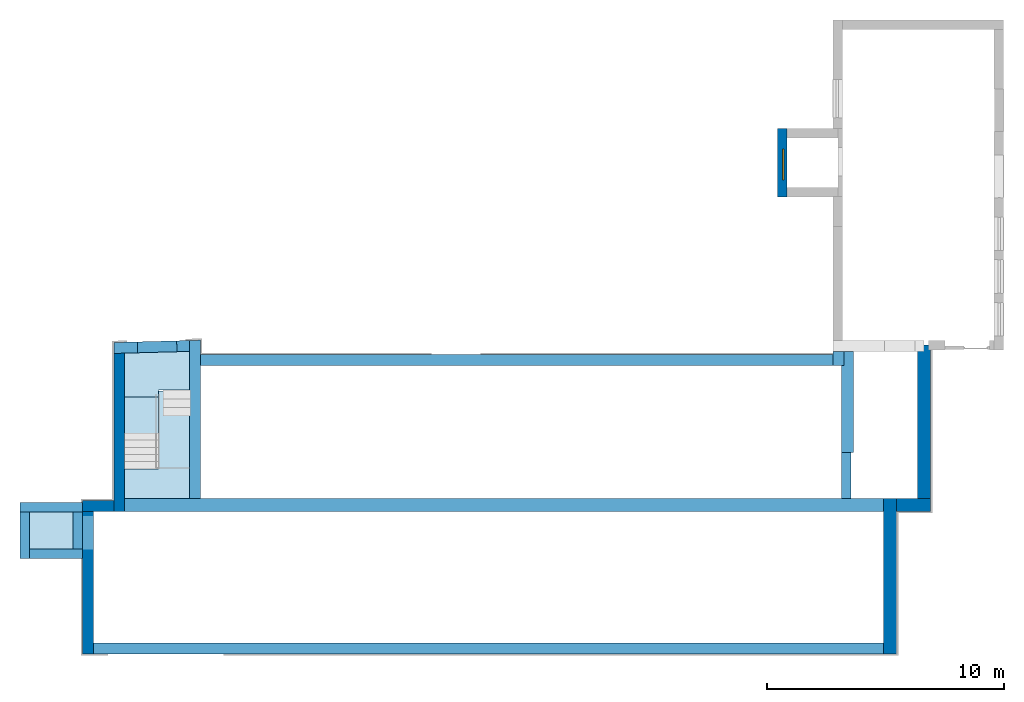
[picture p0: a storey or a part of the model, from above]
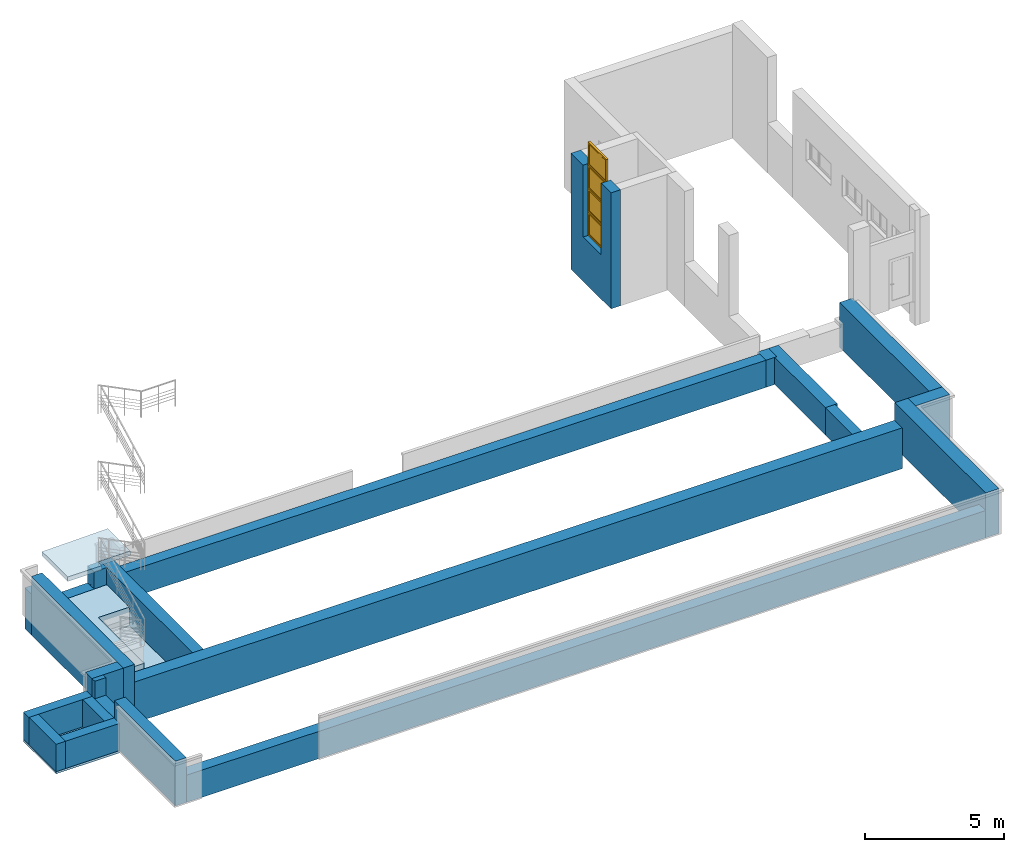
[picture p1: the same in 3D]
Properties of the parts of a building model (IFC2X3), part 1 of 5

# File
Description: ViewDefinition [CoordinationView_V2.0]
File name: P-1806
Time: 2020-05-27T14:10:02
Written by: The EXPRESS Data Manager Version 5.02.0100.07 : 28 Aug 2013
Made in: 20180216_1515(x64) - Exporter 19.0.0.405 - Alternate UI 19.1.0.0
Comment: STEP Physical File produced by: The EXPRESS Data Manager Version 5.02.0100.07 : 28 Aug 2013 * Module: EDMstepFileFactory/EDMstandAlone * Creation date: Wed May 27 14:10:02 2020 * Host: DESKTOP-ODL27HC * Database: C:\Users\kasutaja\AppData\Local\Temp\{E8C4CF71-2A94-4640-A6D8-2AE83B0C9C89}\ifc * Database version: 5507 * Database creation date: Wed May 27 14:09:39 2020 * Schema: IFC2X3 * Model: DataRepository.ifc * Model creation date: Wed May 27 14:09:40 2020 * Header model: DataRepository.ifc_HeaderModel * Header model creation date: Wed May 27 14:09:40 2020 * EDMuser: sdai-user * EDMgroup: sdai-group * License ID and type: 5605 : Permanent license. Expiry date: * EDMstepFileFactory options: 020000

# IfcProject, P-1806
LongName: Tartu Riigimaja, Riia 15 rekonstrueerimine; Phase: TP

# IfcSite, Surface:834248
RefLatitude: 59, 25, 2, 668762; RefLongitude: 24, 45, 13, 526916; RefElevation: 0 mm

# IfcBuilding
Pset_BuildingCommon - NumberOfStoreys: 11

# IfcBuildingStorey (11)
Name | LongName | Elevation (mm)
Vundament | Vundament | -1200
uus 1 korrus | uus 1 korrus | -135
1 korrus | 1 korrus | 3.097e-10
2 korrus | 2 korrus | 3350
uus 2 korrus | uus 2 korrus | 3875
3 korrus | 3 korrus | 6730.43
uus 3 korrus | uus 3 korrus | 7670
4 korrus | 4 korrus | 10060
uus Katus | uus Katus | 11805
Katusekorrus | Katusekorrus | 13600
Katus vent. | Katus vent. | 13800

# IfcSpace (128)
InteriorOrExteriorSpace: INTERNAL
Pset_SpaceCommon - Category: Rooms
Name | In | LongName = Nimetus | Reference | Nr | Kategooria / tüüp
101 | 1 korrus | Tuulekoda | Tuulekoda 101 | 101 | Avatud netopind
102 | 1 korrus | Vastuvõtt | Vastuvõtt 102 | 102 | Üüritavpind
103 | 1 korrus | Lift | Lift 103 | 103 | Vertikaalne ühendustee
105 | 1 korrus | Tuulekoda | Tuulekoda 105 | 105 | Avatud netopind
107 | 1 korrus | Koridor | Koridor 107 | 107 | Avatud netopind
108 | 1 korrus | WC | WC 108 | 108 | Avatud netopind
109 | 1 korrus | Riietusruum | Riietusruum 109 | 109 | Avatud netopind
110 | 1 korrus | Pesupesemise ruum | Pesupesemise ruum 110 | 110 | Avatud netopind
111 | 1 korrus | Dušširuum | Dušširuum 111 | 111 | Avatud netopind
112 | 1 korrus | Riietusruum | Riietusruum 112 | 112 | Avatud netopind
113 | 1 korrus | Dušširuum | Dušširuum 113 | 113 | Avatud netopind
114 | 1 korrus | Tuulekoda | Tuulekoda 114 | 114 | Avatud netopind
116 | 1 korrus | Büroo | Büroo 116 | 116 | Üüritavpind
115 | 1 korrus | Büroo | Büroo 115 | 115 | Üüritavpind
118 | 1 korrus | Klienditeenindamise saal (MTA+SKA) | Klienditeenindamise saal (MTA+SKA) 118 | 118 | Üüritavpind
120 | 1 korrus | Vestlusruum | Vestlusruum 120 | 120 | Üüritavpind
122 | 1 korrus | Koridor | Koridor 122 | 122 | Avatud netopind
123 | 1 korrus | Büroo | Büroo 123 | 123 | Üüritavpind
124 | 1 korrus | Koristusruum | Koristusruum 124 | 124 | Avatud netopind
125 | 1 korrus | WC | WC 125 | 125 | Avatud netopind
126 | 1 korrus | Trepikoda | Trepikoda 126 | 126 | Avatud netopind
128 | 1 korrus | Soojussõlm | Soojussõlm 128 | 128 | Tehniline pind
127 | 1 korrus | Ladu | Ladu 127 | 127 | Üüritavpind
201 | 2 korrus | Trepikoda | Trepikoda 201 | 201 | Vertikaalne ühendustee
202 | 2 korrus | Koridor | Koridor 202 | 202 | Avatud netopind
203 | 2 korrus | Lift | Lift 203 | 203 | Vertikaalne ühendustee
204 | 2 korrus | Nõupidamine | Nõupidamine 204 | 204 | Üüritavpind
205 | 2 korrus | Koridor | Koridor 205 | 205 | Avatud netopind
214 | 2 korrus | Puhkeruum | Puhkeruum 214 | 214 | Üüritavpind
217 | 2 korrus | Büroo | Büroo 217 | 217 | Üüritavpind
218 | 2 korrus | Koridor | Koridor 218 | 218 | Avatud netopind
219 | 2 korrus | WC | WC 219 | 219 | Avatud netopind
220 | 2 korrus | WC | WC 220 | 220 | Avatud netopind
222 | 2 korrus | Trepikoda | Trepikoda 222 | 222 | Vertikaalne ühendustee
223 | uus 2 korrus | Koridor | Koridor 223 | 223 | Avatud netopind
224 | uus 2 korrus | Eesruum | Eesruum 224 | 224 | Avatud netopind
225 | uus 2 korrus | Büroo | Büroo 225 | 225 | Üüritavpind
226 | uus 2 korrus | Koridor | Koridor 226 | 226 | Avatud netopind
227 | uus 2 korrus | WC | WC 227 | 227 | Avatud netopind
228 | uus 2 korrus | Büroo | Büroo 228 | 228 | Üüritavpind
229 | uus 2 korrus | Büroo | Büroo 229 | 229 | Üüritavpind
230 | uus 2 korrus | Büroo | Büroo 230 | 230 | Üüritavpind
231 | uus 2 korrus | Büroo | Büroo 231 | 231 | Üüritavpind
129 | uus 1 korrus | Tuulekoda | Tuulekoda 129 | 129 | Avatud netopind
130 | uus 1 korrus | Ooteala | Ooteala 130 | 130 | Üüritavpind
132 | uus 1 korrus | Koridor | Koridor 132 | 132 | Avatud netopind
133 | uus 1 korrus | WC | WC 133 | 133 | Avatud netopind
134 | uus 1 korrus | Riietusruum | Riietusruum 134 | 134 | Avatud netopind
135 | uus 1 korrus | Dušširuum | Dušširuum 135 | 135 | Avatud netopind
136 | uus 1 korrus | Varustuse ladu | Varustuse ladu 136 | 136 | Üüritavpind
138 | uus 1 korrus | Toiduproovide vastuvõtt | Toiduproovide vastuvõtt 138 | 138 | Üüritavpind
139 | uus 1 korrus | Tööruum | Tööruum 139 | 139 | Üüritavpind
140 | uus 1 korrus | Proovide vastuvõtt | Proovide vastuvõtt 140 | 140 | Üüritavpind
301 | 3 korrus | Trepikoda | Trepikoda 301 | 301 | Vertikaalne ühendustee
302 | 3 korrus | Koridor | Koridor 302 | 302 | Avatud netopind
303 | 3 korrus | Lift | Lift 303 | 303 | Vertikaalne ühendustee
304 | 3 korrus | Kaugtöökohad | Kaugtöökohad 304 | 304 | Üüritavpind
305 | 3 korrus | Koridor | Koridor 305 | 305 | Avatud netopind
306 | 3 korrus | Büroo | Büroo 306 | 306 | Üüritavpind
307 | 3 korrus | Büroo | Büroo 307 | 307 | Üüritavpind
308 | 3 korrus | Telo | Telo 308 | 308 | Üüritavpind
309 | 3 korrus | Büroo | Büroo 309 | 309 | Üüritavpind
310 | 3 korrus | Büroo | Büroo 310 | 310 | Üüritavpind
311 | 3 korrus | Büroo | Büroo 311 | 311 | Üüritavpind
312 | 3 korrus | Büroo | Büroo 312 | 312 | Üüritavpind
313 | 3 korrus | Büroo | Büroo 313 | 313 | Üüritavpind
314 | 3 korrus | Vestla | Vestla 314 | 314 | Üüritavpind
315 | 3 korrus | Puhkeruum | Puhkeruum 315 | 315 | Üüritavpind
316 | 3 korrus | Büroo | Büroo 316 | 316 | Üüritavpind
317 | 3 korrus | Büroo | Büroo 317 | 317 | Üüritavpind
318 | 3 korrus | Büroo | Büroo 318 | 318 | Üüritavpind
319 | 3 korrus | Abiruum | Abiruum 319 | 319 | Üüritavpind
320 | 3 korrus | Koridor | Koridor 320 | 320 | Avatud netopind
321 | 3 korrus | WC | WC 321 | 321 | Avatud netopind
322 | 3 korrus | WC | WC 322 | 322 | Avatud netopind
324 | 3 korrus | Trepikoda | Trepikoda 324 | 324 | Vertikaalne ühendustee
325 | 3 korrus | Server | Server 325 | 325 | Tehniline pind
326 | uus 3 korrus | Koridor | Koridor 326 | 326 | Avatud netopind
327 | uus 3 korrus | Koridor | Koridor 327 | 327 | Avatud netopind
330 | uus 3 korrus | Nõupidamine | Nõupidamine 330 | 330 | Üüritavpind
331 | uus 3 korrus | Büroo | Büroo 331 | 331 | Üüritavpind
401 | 4 korrus | Trepikoda | Trepikoda 401 | 401 | Vertikaalne ühendustee
402 | 4 korrus | Koridor | Koridor 402 | 402 | Avatud netopind
403 | 4 korrus | Lift | Lift 403 | 403 | Vertikaalne ühendustee
404 | 4 korrus | Büroo | Büroo 404 | 404 | Üüritavpind
405 | 4 korrus | Koridor | Koridor 405 | 405 | Avatud netopind
413 | 4 korrus | Puhkeruum | Puhkeruum 413 | 413 | Üüritavpind
414 | 4 korrus | Büroo | Büroo 414 | 414 | Üüritavpind
416 | 4 korrus | Büroo | Büroo 416 | 416 | Üüritavpind
417 | 4 korrus | Büroo | Büroo 417 | 417 | Üüritavpind
418 | 4 korrus | Nõupidamine | Nõupidamine 418 | 418 | Üüritavpind
419 | 4 korrus | Koridor | Koridor 419 | 419 | Avatud netopind
420 | 4 korrus | WC | WC 420 | 420 | Avatud netopind
421 | 4 korrus | WC | WC 421 | 421 | Avatud netopind
423 | 4 korrus | Trepikoda | Trepikoda 423 | 423 | Vertikaalne ühendustee
501 | Katusekorrus | Lift | Lift 501 | 501 | Vertikaalne ühendustee
328 | uus 3 korrus | Büroo | Büroo 328 | 328 | Üüritavpind
329 | uus 3 korrus | WC | WC 329 | 329 | Avatud netopind
117 | 1 korrus | Büroo | Büroo 117 | 117 | Üüritavpind
406 | 4 korrus | Büroo | Büroo 406 | 406 | Üüritavpind
408 | 4 korrus | Vestla | Vestla 408 | 408 | Üüritavpind
409 | 4 korrus | Büroo | Büroo 409 | 409 | Üüritavpind
410 | 4 korrus | Vestla | Vestla 410 | 410 | Üüritavpind
411 | 4 korrus | Garderoob | Garderoob 411 | 411 | Üüritavpind
412 | 4 korrus | Kontoritarbed | Kontoritarbed 412 | 412 | Üüritavpind
206 | 2 korrus | Büroo | Büroo 206 | 206 | Üüritavpind
207 | 2 korrus | Telo | Telo 207 | 207 | Üüritavpind
208 | 2 korrus | Büroo | Büroo 208 | 208 | Üüritavpind
209 | 2 korrus | Büroo | Büroo 209 | 209 | Üüritavpind
210 | 2 korrus | Büroo | Büroo 210 | 210 | Üüritavpind
215 | 2 korrus | Dok.hoidla | Dok.hoidla 215 | 215 | Üüritavpind
216 | 2 korrus | Büroo | Büroo 216 | 216 | Üüritavpind
503 | Katusekorrus | Vent.ruum | Vent.ruum 503 | 503 | Tehniline pind
141 | 1 korrus | Ladu PMA | Ladu PMA 141 | 141 | Üüritavpind
142 | 1 korrus | Ladu KKA | Ladu KKA 142 | 142 | Üüritavpind
211 | 2 korrus | Vestla | Vestla 211 | 211 | Üüritavpind
212 | 2 korrus | Büroo | Büroo 212 | 212 | Üüritavpind
139 | uus 1 korrus | Nõrkvooluruum | Nõrkvooluruum 139 | 139 | Tehniline pind
143 | uus 1 korrus | Abiruum | Abiruum 143 | 143 | Üüritavpind
502 | Katusekorrus | Vent.ruum | Vent.ruum 502 | 502 | Tehniline pind
131 | uus 1 korrus | Vastuvõtt | Vastuvõtt 131 | 131 | Üüritavpind
106 | 1 korrus | INVA WC | INVA WC 106 | 106 | Avatud netopind
104 | 1 korrus | Trepikoda | Trepikoda 104 | 104 | Avatud netopind
119 | 1 korrus | Vestlusruum | Vestlusruum 119 | 119 | Üüritavpind
121 | 1 korrus | Vestlusruum | Vestlusruum 121 | 121 | Üüritavpind
132a | uus 1 korrus | Lift | Lift 132a | 132a | Vertikaalne ühendustee
226a | uus 2 korrus | Lift | Lift 226a | 226a | Vertikaalne ühendustee
327a | uus 3 korrus | Lift | Lift 327a | 327a | Vertikaalne ühendustee

# IfcBuildingElementProxy: Reeper, Reeper1:Reeper:1055131
In: 1 korrus
Material: GEE-punane
Pset_BuildingElementProxyCommon - Reference: Reeper

# IfcColumn: 250x250, Betoon post:250x250:506675
In: 1 korrus
Type - ElementType: 250x250; PredefinedType: COLUMN
Material: Betoon
Pset_ColumnCommon - LoadBearing: no; IsExternal: no; Reference: 250x250; Slope: 0 deg

# IfcColumn: D200, Pipe-Column:D200:1313115
In: uus 1 korrus
Type - ElementType: D200; PredefinedType: COLUMN; Classification: B10 Superstructure (Uniformat)
Material: Metal - Steel - ASTM A53
Pset_ColumnCommon - IsExternal: no; LoadBearing: yes; Slope: 0 deg; Reference: D200

# IfcColumn: GENEERILINE - KONSTRUKTRIOON 260 x 260 (2)
In: 1 korrus
Type - ElementType: GENEERILINE - KONSTRUKTRIOON 260 x 260; PredefinedType: COLUMN
Material: GENEERILINE - KONSTRUKTRIOON
Pset_ColumnCommon - LoadBearing: no; IsExternal: no; Reference: GENEERILINE - KONSTRUKTRIOON 260 x 260; Slope: 5156.62 deg

# IfcCurtainWall: Curtain Wall:Klaasfassaad (2)
In: 3 korrus
Pset_CurtainWallCommon - IsExternal: yes; Reference: Klaasfassaad
AR_IFC_SEINAD - 01.Nimetus: Klaasfassaad; 02.Materjal: Klaas+alumiinium; 04.Tulepüsivus: -; 05.Asukoha info: Exterior; 06.Kandevelementide eristatud: nonbearing; 07.Helipidavus: 34 dB; 06.Soojusläbivus: 1,0W/m2K; Phase Created: New Construction
Name (Curtain Wall:Klaasfassaad:...) | 03.Kategooria / tüüp | Group
1451082 | KLF-01 | Model Group:KLF-01:1450670
1658890 | KLF-05 | Model Group:KLF-04:1658778

# IfcCurtainWall: Curtain Wall:Klaasfassaad2 (2)
In: 3 korrus
Pset_CurtainWallCommon - IsExternal: yes; Reference: Klaasfassaad2
AR_IFC_SEINAD - 01.Nimetus: Klaasfassaad; 02.Materjal: Klaas+alumiinium; 04.Tulepüsivus: -; 05.Asukoha info: Exterior; 06.Kandevelementide eristatud: nonbearing; 07.Helipidavus: 34 dB; 06.Soojusläbivus: 1,0W/m2K; Phase Created: New Construction
Name (Curtain Wall:Klaasfassaad2:...) | 03.Kategooria / tüüp | Group
1453336 | KLF-02 | Model Group:KLF-02:1453116
1660883 | KLF-03 | Model Group:KLF-03:1660694

# IfcCurtainWall: Curtain Wall:Klaassein KLS-01 (2)
In: 1 korrus
Pset_CurtainWallCommon - IsExternal: no; Reference: Klaassein KLS-01
AR_IFC_SEINAD - 01.Nimetus: Klaassein; 02.Materjal: Klaas; 03.Kategooria / tüüp: KLS-01; 04.Tulepüsivus: -; 05.Asukoha info: Interior; 06.Kandevelementide eristatud: nonbearing; 07.Helipidavus: 40 dB; 06.Soojusläbivus: -; Phase Created: New Construction
Name (Curtain Wall:Klaassein KLS-01:...)
329681
1662676

# IfcCurtainWall: Curtain Wall:Klaassein KLS-02, Curtain Wall:Klaassein KLS-02:341501
In: 1 korrus
Pset_CurtainWallCommon - IsExternal: no; Reference: Klaassein KLS-02
AR_IFC_SEINAD - 01.Nimetus: Klaassein; 02.Materjal: Klaas; 03.Kategooria / tüüp: KLS-02; 04.Tulepüsivus: -; 05.Asukoha info: Interior; 06.Kandevelementide eristatud: nonbearing; 07.Helipidavus: 40 dB; 06.Soojusläbivus: -; Phase Created: New Construction

# IfcCurtainWall: Curtain Wall:Klaassein KLS-03, Curtain Wall:Klaassein KLS-03:495734
In: 1 korrus
Pset_CurtainWallCommon - IsExternal: no; Reference: Klaassein KLS-03
AR_IFC_SEINAD - 01.Nimetus: Klaassein; 02.Materjal: Klaas; 03.Kategooria / tüüp: KLS-03; 04.Tulepüsivus: -; 05.Asukoha info: Interior; 06.Kandevelementide eristatud: nonbearing; 07.Helipidavus: 40 dB; 06.Soojusläbivus: -; Phase Created: New Construction

# IfcCurtainWall: Curtain Wall:Klaassein KLS-04, Curtain Wall:Klaassein KLS-04:489045
In: 1 korrus
Pset_CurtainWallCommon - IsExternal: no; Reference: Klaassein KLS-04
AR_IFC_SEINAD - 01.Nimetus: Klaassein; 02.Materjal: Klaas; 03.Kategooria / tüüp: KLS-04; 04.Tulepüsivus: -; 05.Asukoha info: Interior; 06.Kandevelementide eristatud: nonbearing; 07.Helipidavus: 40 dB; 06.Soojusläbivus: -; Phase Created: New Construction

# IfcCurtainWall: Curtain Wall:Klaassein KLS-05 (2)
In: 2 korrus
Pset_CurtainWallCommon - IsExternal: no; Reference: Klaassein KLS-05
AR_IFC_SEINAD - 01.Nimetus: Klaassein; 02.Materjal: Klaas; 03.Kategooria / tüüp: KLS-05; 04.Tulepüsivus: -; 05.Asukoha info: Interior; 06.Kandevelementide eristatud: nonbearing; 07.Helipidavus: 40 dB; 06.Soojusläbivus: -; Phase Created: New Construction
Name (Curtain Wall:Klaassein KLS-05:...)
1333739
1334402

# IfcCurtainWall: Curtain Wall:Klaassein KLS-07 (3)
Pset_CurtainWallCommon - IsExternal: no; Reference: Klaassein KLS-07
AR_IFC_SEINAD - 01.Nimetus: Klaassein; 02.Materjal: Klaas; 03.Kategooria / tüüp: KLS-07; 04.Tulepüsivus: -; 05.Asukoha info: Interior; 06.Kandevelementide eristatud: nonbearing; 07.Helipidavus: 40 dB; 06.Soojusläbivus: -; Phase Created: New Construction
Name (Curtain Wall:Klaassein KLS-07:...) | In
515357 | 2 korrus
569290 | 3 korrus
580453 | 4 korrus

# IfcCurtainWall: Curtain Wall:Klaassein KLS-08, Curtain Wall:Klaassein KLS-08:555677
In: 2 korrus
Pset_CurtainWallCommon - IsExternal: no; Reference: Klaassein KLS-08
AR_IFC_SEINAD - 01.Nimetus: Klaassein; 02.Materjal: Klaas; 03.Kategooria / tüüp: KLS-08; 04.Tulepüsivus: -; 05.Asukoha info: Interior; 06.Kandevelementide eristatud: nonbearing; 07.Helipidavus: 40 dB; 06.Soojusläbivus: -; Phase Created: New Construction

# IfcCurtainWall: Curtain Wall:Klaassein KLS-09, Curtain Wall:Klaassein KLS-09:555087
In: 2 korrus
Pset_CurtainWallCommon - IsExternal: no; Reference: Klaassein KLS-09
AR_IFC_SEINAD - 01.Nimetus: Klaassein; 02.Materjal: Klaas; 03.Kategooria / tüüp: KLS-09; 04.Tulepüsivus: -; 05.Asukoha info: Interior; 06.Kandevelementide eristatud: nonbearing; 07.Helipidavus: 40 dB; 06.Soojusläbivus: -; Phase Created: New Construction

# IfcCurtainWall: Curtain Wall:Klaassein KLS-10 (2)
Pset_CurtainWallCommon - IsExternal: no; Reference: Klaassein KLS-10
AR_IFC_SEINAD - 01.Nimetus: Klaassein; 02.Materjal: Klaas; 04.Tulepüsivus: -; 05.Asukoha info: Interior; 06.Kandevelementide eristatud: nonbearing; 07.Helipidavus: 40 dB; 06.Soojusläbivus: -; Phase Created: New Construction
Name (Curtain Wall:Klaassein KLS-10:...) | In | 03.Kategooria / tüüp
575476 | 3 korrus | KLS-01
1117689 | 2 korrus | KLS-10

# IfcCurtainWall: Curtain Wall:Klaassein KLS-11, Curtain Wall:Klaassein KLS-11:520277
In: 2 korrus
Pset_CurtainWallCommon - IsExternal: no; Reference: Klaassein KLS-11
AR_IFC_SEINAD - 01.Nimetus: Klaassein; 02.Materjal: Klaas; 03.Kategooria / tüüp: KLS-11; 04.Tulepüsivus: -; 05.Asukoha info: Interior; 06.Kandevelementide eristatud: nonbearing; 07.Helipidavus: 40 dB; 06.Soojusläbivus: -; Phase Created: New Construction

# IfcCurtainWall: Curtain Wall:Klaassein KLS-12 (2)
Pset_CurtainWallCommon - IsExternal: no; Reference: Klaassein KLS-12
AR_IFC_SEINAD - 01.Nimetus: Klaassein; 02.Materjal: Klaas; 03.Kategooria / tüüp: KLS-12; 04.Tulepüsivus: -; 05.Asukoha info: Interior; 06.Kandevelementide eristatud: nonbearing; 07.Helipidavus: 40 dB; 06.Soojusläbivus: -; Phase Created: New Construction
Name (Curtain Wall:Klaassein KLS-12:...) | In
930844 | uus 2 korrus
1005810 | uus 3 korrus

# IfcCurtainWall: Curtain Wall:Klaassein KLS-13, Curtain Wall:Klaassein KLS-13:930512
In: uus 2 korrus
Pset_CurtainWallCommon - IsExternal: no; Reference: Klaassein KLS-13
AR_IFC_SEINAD - 01.Nimetus: Klaassein; 02.Materjal: Klaas; 03.Kategooria / tüüp: KLS-13; 04.Tulepüsivus: -; 05.Asukoha info: Interior; 06.Kandevelementide eristatud: nonbearing; 07.Helipidavus: 40 dB; 06.Soojusläbivus: -; Phase Created: New Construction

# IfcCurtainWall: Curtain Wall:Klaassein KLS-14, Curtain Wall:Klaassein KLS-14:930147
In: uus 2 korrus
Pset_CurtainWallCommon - IsExternal: no; Reference: Klaassein KLS-14
AR_IFC_SEINAD - 01.Nimetus: Klaassein; 02.Materjal: Klaas; 03.Kategooria / tüüp: KLS-14; 04.Tulepüsivus: -; 05.Asukoha info: Interior; 06.Kandevelementide eristatud: nonbearing; 07.Helipidavus: 40 dB; 06.Soojusläbivus: -; Phase Created: New Construction

# IfcCurtainWall: Curtain Wall:Klaassein KLS-15, Curtain Wall:Klaassein KLS-15:927985
In: uus 2 korrus
Pset_CurtainWallCommon - IsExternal: no; Reference: Klaassein KLS-15
AR_IFC_SEINAD - 01.Nimetus: Klaassein; 02.Materjal: Klaas; 03.Kategooria / tüüp: KLS-15; 04.Tulepüsivus: -; 05.Asukoha info: Interior; 06.Kandevelementide eristatud: nonbearing; 07.Helipidavus: 40 dB; 06.Soojusläbivus: -; Phase Created: New Construction

# IfcCurtainWall: Curtain Wall:Klaassein KLS-16, Curtain Wall:Klaassein KLS-16:929398
In: uus 2 korrus
Pset_CurtainWallCommon - IsExternal: no; Reference: Klaassein KLS-16
AR_IFC_SEINAD - 01.Nimetus: Klaassein; 02.Materjal: Klaas; 03.Kategooria / tüüp: KLS-16; 04.Tulepüsivus: -; 05.Asukoha info: Interior; 06.Kandevelementide eristatud: nonbearing; 07.Helipidavus: 40 dB; 06.Soojusläbivus: -; Phase Created: New Construction

# IfcCurtainWall: Curtain Wall:Klaassein KLS-17, Curtain Wall:Klaassein KLS-17:568486
In: 3 korrus
Pset_CurtainWallCommon - IsExternal: no; Reference: Klaassein KLS-17
AR_IFC_SEINAD - 01.Nimetus: Klaassein; 02.Materjal: Klaas; 03.Kategooria / tüüp: KLS-17; 04.Tulepüsivus: -; 05.Asukoha info: Interior; 06.Kandevelementide eristatud: nonbearing; 07.Helipidavus: 40 dB; 06.Soojusläbivus: -; Phase Created: New Construction

# IfcCurtainWall: Curtain Wall:Klaassein KLS-18, Curtain Wall:Klaassein KLS-18:567760
In: 3 korrus
Pset_CurtainWallCommon - IsExternal: no; Reference: Klaassein KLS-18
AR_IFC_SEINAD - 01.Nimetus: Klaassein; 02.Materjal: Klaas; 03.Kategooria / tüüp: KLS-18; 04.Tulepüsivus: -; 05.Asukoha info: Interior; 06.Kandevelementide eristatud: nonbearing; 07.Helipidavus: 40 dB; 06.Soojusläbivus: -; Phase Created: New Construction

# IfcCurtainWall: Curtain Wall:Klaassein KLS-19, Curtain Wall:Klaassein KLS-19:562941
In: 3 korrus
Pset_CurtainWallCommon - IsExternal: no; Reference: Klaassein KLS-19
AR_IFC_SEINAD - 01.Nimetus: Klaassein; 02.Materjal: Klaas; 03.Kategooria / tüüp: KLS-19; 04.Tulepüsivus: -; 05.Asukoha info: Interior; 06.Kandevelementide eristatud: nonbearing; 07.Helipidavus: 40 dB; 06.Soojusläbivus: -; Phase Created: New Construction

# IfcCurtainWall: Curtain Wall:Klaassein KLS-20 (2)
Pset_CurtainWallCommon - IsExternal: no; Reference: Klaassein KLS-20
AR_IFC_SEINAD - 01.Nimetus: Klaassein; 02.Materjal: Klaas; 03.Kategooria / tüüp: KLS-20; 04.Tulepüsivus: -; 05.Asukoha info: Interior; 06.Kandevelementide eristatud: nonbearing; 07.Helipidavus: 40 dB; 06.Soojusläbivus: -; Phase Created: New Construction
Name (Curtain Wall:Klaassein KLS-20:...) | In
562882 | 3 korrus
563014 | 4 korrus

# IfcCurtainWall: Curtain Wall:Klaassein KLS-21, Curtain Wall:Klaassein KLS-21:574380
In: 3 korrus
Pset_CurtainWallCommon - IsExternal: no; Reference: Klaassein KLS-21
AR_IFC_SEINAD - 01.Nimetus: Klaassein; 02.Materjal: Klaas; 03.Kategooria / tüüp: KLS-21; 04.Tulepüsivus: -; 05.Asukoha info: Interior; 06.Kandevelementide eristatud: nonbearing; 07.Helipidavus: 40 dB; 06.Soojusläbivus: -; Phase Created: New Construction

# IfcCurtainWall: Curtain Wall:Klaassein KLS-22, Curtain Wall:Klaassein KLS-22:574861
In: 3 korrus
Pset_CurtainWallCommon - IsExternal: no; Reference: Klaassein KLS-22
AR_IFC_SEINAD - 01.Nimetus: Klaassein; 02.Materjal: Klaas; 03.Kategooria / tüüp: KLS-22; 04.Tulepüsivus: -; 05.Asukoha info: Interior; 06.Kandevelementide eristatud: nonbearing; 07.Helipidavus: 40 dB; 06.Soojusläbivus: -; Phase Created: New Construction

# IfcCurtainWall: Curtain Wall:Klaassein KLS-23, Curtain Wall:Klaassein KLS-23:934556
In: uus 3 korrus
Pset_CurtainWallCommon - IsExternal: no; Reference: Klaassein KLS-23
AR_IFC_SEINAD - 01.Nimetus: Klaassein; 02.Materjal: Klaas; 03.Kategooria / tüüp: KLS-23; 04.Tulepüsivus: -; 05.Asukoha info: Interior; 06.Kandevelementide eristatud: nonbearing; 07.Helipidavus: 40 dB; 06.Soojusläbivus: -; Phase Created: New Construction

# IfcCurtainWall: Curtain Wall:Klaassein KLS-24, Curtain Wall:Klaassein KLS-24:580407
In: 4 korrus
Pset_CurtainWallCommon - IsExternal: no; Reference: Klaassein KLS-24
AR_IFC_SEINAD - 01.Nimetus: Klaassein; 02.Materjal: Klaas; 03.Kategooria / tüüp: KLS-24; 04.Tulepüsivus: -; 05.Asukoha info: Interior; 06.Kandevelementide eristatud: nonbearing; 07.Helipidavus: 40 dB; 06.Soojusläbivus: -; Phase Created: New Construction

# IfcCurtainWall: Curtain Wall:Klaassein KLS-25, Curtain Wall:Klaassein KLS-25:581564
In: 4 korrus
Pset_CurtainWallCommon - IsExternal: no; Reference: Klaassein KLS-25
AR_IFC_SEINAD - 01.Nimetus: Klaassein; 02.Materjal: Klaas; 03.Kategooria / tüüp: KLS-25; 04.Tulepüsivus: -; 05.Asukoha info: Interior; 06.Kandevelementide eristatud: nonbearing; 07.Helipidavus: 40 dB; 06.Soojusläbivus: -; Phase Created: New Construction

# IfcCurtainWall: Curtain Wall:Klaassein KLS-26, Curtain Wall:Klaassein KLS-26:581264
In: 4 korrus
Pset_CurtainWallCommon - IsExternal: no; Reference: Klaassein KLS-26
AR_IFC_SEINAD - 01.Nimetus: Klaassein; 02.Materjal: Klaas; 03.Kategooria / tüüp: KLS-26; 04.Tulepüsivus: -; 05.Asukoha info: Interior; 06.Kandevelementide eristatud: nonbearing; 07.Helipidavus: 40 dB; 06.Soojusläbivus: -; Phase Created: New Construction

# IfcCurtainWall: Curtain Wall:Klaassein KLS-27, Curtain Wall:Klaassein KLS-27:580366
In: 4 korrus
Pset_CurtainWallCommon - IsExternal: no; Reference: Klaassein KLS-27
AR_IFC_SEINAD - 01.Nimetus: Klaassein; 02.Materjal: Klaas; 03.Kategooria / tüüp: KLS-27; 04.Tulepüsivus: -; 05.Asukoha info: Interior; 06.Kandevelementide eristatud: nonbearing; 07.Helipidavus: 40 dB; 06.Soojusläbivus: -; Phase Created: New Construction

# IfcCurtainWall: Curtain Wall:Klaassein KLS-28, Curtain Wall:Klaassein KLS-28:1304981
In: 4 korrus
Pset_CurtainWallCommon - IsExternal: no; Reference: Klaassein KLS-28
AR_IFC_SEINAD - 01.Nimetus: Sisesein; 02.Materjal: Kips; 03.Kategooria / tüüp: SS-3; 04.Tulepüsivus: -; 05.Asukoha info: Interior; 06.Kandevelementide eristatud: nonbearing; 07.Helipidavus: 48dB; 06.Soojusläbivus: -; Phase Created: New Construction

# IfcDistributionControlElement: ATS, Control_Unit-Suppression_System-Kidde_Fire_Systems-ARIES:ATS:1090340
In: 101
Type - Material: Steel - Kidde Fenwal - Red
Pset_ManufacturerTypeInformation - Manufacturer: Kidde Fire Systems

# IfcDoor: 1000x2100_klaasiga_välisuks (2)
Type - OperationType: FOLDING_TO_LEFT; ParameterTakesPrecedence: no; Sizeable: no; Material: _Alumiiniumprofiil - must, Steel/Aluminium, Glass
Type - Ühepoolsed:1000x2100_klaasiga_välisuks:923893 - PanelOperation: FOLDING
OverallHeight: 2100 mm; OverallWidth: 2240 mm
Pset_DoorCommon - IsExternal: no; Reference: 1000x2100_klaasiga_välisuks
Name (Ühepoolsed:1000x2100_klaasiga_välisuks:...) | In
923893 | uus 2 korrus
933235 | uus 3 korrus

# IfcDoor: 1000x2200_välisuks klaasiga (2)
In: uus 1 korrus
Type - OperationType: FOLDING_TO_LEFT; ParameterTakesPrecedence: no; Sizeable: no; Material: _Alumiiniumprofiil - must, Steel/Aluminium, Glass
Type - Ühepoolsed:1000x2200_välisuks klaasiga:394254 - PanelOperation: FOLDING
OverallHeight: 2200 mm; OverallWidth: 1000 mm
Pset_DoorCommon - IsExternal: yes; Reference: 1000x2200_välisuks klaasiga
AR_IFC_UKSED - 01.Nimetus: Välisuks; 02.Materjal: Alumiinium; 05.Asukoha info: Exterior; 06.Soojusläbivus: 1.0 W/m²K; 07.Helipidavus: 34 dB; 08.Veepidavus: 7A; 09.Õhuläbilaskvus: klass 4; 10.Tulekindlus: -; 11.Vastupanu tulekoormusele: C3; 12.Klaaspakett: 3x klaaspakett; 13.Klaasingu erisused: Tripleksklaas; 14.Päikesekiirgus tegur (g-väärtus): 0.6; 15.Avanemine: Folding to Right; 16.Liigendatus: kahepoolne; 17.Sulused, lukustus: ASSA ABLOY liugveovarrega sulgur, sulgemisjärjesti; 18.Viimistlus: RAL8019; 19.Mudel või toote tunnus: -; 20.Tootja: -
Name (Ühepoolsed:1000x2200_välisuks klaasiga:...) | 03.Kategooria / tüüp | 04.Avamõõdu geomeetria
394254 | VU-08 | 1600x2650
408534 | VU-07 | 1800x2650

# IfcDoor: KONE_LDO_KES600_2L_P28_L1 (2)
In: uus 1 korrus
Type - OperationType: FOLDING_TO_LEFT; ParameterTakesPrecedence: no; Sizeable: no; Material: Glass, Default
Type - KONE_LDO_KES600_2L_P28_L1:KONE_LDO_KES600_2L_P28_L1:1652579 - PanelOperation: FOLDING
OverallHeight: 2944 mm; OverallWidth: 1522 mm
Pset_DoorCommon - IsExternal: no; Reference: KONE_LDO_KES600_2L_P28_L1
Name (KONE_LDO_KES600_2L_P28_L1:KONE_LDO_KES600_2L_P28_L1:...)
1652579
1652580

# IfcDoor: KONE_LDO_KES600_2L_P28_L1, KONE_LDO_KES600_2L_P28_L1:KONE_LDO_KES600_2L_P28_L1:1652581
In: uus 1 korrus
Type - OperationType: FOLDING_TO_LEFT; ParameterTakesPrecedence: no; Sizeable: no; Material: Glass, Default
Type - KONE_LDO_KES600_2L_P28_L1:KONE_LDO_KES600_2L_P28_L1:1652581 - PanelOperation: FOLDING
OverallHeight: 2944 mm; OverallWidth: 1522 mm
Pset_DoorCommon - IsExternal: no; Reference: KONE_LDO_KES600_2L_P28_L1

# IfcDoor: Klaasuks (30)
Type - ParameterTakesPrecedence: no; Sizeable: no; Classification: B2030100 Glazed Doors & Entrances (Uniformat); Material: Glass, Aluminum
Pset_DoorCommon - IsExternal: no; Reference: Klaasuks
Name (Door-Curtain-Wall-Single-Glass:Klaasuks:...) | In | OverallHeight (mm) | OverallWidth (mm)
489052 | 1 korrus | 2090 | 890
495741 | 1 korrus | 2090 | 880
515378 | 2 korrus | 2110 | 880
1337265 | 2 korrus | 2080 | 888.452
1116301 | 2 korrus | 2090 | 890
555684 | 2 korrus | 2080 | 880
562889 | 3 korrus | 2080 | 880
562942 | 3 korrus | 2090 | 891
563021 | 4 korrus | 2080 | 880
567767 | 3 korrus | 2090 | 880
1101094 | 3 korrus | 2080 | 880
569308 | 3 korrus | 2110 | 880
574387 | 3 korrus | 2080 | 880
574868 | 3 korrus | 2080 | 880
575483 | 3 korrus | 2090 | 880
580373 | 4 korrus | 2090 | 880
580414 | 4 korrus | 2090 | 880
580471 | 4 korrus | 2110 | 880
581282 | 4 korrus | 2110 | 880
581600 | 4 korrus | 2110 | 880
1458226 | uus 2 korrus | 2500 | 880
927990 | uus 2 korrus | 2500 | 880
930150 | uus 2 korrus | 2500 | 880
930515 | uus 2 korrus | 2500 | 880
930845 | uus 2 korrus | 2500 | 890
934559 | uus 3 korrus | 2500 | 880
1005811 | uus 3 korrus | 2500 | 890
1117694 | 2 korrus | 2090 | 756.991
1333746 | 2 korrus | 2080 | 880
1334409 | 2 korrus | 2080 | 880

# IfcDoor: Manteluks (3)
In: 1 korrus
Type - ParameterTakesPrecedence: no; Sizeable: no; Classification: B2030100 Glazed Doors & Entrances (Uniformat); Material: __Uks_hele tamm, Aluminum
OverallHeight: 2080 mm
Pset_DoorCommon - IsExternal: no; Reference: Manteluks
Name (Door-Curtain-Wall-Single-Glass:Manteluks:...) | OverallWidth (mm)
329688 | 888
341508 | 892
1662683 | 888

# IfcDoor: SU-01, Ühepoolsed:SU-01:1080922
In: 4 korrus
Type - OperationType: FOLDING_TO_LEFT; ParameterTakesPrecedence: no; Sizeable: no; Material: _Alumiiniumprofiil - must, __Uks_hele tamm, Glass
Type - Ühepoolsed:SU-01:1080922 - PanelOperation: FOLDING
OverallHeight: 2100 mm; OverallWidth: 800 mm
Pset_DoorCommon - IsExternal: no; Reference: SU-01
AR_IFC_UKSED - 01.Nimetus: Siseuks; 02.Materjal: Puit; 03.Kategooria / tüüp: SU-01; 04.Avamõõdu geomeetria: 800x2100; 05.Asukoha info: Interior; 06.Soojusläbivus: -; 07.Helipidavus: 34 dB; 08.Veepidavus: -; 09.Õhuläbilaskvus: -; 10.Tulekindlus: -; 11.Vastupanu tulekoormusele: -; 12.Klaaspakett: karastatud klaas; 13.Klaasingu erisused: -; 14.Päikesekiirgus tegur (g-väärtus): -; 15.Avanemine: Folding to Right; 16.Liigendatus: -; 17.Sulused, lukustus: -; 18.Viimistlus: Tammespoon; 19.Mudel või toote tunnus: -; 20.Tootja: -

# IfcDoor: SU-01., Ühepoolsed:SU-01.:1080916
In: 4 korrus
Type - OperationType: FOLDING_TO_LEFT; ParameterTakesPrecedence: no; Sizeable: no; Material: _Alumiiniumprofiil - must, __Uks_hele tamm, Glass
Type - Ühepoolsed:SU-01.:1080916 - PanelOperation: FOLDING
OverallHeight: 2100 mm; OverallWidth: 800 mm
Pset_DoorCommon - IsExternal: no; Reference: SU-01.
AR_IFC_UKSED - 01.Nimetus: Siseuks; 02.Materjal: Puit; 03.Kategooria / tüüp: SU-01; 04.Avamõõdu geomeetria: 800x2100; 05.Asukoha info: Interior; 06.Soojusläbivus: -; 07.Helipidavus: 34 dB; 08.Veepidavus: -; 09.Õhuläbilaskvus: -; 10.Tulekindlus: -; 11.Vastupanu tulekoormusele: -; 12.Klaaspakett: karastatud klaas; 13.Klaasingu erisused: -; 14.Päikesekiirgus tegur (g-väärtus): -; 15.Avanemine: Folding to Left; 16.Liigendatus: -; 17.Sulused, lukustus: -; 18.Viimistlus: Tammespoon; 19.Mudel või toote tunnus: -; 20.Tootja: -

# IfcDoor: SU-02, Ühepoolsed:SU-02:239855
In: 4 korrus
Type - OperationType: FOLDING_TO_LEFT; ParameterTakesPrecedence: no; Sizeable: no; Material: _Alumiiniumprofiil - must, __Uks_hele tamm, Glass
Type - Ühepoolsed:SU-02:239855 - PanelOperation: FOLDING
OverallHeight: 2100 mm; OverallWidth: 900 mm
Pset_DoorCommon - IsExternal: no; Reference: SU-02
AR_IFC_UKSED - 01.Nimetus: Siseuks; 02.Materjal: Puit; 03.Kategooria / tüüp: SU-02; 04.Avamõõdu geomeetria: 900x2100; 05.Asukoha info: Interior; 06.Soojusläbivus: -; 07.Helipidavus: 34 dB; 08.Veepidavus: -; 09.Õhuläbilaskvus: -; 10.Tulekindlus: -; 11.Vastupanu tulekoormusele: -; 12.Klaaspakett: karastatud klaas; 13.Klaasingu erisused: -; 14.Päikesekiirgus tegur (g-väärtus): -; 15.Avanemine: Folding to Right; 16.Liigendatus: -; 17.Sulused, lukustus: -; 18.Viimistlus: Tammespoon; 19.Mudel või toote tunnus: -; 20.Tootja: -

# IfcDoor: SU-02 (6)
Type - OperationType: FOLDING_TO_LEFT; ParameterTakesPrecedence: no; Sizeable: no; Material: _Alumiiniumprofiil - must, __Uks_hele tamm, Glass
Type - Ühepoolsed:SU-02:323160 - PanelOperation: FOLDING
OverallHeight: 2100 mm; OverallWidth: 900 mm
Pset_DoorCommon - IsExternal: no; Reference: SU-02
Name (Ühepoolsed:SU-02:...) | In | 01.Nimetus | 02.Materjal | 03.Kategooria / tüüp | 04.Avamõõdu geomeetria | 05.Asukoha info | 06.Soojusläbivus = 08.Veepidavus = 09.Õhuläbilaskvus = 10.Tulekindlus = 11.Vastupanu tulekoormusele = 13.Klaasingu erisused = 14.Päikesekiirgus tegur (g-väärtus) = 16.Liigendatus = 17.Sulused, lukustus = 19.Mudel või toote tunnus = 20.Tootja | 07.Helipidavus | 12.Klaaspakett | 15.Avanemine | 18.Viimistlus
323160 | 1 korrus | Siseuks | Puit | SU-02 | 900x2100 | Interior | - | 34 dB | karastatud klaas | Folding to Right | Tammespoon
498907 | uus 1 korrus | Siseuks | Puit | SU-02 | 900x2100 | Interior | - | 34 dB | karastatud klaas | Folding to Right | Tammespoon
900490 | uus 1 korrus | Siseuks | Puit | SU-02 | 900x2100 | Interior | - | 34 dB | karastatud klaas | Folding to Right | Tammespoon
900544 | uus 1 korrus | Siseuks | Puit | SU-02 | 900x2100 | Interior | - | 34 dB | karastatud klaas | Folding to Right | Tammespoon
934430 | uus 3 korrus | Siseuks | Puit | SU-02 | 900x2100 | Interior | - | 34 dB | karastatud klaas | Folding to Right | Tammespoon
1746923 | 4 korrus

# IfcDoor: SU-02, Ühepoolsed:SU-02:557840
In: 2 korrus
Type - OperationType: FOLDING_TO_LEFT; ParameterTakesPrecedence: no; Sizeable: no; Material: _Alumiiniumprofiil - must, __Uks_hele tamm, Glass
Type - Ühepoolsed:SU-02:557840 - PanelOperation: FOLDING
OverallHeight: 2100 mm; OverallWidth: 900 mm
Pset_DoorCommon - IsExternal: no; Reference: SU-02
AR_IFC_UKSED - 01.Nimetus: Siseuks; 02.Materjal: Puit; 03.Kategooria / tüüp: SU-02; 04.Avamõõdu geomeetria: 900x2100; 05.Asukoha info: Interior; 06.Soojusläbivus: -; 07.Helipidavus: 34 dB; 08.Veepidavus: -; 09.Õhuläbilaskvus: -; 10.Tulekindlus: -; 11.Vastupanu tulekoormusele: -; 12.Klaaspakett: karastatud klaas; 13.Klaasingu erisused: -; 14.Päikesekiirgus tegur (g-väärtus): -; 15.Avanemine: Folding to Right; 16.Liigendatus: -; 17.Sulused, lukustus: -; 18.Viimistlus: Tammespoon; 19.Mudel või toote tunnus: -; 20.Tootja: -

# IfcDoor: SU-02., Ühepoolsed:SU-02.:1316792
In: uus 1 korrus
Type - OperationType: FOLDING_TO_LEFT; ParameterTakesPrecedence: no; Sizeable: no; Material: _Alumiiniumprofiil - must, __Uks_hele tamm, Glass
Type - Ühepoolsed:SU-02.:1316792 - PanelOperation: FOLDING
OverallHeight: 2100 mm; OverallWidth: 900 mm
Pset_DoorCommon - IsExternal: no; Reference: SU-02.
AR_IFC_UKSED - 01.Nimetus: Siseuks; 02.Materjal: Puit; 03.Kategooria / tüüp: SU-02; 04.Avamõõdu geomeetria: 900x2100; 05.Asukoha info: Interior; 06.Soojusläbivus: -; 07.Helipidavus: 34 dB; 08.Veepidavus: -; 09.Õhuläbilaskvus: -; 10.Tulekindlus: -; 11.Vastupanu tulekoormusele: -; 12.Klaaspakett: karastatud klaas; 13.Klaasingu erisused: -; 14.Päikesekiirgus tegur (g-väärtus): -; 15.Avanemine: Folding to Left; 16.Liigendatus: -; 17.Sulused, lukustus: -; 18.Viimistlus: Tammespoon; 19.Mudel või toote tunnus: -; 20.Tootja: -

# IfcDoor: SU-02. (2)
Type - OperationType: FOLDING_TO_LEFT; ParameterTakesPrecedence: no; Sizeable: no; Material: _Alumiiniumprofiil - must, __Uks_hele tamm, Glass
Type - Ühepoolsed:SU-02.:239851 - PanelOperation: FOLDING
OverallHeight: 2100 mm; OverallWidth: 900 mm
Pset_DoorCommon - IsExternal: no; Reference: SU-02.
AR_IFC_UKSED - 01.Nimetus: Siseuks; 02.Materjal: Puit; 03.Kategooria / tüüp: SU-02; 04.Avamõõdu geomeetria: 900x2100; 05.Asukoha info: Interior; 06.Soojusläbivus: -; 07.Helipidavus: 34 dB; 08.Veepidavus: -; 09.Õhuläbilaskvus: -; 10.Tulekindlus: -; 11.Vastupanu tulekoormusele: -; 12.Klaaspakett: karastatud klaas; 13.Klaasingu erisused: -; 14.Päikesekiirgus tegur (g-väärtus): -; 15.Avanemine: Folding to Left; 16.Liigendatus: -; 17.Sulused, lukustus: -; 18.Viimistlus: Tammespoon; 19.Mudel või toote tunnus: -; 20.Tootja: -
Name (Ühepoolsed:SU-02.:...) | In
239851 | 4 korrus
1077138 | 1 korrus

# IfcDoor: SU-03, Ühepoolsed:SU-03:557605
In: 2 korrus
Type - OperationType: FOLDING_TO_LEFT; ParameterTakesPrecedence: no; Sizeable: no; Material: _Alumiiniumprofiil - must, __Uks_hele tamm, Glass
Type - Ühepoolsed:SU-03:557605 - PanelOperation: FOLDING
OverallHeight: 2100 mm; OverallWidth: 950 mm
Pset_DoorCommon - IsExternal: no; Reference: SU-03
AR_IFC_UKSED - 01.Nimetus: Siseuks; 02.Materjal: Puit; 03.Kategooria / tüüp: SU-03; 04.Avamõõdu geomeetria: 950x2100; 05.Asukoha info: Interior; 06.Soojusläbivus: -; 07.Helipidavus: 34 dB; 08.Veepidavus: -; 09.Õhuläbilaskvus: -; 10.Tulekindlus: -; 11.Vastupanu tulekoormusele: -; 12.Klaaspakett: karastatud klaas; 13.Klaasingu erisused: -; 14.Päikesekiirgus tegur (g-väärtus): -; 15.Avanemine: Folding to Right; 16.Liigendatus: -; 17.Sulused, lukustus: -; 18.Viimistlus: Tammespoon; 19.Mudel või toote tunnus: -; 20.Tootja: -

# IfcDoor: SU-03 (3)
In: 3 korrus
Type - OperationType: FOLDING_TO_LEFT; ParameterTakesPrecedence: no; Sizeable: no; Material: _Alumiiniumprofiil - must, __Uks_hele tamm, Glass
Type - Ühepoolsed:SU-03:571676 - PanelOperation: FOLDING
OverallHeight: 2100 mm; OverallWidth: 950 mm
Pset_DoorCommon - IsExternal: no; Reference: SU-03
AR_IFC_UKSED - 01.Nimetus: Siseuks; 02.Materjal: Puit; 03.Kategooria / tüüp: SU-03; 05.Asukoha info: Interior; 06.Soojusläbivus: -; 07.Helipidavus: 34 dB; 08.Veepidavus: -; 09.Õhuläbilaskvus: -; 10.Tulekindlus: -; 11.Vastupanu tulekoormusele: -; 12.Klaaspakett: karastatud klaas; 13.Klaasingu erisused: -; 14.Päikesekiirgus tegur (g-väärtus): -; 15.Avanemine: Folding to Right; 16.Liigendatus: -; 17.Sulused, lukustus: -; 18.Viimistlus: Tammespoon; 19.Mudel või toote tunnus: -; 20.Tootja: -
Name (Ühepoolsed:SU-03:...) | 04.Avamõõdu geomeetria
571676 | 1000x2100
571746 | 1000x2100
572865 | 950x2100

# IfcDoor: SU-03. (3)
In: 2 korrus
Type - OperationType: FOLDING_TO_LEFT; ParameterTakesPrecedence: no; Sizeable: no; Material: _Alumiiniumprofiil - must, __Uks_hele tamm, Glass
Type - Ühepoolsed:SU-03.:556845 - PanelOperation: FOLDING
OverallHeight: 2100 mm; OverallWidth: 950 mm
Pset_DoorCommon - IsExternal: no; Reference: SU-03.
AR_IFC_UKSED - 01.Nimetus: Siseuks; 02.Materjal: Puit; 03.Kategooria / tüüp: SU-03; 05.Asukoha info: Interior; 06.Soojusläbivus: -; 07.Helipidavus: 34 dB; 08.Veepidavus: -; 09.Õhuläbilaskvus: -; 10.Tulekindlus: -; 11.Vastupanu tulekoormusele: -; 12.Klaaspakett: karastatud klaas; 13.Klaasingu erisused: -; 14.Päikesekiirgus tegur (g-väärtus): -; 15.Avanemine: Folding to Left; 16.Liigendatus: -; 17.Sulused, lukustus: -; 18.Viimistlus: Tammespoon; 19.Mudel või toote tunnus: -; 20.Tootja: -
Name (Ühepoolsed:SU-03.:...) | 04.Avamõõdu geomeetria
556845 | 1000x2100
1119601 | 950x2100
1119721 | 950x2100

# IfcDoor: SU-03. (3)
In: 3 korrus
Type - OperationType: FOLDING_TO_LEFT; ParameterTakesPrecedence: no; Sizeable: no; Material: _Alumiiniumprofiil - must, __Uks_hele tamm, Glass
Type - Ühepoolsed:SU-03.:571561 - PanelOperation: FOLDING
OverallHeight: 2100 mm; OverallWidth: 950 mm
Pset_DoorCommon - IsExternal: no; Reference: SU-03.
AR_IFC_UKSED - 01.Nimetus: Siseuks; 02.Materjal: Puit; 03.Kategooria / tüüp: SU-03; 05.Asukoha info: Interior; 06.Soojusläbivus: -; 07.Helipidavus: 34 dB; 08.Veepidavus: -; 09.Õhuläbilaskvus: -; 10.Tulekindlus: -; 11.Vastupanu tulekoormusele: -; 12.Klaaspakett: karastatud klaas; 13.Klaasingu erisused: -; 14.Päikesekiirgus tegur (g-väärtus): -; 15.Avanemine: Folding to Left; 16.Liigendatus: -; 17.Sulused, lukustus: -; 18.Viimistlus: Tammespoon; 19.Mudel või toote tunnus: -; 20.Tootja: -
Name (Ühepoolsed:SU-03.:...) | 04.Avamõõdu geomeetria
571561 | 1000x2100
572231 | 950x2100
572708 | 950x2100

# IfcDoor: SU-04, Ühepoolsed:SU-04:325530
In: 1 korrus
Type - OperationType: FOLDING_TO_LEFT; ParameterTakesPrecedence: no; Sizeable: no; Material: _Alumiiniumprofiil - must, __Uks_hele tamm, Glass
Type - Ühepoolsed:SU-04:325530 - PanelOperation: FOLDING
OverallHeight: 2300 mm; OverallWidth: 1030 mm
Pset_DoorCommon - IsExternal: no; Reference: SU-04
AR_IFC_UKSED - 01.Nimetus: Siseuks; 02.Materjal: Puit; 03.Kategooria / tüüp: SU-04; 04.Avamõõdu geomeetria: 1030x2300; 05.Asukoha info: Interior; 06.Soojusläbivus: -; 07.Helipidavus: 34 dB; 08.Veepidavus: -; 09.Õhuläbilaskvus: -; 10.Tulekindlus: -; 11.Vastupanu tulekoormusele: -; 12.Klaaspakett: karastatud klaas; 13.Klaasingu erisused: -; 14.Päikesekiirgus tegur (g-väärtus): -; 15.Avanemine: Folding to Right; 16.Liigendatus: -; 17.Sulused, lukustus: -; 18.Viimistlus: Tammespoon; 19.Mudel või toote tunnus: -; 20.Tootja: -

# IfcDoor: SU-05, Ühepoolsed:SU-05:342177
In: 1 korrus
Type - OperationType: FOLDING_TO_LEFT; ParameterTakesPrecedence: no; Sizeable: no; Material: _Alumiiniumprofiil - must, __Uks_hele tamm
Type - Ühepoolsed:SU-05:342177 - PanelOperation: FOLDING
OverallHeight: 2100 mm; OverallWidth: 800 mm
Pset_DoorCommon - IsExternal: no; Reference: SU-05
AR_IFC_UKSED - 01.Nimetus: Siseuks; 02.Materjal: Puit; 03.Kategooria / tüüp: SU-05; 04.Avamõõdu geomeetria: 800x2100; 05.Asukoha info: Interior; 06.Soojusläbivus: -; 07.Helipidavus: -; 08.Veepidavus: -; 09.Õhuläbilaskvus: -; 10.Tulekindlus: -; 11.Vastupanu tulekoormusele: -; 12.Klaaspakett: -; 13.Klaasingu erisused: -; 14.Päikesekiirgus tegur (g-väärtus): -; 15.Avanemine: Folding to Right; 16.Liigendatus: -; 17.Sulused, lukustus: -; 18.Viimistlus: Tammespoon; 19.Mudel või toote tunnus: -; 20.Tootja: -

# IfcDoor: SU-05, Ühepoolsed:SU-05:342365
In: 1 korrus
Type - OperationType: FOLDING_TO_LEFT; ParameterTakesPrecedence: no; Sizeable: no; Material: _Alumiiniumprofiil - must, __Uks_hele tamm
Type - Ühepoolsed:SU-05:342365 - PanelOperation: FOLDING
OverallHeight: 2100 mm; OverallWidth: 800 mm
Pset_DoorCommon - IsExternal: no; Reference: SU-05
AR_IFC_UKSED - 01.Nimetus: Siseuks; 02.Materjal: Puit; 03.Kategooria / tüüp: SU-06; 04.Avamõõdu geomeetria: 900x2100; 05.Asukoha info: Interior; 06.Soojusläbivus: -; 07.Helipidavus: -; 08.Veepidavus: -; 09.Õhuläbilaskvus: -; 10.Tulekindlus: -; 11.Vastupanu tulekoormusele: -; 12.Klaaspakett: -; 13.Klaasingu erisused: -; 14.Päikesekiirgus tegur (g-väärtus): -; 15.Avanemine: Folding to Right; 16.Liigendatus: -; 17.Sulused, lukustus: -; 18.Viimistlus: Tammespoon; 19.Mudel või toote tunnus: -; 20.Tootja: -

# IfcDoor: SU-05 (6)
Type - OperationType: FOLDING_TO_LEFT; ParameterTakesPrecedence: no; Sizeable: no; Material: _Alumiiniumprofiil - must, __Uks_hele tamm
Type - Ühepoolsed:SU-05:519475 - PanelOperation: FOLDING
OverallHeight: 2100 mm; OverallWidth: 800 mm
Pset_DoorCommon - IsExternal: no; Reference: SU-05
AR_IFC_UKSED - 01.Nimetus: Siseuks; 02.Materjal: Puit; 03.Kategooria / tüüp: SU-05; 04.Avamõõdu geomeetria: 800x2100; 05.Asukoha info: Interior; 06.Soojusläbivus: -; 07.Helipidavus: -; 08.Veepidavus: -; 09.Õhuläbilaskvus: -; 10.Tulekindlus: -; 11.Vastupanu tulekoormusele: -; 12.Klaaspakett: -; 13.Klaasingu erisused: -; 14.Päikesekiirgus tegur (g-väärtus): -; 15.Avanemine: Folding to Right; 16.Liigendatus: -; 17.Sulused, lukustus: -; 18.Viimistlus: Tammespoon; 19.Mudel või toote tunnus: -; 20.Tootja: -
Name (Ühepoolsed:SU-05:...) | In
519475 | 2 korrus
519622 | 2 korrus
562879 | 3 korrus
562881 | 3 korrus
563011 | 4 korrus
563013 | 4 korrus

# IfcDoor: SU-05 (3)
Type - OperationType: FOLDING_TO_RIGHT; ParameterTakesPrecedence: no; Sizeable: no; Material: _Alumiiniumprofiil - must, __Uks_hele tamm
Type - Ühepoolsed:SU-05:900334 - PanelOperation: FOLDING
OverallHeight: 2100 mm; OverallWidth: 800 mm
Pset_DoorCommon - IsExternal: no; Reference: SU-05
AR_IFC_UKSED - 01.Nimetus: Siseuks; 02.Materjal: Puit; 03.Kategooria / tüüp: SU-05; 04.Avamõõdu geomeetria: 800x2100; 05.Asukoha info: Interior; 06.Soojusläbivus: -; 07.Helipidavus: -; 08.Veepidavus: -; 09.Õhuläbilaskvus: -; 10.Tulekindlus: -; 11.Vastupanu tulekoormusele: -; 12.Klaaspakett: -; 13.Klaasingu erisused: -; 14.Päikesekiirgus tegur (g-väärtus): -; 15.Avanemine: Folding to Left; 16.Liigendatus: -; 17.Sulused, lukustus: -; 18.Viimistlus: Tammespoon; 19.Mudel või toote tunnus: -; 20.Tootja: -
Name (Ühepoolsed:SU-05:...) | In
900334 | uus 1 korrus
1445577 | uus 2 korrus
1445593 | uus 3 korrus

# IfcDoor: SU-05. (2)
In: 1 korrus
Type - OperationType: FOLDING_TO_LEFT; ParameterTakesPrecedence: no; Sizeable: no; Material: _Alumiiniumprofiil - must, __Uks_hele tamm
Type - Ühepoolsed:SU-05.:327042 - PanelOperation: FOLDING
OverallHeight: 2100 mm; OverallWidth: 800 mm
Pset_DoorCommon - IsExternal: no; Reference: SU-05.
AR_IFC_UKSED - 01.Nimetus: Siseuks; 02.Materjal: Puit; 03.Kategooria / tüüp: SU-05; 04.Avamõõdu geomeetria: 800x2100; 05.Asukoha info: Interior; 06.Soojusläbivus: -; 07.Helipidavus: -; 08.Veepidavus: -; 09.Õhuläbilaskvus: -; 10.Tulekindlus: -; 11.Vastupanu tulekoormusele: -; 12.Klaaspakett: -; 13.Klaasingu erisused: -; 14.Päikesekiirgus tegur (g-väärtus): -; 15.Avanemine: Folding to Left; 16.Liigendatus: -; 17.Sulused, lukustus: -; 18.Viimistlus: Tammespoon; 19.Mudel või toote tunnus: -; 20.Tootja: -
Name (Ühepoolsed:SU-05.:...)
327042
341983

# IfcDoor: SU-05., Ühepoolsed:SU-05.:341906
In: 1 korrus
Type - OperationType: FOLDING_TO_LEFT; ParameterTakesPrecedence: no; Sizeable: no; Material: _Alumiiniumprofiil - must, __Uks_hele tamm
Type - Ühepoolsed:SU-05.:341906 - PanelOperation: FOLDING
OverallHeight: 2100 mm; OverallWidth: 800 mm
Pset_DoorCommon - IsExternal: no; Reference: SU-05.
AR_IFC_UKSED - 01.Nimetus: Siseuks; 02.Materjal: Puit; 03.Kategooria / tüüp: SU-06; 04.Avamõõdu geomeetria: 900x2100; 05.Asukoha info: Interior; 06.Soojusläbivus: -; 07.Helipidavus: -; 08.Veepidavus: -; 09.Õhuläbilaskvus: -; 10.Tulekindlus: -; 11.Vastupanu tulekoormusele: -; 12.Klaaspakett: -; 13.Klaasingu erisused: -; 14.Päikesekiirgus tegur (g-väärtus): -; 15.Avanemine: Folding to Left; 16.Liigendatus: -; 17.Sulused, lukustus: -; 18.Viimistlus: Tammespoon; 19.Mudel või toote tunnus: -; 20.Tootja: -

# IfcDoor: SU-05., Ühepoolsed:SU-05.:342141
In: 1 korrus
Type - OperationType: FOLDING_TO_LEFT; ParameterTakesPrecedence: no; Sizeable: no; Material: _Alumiiniumprofiil - must, __Uks_hele tamm
Type - Ühepoolsed:SU-05.:342141 - PanelOperation: FOLDING
OverallHeight: 2100 mm; OverallWidth: 800 mm
Pset_DoorCommon - IsExternal: no; Reference: SU-05.
AR_IFC_UKSED - 01.Nimetus: Siseuks; 02.Materjal: Puit; 03.Kategooria / tüüp: SU-05; 04.Avamõõdu geomeetria: 800x2100; 05.Asukoha info: Interior; 06.Soojusläbivus: -; 07.Helipidavus: -; 08.Veepidavus: -; 09.Õhuläbilaskvus: -; 10.Tulekindlus: -; 11.Vastupanu tulekoormusele: -; 12.Klaaspakett: -; 13.Klaasingu erisused: -; 14.Päikesekiirgus tegur (g-väärtus): -; 15.Avanemine: Folding to Left; 16.Liigendatus: -; 17.Sulused, lukustus: -; 18.Viimistlus: Tammespoon; 19.Mudel või toote tunnus: -; 20.Tootja: -

# IfcDoor: SU-06 (3)
Type - OperationType: FOLDING_TO_LEFT; ParameterTakesPrecedence: no; Sizeable: no; Material: _Alumiiniumprofiil - must, __Uks_hele tamm
Type - Ühepoolsed:SU-06:499027 - PanelOperation: FOLDING
OverallHeight: 2100 mm; OverallWidth: 900 mm
Pset_DoorCommon - IsExternal: no; Reference: SU-06
AR_IFC_UKSED - 01.Nimetus: Siseuks; 02.Materjal: Puit; 03.Kategooria / tüüp: SU-06; 04.Avamõõdu geomeetria: 900x2100; 05.Asukoha info: Interior; 06.Soojusläbivus: -; 07.Helipidavus: -; 08.Veepidavus: -; 09.Õhuläbilaskvus: -; 10.Tulekindlus: -; 11.Vastupanu tulekoormusele: -; 12.Klaaspakett: -; 13.Klaasingu erisused: -; 14.Päikesekiirgus tegur (g-väärtus): -; 15.Avanemine: Folding to Right; 16.Liigendatus: -; 17.Sulused, lukustus: -; 18.Viimistlus: Tammespoon; 19.Mudel või toote tunnus: -; 20.Tootja: -
Name (Ühepoolsed:SU-06:...) | In
499027 | uus 1 korrus
499061 | uus 1 korrus
1317124 | 3 korrus

# IfcDoor: SU-06., Ühepoolsed:SU-06.:327227
In: 1 korrus
Type - OperationType: FOLDING_TO_LEFT; ParameterTakesPrecedence: no; Sizeable: no; Material: _Alumiiniumprofiil - must, __Uks_hele tamm
Type - Ühepoolsed:SU-06.:327227 - PanelOperation: FOLDING
OverallHeight: 2100 mm; OverallWidth: 900 mm
Pset_DoorCommon - IsExternal: no; Reference: SU-06.
AR_IFC_UKSED - 01.Nimetus: Siseuks; 02.Materjal: Puit; 03.Kategooria / tüüp: SU-06; 04.Avamõõdu geomeetria: 900x2100; 05.Asukoha info: Interior; 06.Soojusläbivus: -; 07.Helipidavus: -; 08.Veepidavus: -; 09.Õhuläbilaskvus: -; 10.Tulekindlus: -; 11.Vastupanu tulekoormusele: -; 12.Klaaspakett: -; 13.Klaasingu erisused: -; 14.Päikesekiirgus tegur (g-väärtus): -; 15.Avanemine: Folding to Left; 16.Liigendatus: -; 17.Sulused, lukustus: -; 18.Viimistlus: Tammespoon; 19.Mudel või toote tunnus: -; 20.Tootja: -

# IfcDoor: SU-07, Ühepoolsed:SU-07:341632
In: 1 korrus
Type - OperationType: FOLDING_TO_RIGHT; ParameterTakesPrecedence: no; Sizeable: no; Material: _Alumiiniumprofiil - must, __Uks_hele tamm
Type - Ühepoolsed:SU-07:341632 - PanelOperation: FOLDING
OverallHeight: 2100 mm; OverallWidth: 1000 mm
Pset_DoorCommon - IsExternal: no; Reference: SU-07
AR_IFC_UKSED - 01.Nimetus: Siseuks; 02.Materjal: Puit; 03.Kategooria / tüüp: SU-07; 04.Avamõõdu geomeetria: 1000x2100; 05.Asukoha info: Interior; 06.Soojusläbivus: -; 07.Helipidavus: -; 08.Veepidavus: -; 09.Õhuläbilaskvus: -; 10.Tulekindlus: -; 11.Vastupanu tulekoormusele: -; 12.Klaaspakett: -; 13.Klaasingu erisused: -; 14.Päikesekiirgus tegur (g-väärtus): -; 15.Avanemine: Folding to Left; 16.Liigendatus: -; 17.Sulused, lukustus: wc uste komplekt erivajadustega inimestele; 18.Viimistlus: Tammespoon; 19.Mudel või toote tunnus: -; 20.Tootja: -

# IfcDoor: SU-08 (2)
Type - OperationType: FOLDING_TO_LEFT; ParameterTakesPrecedence: no; Sizeable: no; Material: _Alumiiniumprofiil - must, __Uks_hele tamm, Glass
Type - Ühepoolsed:SU-08:342066 - PanelOperation: FOLDING
OverallHeight: 2100 mm; OverallWidth: 800 mm
Pset_DoorCommon - IsExternal: no; Reference: SU-08
AR_IFC_UKSED - 01.Nimetus: Siseuks; 02.Materjal: Klaas; 03.Kategooria / tüüp: SU-08; 04.Avamõõdu geomeetria: 800x2100; 05.Asukoha info: Interior; 06.Soojusläbivus: -; 07.Helipidavus: -; 08.Veepidavus: 8A; 09.Õhuläbilaskvus: -; 10.Tulekindlus: -; 11.Vastupanu tulekoormusele: -; 12.Klaaspakett: karastatud klaas; 13.Klaasingu erisused: -; 14.Päikesekiirgus tegur (g-väärtus): -; 15.Avanemine: Folding to Left; 16.Liigendatus: -; 17.Sulused, lukustus: -; 18.Viimistlus: Klaas; 19.Mudel või toote tunnus: -; 20.Tootja: -
Name (Ühepoolsed:SU-08:...) | In
342066 | 1 korrus
499100 | uus 1 korrus

# IfcDoor: SU-08., Ühepoolsed:SU-08.:342205
In: 1 korrus
Type - OperationType: FOLDING_TO_LEFT; ParameterTakesPrecedence: no; Sizeable: no; Material: _Alumiiniumprofiil - must, __Uks_hele tamm, Glass
Type - Ühepoolsed:SU-08.:342205 - PanelOperation: FOLDING
OverallHeight: 2100 mm; OverallWidth: 800 mm
Pset_DoorCommon - IsExternal: no; Reference: SU-08.
AR_IFC_UKSED - 01.Nimetus: Siseuks; 02.Materjal: Klaas; 03.Kategooria / tüüp: SU-08; 04.Avamõõdu geomeetria: 800x2100; 05.Asukoha info: Interior; 06.Soojusläbivus: -; 07.Helipidavus: -; 08.Veepidavus: 8A; 09.Õhuläbilaskvus: -; 10.Tulekindlus: -; 11.Vastupanu tulekoormusele: -; 12.Klaaspakett: karastatud klaas; 13.Klaasingu erisused: -; 14.Päikesekiirgus tegur (g-väärtus): -; 15.Avanemine: Folding to Right; 16.Liigendatus: -; 17.Sulused, lukustus: -; 18.Viimistlus: Klaas; 19.Mudel või toote tunnus: -; 20.Tootja: -

# IfcDoor: SU-09, Ühepoolsed:SU-09:1119743
In: 2 korrus
Type - OperationType: FOLDING_TO_LEFT; ParameterTakesPrecedence: no; Sizeable: no; Material: _Alumiiniumprofiil - must, __Uks_hele tamm
Type - Ühepoolsed:SU-09:1119743 - PanelOperation: FOLDING
OverallHeight: 2100 mm; OverallWidth: 1000 mm
Pset_DoorCommon - IsExternal: no; Reference: SU-09
AR_IFC_UKSED - 01.Nimetus: Siseuks; 02.Materjal: Puit; 03.Kategooria / tüüp: SU-09; 04.Avamõõdu geomeetria: 1000x2100; 05.Asukoha info: Interior; 06.Soojusläbivus: -; 07.Helipidavus: -; 08.Veepidavus: -; 09.Õhuläbilaskvus: -; 10.Tulekindlus: EI-30; 11.Vastupanu tulekoormusele: -; 12.Klaaspakett: -; 13.Klaasingu erisused: -; 15.Avanemine: Folding to Right; 16.Liigendatus: -; 17.Sulused, lukustus: ASSA ABLOY liugveovarrega sulgur, sulgemisjärjesti; 18.Viimistlus: Tammespoon; 19.Mudel või toote tunnus: -; 20.Tootja: -

# IfcDoor: SU-10, Ühepoolsed:SU-10:569781
In: 3 korrus
Type - OperationType: FOLDING_TO_LEFT; ParameterTakesPrecedence: no; Sizeable: no; Material: _Alumiiniumprofiil - must, __Uks_hele tamm
Type - Ühepoolsed:SU-10:569781 - PanelOperation: FOLDING
OverallHeight: 2100 mm; OverallWidth: 900 mm
Pset_DoorCommon - IsExternal: no; Reference: SU-10
AR_IFC_UKSED - 01.Nimetus: Siseuks; 02.Materjal: Metall; 03.Kategooria / tüüp: SU-10; 04.Avamõõdu geomeetria: 900x2100; 05.Asukoha info: Interior; 06.Soojusläbivus: -; 07.Helipidavus: -; 08.Veepidavus: -; 09.Õhuläbilaskvus: -; 10.Tulekindlus: EI-30; 11.Vastupanu tulekoormusele: -; 12.Klaaspakett: -; 13.Klaasingu erisused: -; 14.Päikesekiirgus tegur (g-väärtus): -; 15.Avanemine: Folding to Left; 16.Liigendatus: -; 17.Sulused, lukustus: ASSA ABLOY liugveovarrega sulgur, sulgemisjärjesti; 18.Viimistlus: RAL8019; 19.Mudel või toote tunnus: -; 20.Tootja: -

# IfcDoor: SU-10 (2)
In: 1 korrus
Type - OperationType: FOLDING_TO_RIGHT; ParameterTakesPrecedence: no; Sizeable: no; Material: _Alumiiniumprofiil - must, __Uks_hele tamm
Type - Ühepoolsed:SU-10:239116 - PanelOperation: FOLDING
OverallHeight: 2100 mm; OverallWidth: 900 mm
Pset_DoorCommon - IsExternal: no; Reference: SU-10
AR_IFC_UKSED - 01.Nimetus: Siseuks; 02.Materjal: Metall; 03.Kategooria / tüüp: SU-10; 04.Avamõõdu geomeetria: 900x2100; 05.Asukoha info: Interior; 06.Soojusläbivus: -; 07.Helipidavus: -; 08.Veepidavus: -; 09.Õhuläbilaskvus: -; 10.Tulekindlus: EI-30; 11.Vastupanu tulekoormusele: -; 12.Klaaspakett: -; 13.Klaasingu erisused: -; 14.Päikesekiirgus tegur (g-väärtus): -; 15.Avanemine: Folding to Left; 16.Liigendatus: -; 17.Sulused, lukustus: ASSA ABLOY liugveovarrega sulgur, sulgemisjärjesti; 18.Viimistlus: RAL8019; 19.Mudel või toote tunnus: -; 20.Tootja: -
Name (Ühepoolsed:SU-10:...)
239116
1220456

# IfcDoor: SU-11 (2)
Type - OperationType: FOLDING_TO_RIGHT; ParameterTakesPrecedence: no; Sizeable: no; Material: _Alumiiniumprofiil - must, __Uks_hele tamm, EP Tavallinen lasi
Type - Kahepoolsed:SU-11:1247419 - PanelOperation: FOLDING
OverallHeight: 2100 mm; OverallWidth: 1300 mm
Pset_DoorCommon - IsExternal: no; Reference: SU-11
Name (Kahepoolsed:SU-11:...) | In
1247419 | uus 2 korrus
1247581 | uus 3 korrus

# IfcDoor: SU-11, Kahepoolsed:SU-11:239467
In: 2 korrus
Type - OperationType: FOLDING_TO_RIGHT; ParameterTakesPrecedence: no; Sizeable: no; Material: _Alumiiniumprofiil - must, __Uks_hele tamm, EP Tavallinen lasi
Type - Kahepoolsed:SU-11:239467 - PanelOperation: FOLDING
OverallHeight: 2100 mm; OverallWidth: 1300 mm
Pset_DoorCommon - IsExternal: no; Reference: SU-11
AR_IFC_UKSED - 01.Nimetus: Siseuks; 02.Materjal: Puit; 03.Kategooria / tüüp: SU-11; 04.Avamõõdu geomeetria: 1300x2100; 05.Asukoha info: Interior; 06.Soojusläbivus: -; 07.Helipidavus: 30 dB; 08.Veepidavus: -; 09.Õhuläbilaskvus: -; 10.Tulekindlus: EI-30; 11.Vastupanu tulekoormusele: -; 12.Klaaspakett: karastatud klaas; 13.Klaasingu erisused: tuletõkke klaas; 14.Päikesekiirgus tegur (g-väärtus): -; 15.Avanemine: Folding to Right; 16.Liigendatus: kahepoolne; 17.Sulused, lukustus: ASSA ABLOY liugveovarrega sulgur, sulgemisjärjesti; 18.Viimistlus: Tammespoon; 19.Mudel või toote tunnus: -; 20.Tootja: -

# IfcDoor: SU-11 (3)
Type - OperationType: FOLDING_TO_RIGHT; ParameterTakesPrecedence: no; Sizeable: no; Material: _Alumiiniumprofiil - must, __Uks_hele tamm, EP Tavallinen lasi
Type - Kahepoolsed:SU-11:239619 - PanelOperation: FOLDING
OverallHeight: 2100 mm; OverallWidth: 1300 mm
Pset_DoorCommon - IsExternal: no; Reference: SU-11
AR_IFC_UKSED - 01.Nimetus: Siseuks; 02.Materjal: Puit; 03.Kategooria / tüüp: SU-11; 04.Avamõõdu geomeetria: 1300x2100; 05.Asukoha info: Interior; 06.Soojusläbivus: -; 07.Helipidavus: 30 dB; 08.Veepidavus: -; 09.Õhuläbilaskvus: -; 10.Tulekindlus: EI-30; 11.Vastupanu tulekoormusele: -; 12.Klaaspakett: karastatud klaas; 13.Klaasingu erisused: tuletõkke klaas; 14.Päikesekiirgus tegur (g-väärtus): -; 15.Avanemine: Folding to Right; 16.Liigendatus: kahepoolne; 17.Sulused, lukustus: ASSA ABLOY liugveovarrega sulgur, sulgemisjärjesti; 18.Viimistlus: Tammespoon; 19.Mudel või toote tunnus: -; 20.Tootja: -
Name (Kahepoolsed:SU-11:...) | In
239619 | 3 korrus
239854 | 4 korrus
1244838 | 1 korrus

# IfcDoor: SU-12, Kahepoolsed:SU-12:239321
In: 1 korrus
Type - OperationType: FOLDING_TO_RIGHT; ParameterTakesPrecedence: no; Sizeable: no; Material: _Alumiiniumprofiil - must, __Uks_hele tamm, EP Tavallinen lasi
Type - Kahepoolsed:SU-12:239321 - PanelOperation: FOLDING
OverallHeight: 2100 mm; OverallWidth: 1300 mm
Pset_DoorCommon - IsExternal: no; Reference: SU-12
AR_IFC_UKSED - 01.Nimetus: Siseuks; 02.Materjal: Puit; 03.Kategooria / tüüp: SU-12; 04.Avamõõdu geomeetria: 1200x2100; 05.Asukoha info: Interior; 06.Soojusläbivus: -; 07.Helipidavus: 30 dB; 08.Veepidavus: -; 09.Õhuläbilaskvus: -; 10.Tulekindlus: -; 11.Vastupanu tulekoormusele: -; 12.Klaaspakett: karastatud klaas; 13.Klaasingu erisused: -; 14.Päikesekiirgus tegur (g-väärtus): -; 15.Avanemine: -; 16.Liigendatus: kahepoolne; 17.Sulused, lukustus: ASSA ABLOY liugveovarrega sulgur; 18.Viimistlus: Tammespoon; 19.Mudel või toote tunnus: -; 20.Tootja: -

# IfcDoor: SU-12., Kahepoolsed:SU-12.:239103
In: 1 korrus
Type - OperationType: FOLDING_TO_RIGHT; ParameterTakesPrecedence: no; Sizeable: no; Material: _Alumiiniumprofiil - must, __Uks_hele tamm, EP Tavallinen lasi
Type - Kahepoolsed:SU-12.:239103 - PanelOperation: FOLDING
OverallHeight: 2100 mm; OverallWidth: 1300 mm
Pset_DoorCommon - IsExternal: no; Reference: SU-12.
AR_IFC_UKSED - 01.Nimetus: Siseuks; 02.Materjal: Puit; 03.Kategooria / tüüp: SU-12; 04.Avamõõdu geomeetria: 1200x2100; 05.Asukoha info: Interior; 06.Soojusläbivus: -; 07.Helipidavus: 30 dB; 08.Veepidavus: -; 09.Õhuläbilaskvus: -; 10.Tulekindlus: -; 11.Vastupanu tulekoormusele: -; 12.Klaaspakett: karastatud klaas; 13.Klaasingu erisused: -; 14.Päikesekiirgus tegur (g-väärtus): -; 15.Avanemine: -; 16.Liigendatus: kahepoolne; 17.Sulused, lukustus: ASSA ABLOY liugveovarrega sulgur; 18.Viimistlus: Tammespoon; 19.Mudel või toote tunnus: -; 20.Tootja: -

# IfcDoor: SU-13, Kahepoolsed:SU-13:497043
In: uus 1 korrus
Type - OperationType: FOLDING_TO_RIGHT; ParameterTakesPrecedence: no; Sizeable: no; Material: _Alumiiniumprofiil - must, __Uks_hele tamm, EP Tavallinen lasi
Type - Kahepoolsed:SU-13:497043 - PanelOperation: FOLDING
OverallHeight: 2200 mm; OverallWidth: 1500 mm
Pset_DoorCommon - IsExternal: no; Reference: SU-13
AR_IFC_UKSED - 01.Nimetus: Siseuks; 02.Materjal: Puit; 03.Kategooria / tüüp: SU-13; 04.Avamõõdu geomeetria: 1500x2200; 05.Asukoha info: Interior; 06.Soojusläbivus: -; 07.Helipidavus: 30 dB; 08.Veepidavus: -; 09.Õhuläbilaskvus: -; 10.Tulekindlus: EI-30; 11.Vastupanu tulekoormusele: -; 12.Klaaspakett: karastatud klaas; 13.Klaasingu erisused: tuletõkke klaas; 14.Päikesekiirgus tegur (g-väärtus): -; 15.Avanemine: Folding to Right; 16.Liigendatus: kahepoolne; 17.Sulused, lukustus: ASSA ABLOY liugveovarrega sulgur, sulgemisjärjesti; 18.Viimistlus: Tammespoon; 19.Mudel või toote tunnus: -; 20.Tootja: -

# IfcDoor: SU-14, Kahepoolsed:SU-14:488211
In: 1 korrus
Type - OperationType: FOLDING_TO_RIGHT; ParameterTakesPrecedence: no; Sizeable: no; Material: _Alumiiniumprofiil - must, __Uks_hele tamm, EP Tavallinen lasi
Type - Kahepoolsed:SU-14:488211 - PanelOperation: FOLDING
OverallHeight: 2200 mm; OverallWidth: 1500 mm
Pset_DoorCommon - IsExternal: no; Reference: SU-14
AR_IFC_UKSED - 01.Nimetus: Siseuks; 02.Materjal: Puit; 03.Kategooria / tüüp: SU-14; 04.Avamõõdu geomeetria: 1500x2200; 05.Asukoha info: Interior; 06.Soojusläbivus: -; 07.Helipidavus: 30 dB; 08.Veepidavus: -; 09.Õhuläbilaskvus: -; 10.Tulekindlus: -; 11.Vastupanu tulekoormusele: -; 12.Klaaspakett: karastatud klaas; 13.Klaasingu erisused: -; 14.Päikesekiirgus tegur (g-väärtus): -; 15.Avanemine: Folding to Left; 16.Liigendatus: kahepoolne; 17.Sulused, lukustus: ASSA ABLOY liugveovarrega sulgur, sulgemisjärjesti; 18.Viimistlus: Tammespoon; 19.Mudel või toote tunnus: -; 20.Tootja: -

# IfcDoor: SU-14, Kahepoolsed:SU-14:569276
In: 3 korrus
Type - OperationType: FOLDING_TO_RIGHT; ParameterTakesPrecedence: no; Sizeable: no; Material: _Alumiiniumprofiil - must, __Uks_hele tamm, EP Tavallinen lasi
Type - Kahepoolsed:SU-14:569276 - PanelOperation: FOLDING
OverallHeight: 2200 mm; OverallWidth: 1500 mm
Pset_DoorCommon - IsExternal: no; Reference: SU-14
AR_IFC_UKSED - 01.Nimetus: Siseuks; 02.Materjal: Puit; 03.Kategooria / tüüp: SU-14; 04.Avamõõdu geomeetria: 1500x2200; 05.Asukoha info: Interior; 06.Soojusläbivus: -; 07.Helipidavus: 30 dB; 08.Veepidavus: -; 09.Õhuläbilaskvus: -; 10.Tulekindlus: -; 11.Vastupanu tulekoormusele: -; 12.Klaaspakett: karastatud klaas; 13.Klaasingu erisused: -; 14.Päikesekiirgus tegur (g-väärtus): -; 15.Avanemine: Folding to Left; 16.Liigendatus: kahepoolne; 17.Sulused, lukustus: ASSA ABLOY liugveovarrega sulgur, sulgemisjärjesti; 18.Viimistlus: Tammespoon; 19.Mudel või toote tunnus: -; 20.Tootja: -

# IfcDoor: SU-14. (2)
Type - OperationType: FOLDING_TO_RIGHT; ParameterTakesPrecedence: no; Sizeable: no; Material: _Alumiiniumprofiil - must, __Uks_hele tamm, EP Tavallinen lasi
Type - Kahepoolsed:SU-14.:922316 - PanelOperation: FOLDING
OverallHeight: 2200 mm; OverallWidth: 1500 mm
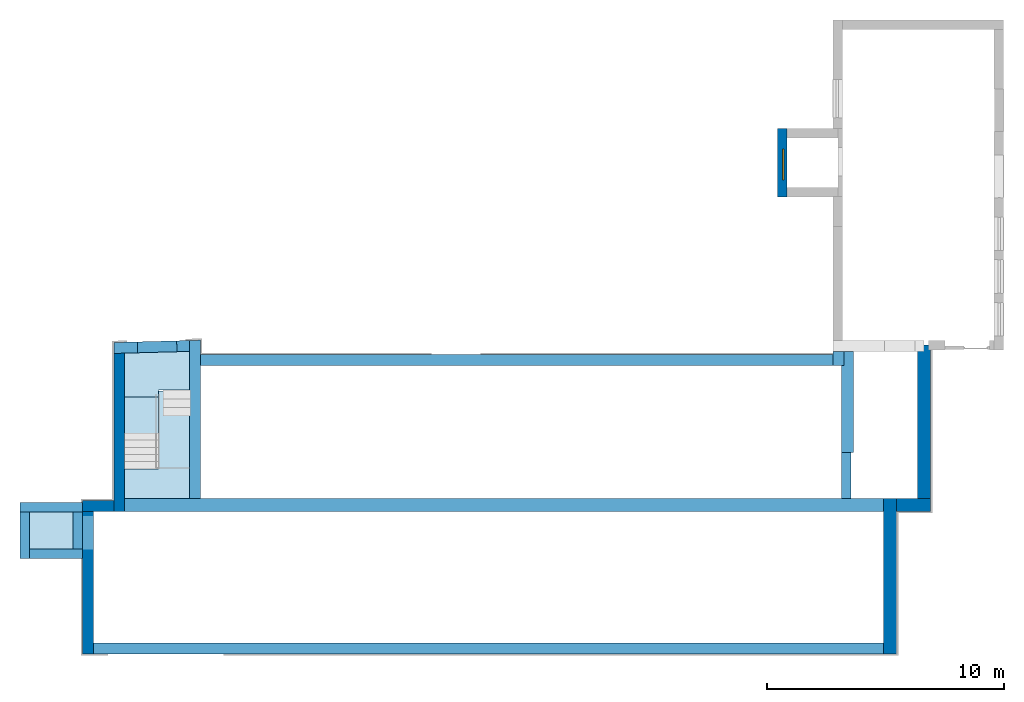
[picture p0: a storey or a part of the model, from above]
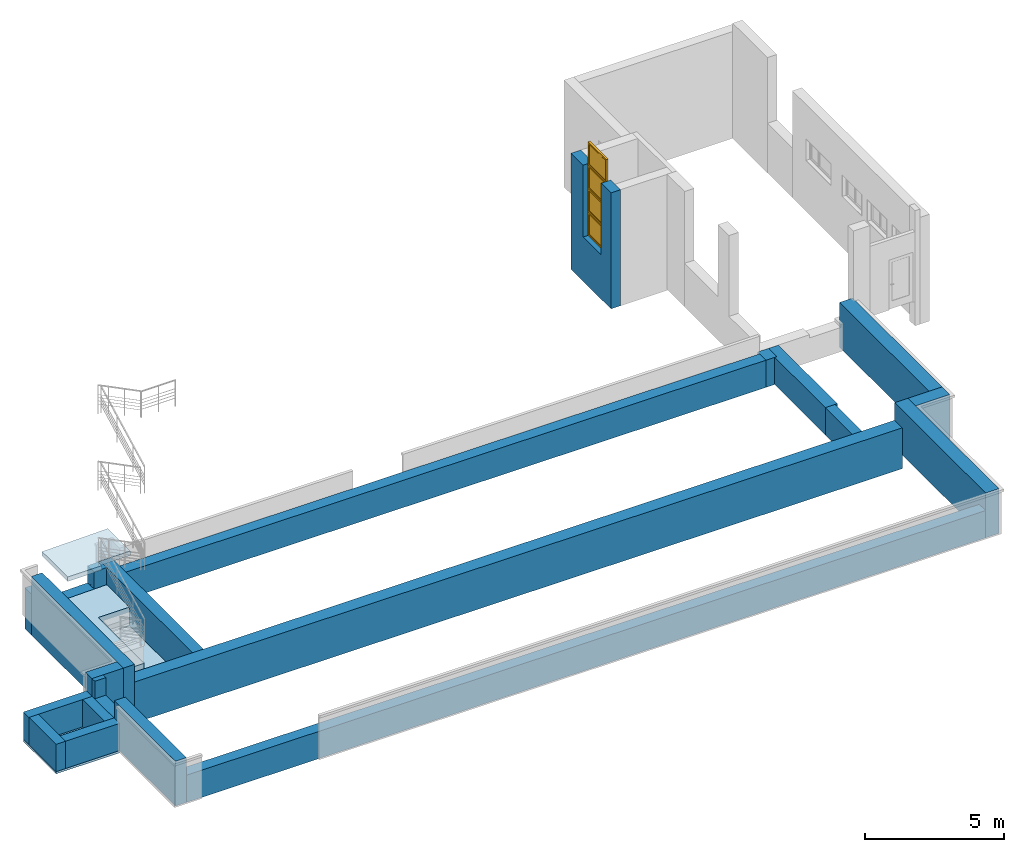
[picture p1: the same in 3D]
Properties of the parts of a building model (IFC2X3), part 2 of 5

# IfcDoor: SU-14. (2)
Pset_DoorCommon - IsExternal: no; Reference: SU-14.
AR_IFC_UKSED - 01.Nimetus: Siseuks; 02.Materjal: Puit; 03.Kategooria / tüüp: SU-14; 04.Avamõõdu geomeetria: 1500x2200; 05.Asukoha info: Interior; 06.Soojusläbivus: -; 07.Helipidavus: 30 dB; 08.Veepidavus: -; 09.Õhuläbilaskvus: -; 10.Tulekindlus: -; 11.Vastupanu tulekoormusele: -; 12.Klaaspakett: karastatud klaas; 13.Klaasingu erisused: -; 14.Päikesekiirgus tegur (g-väärtus): -; 15.Avanemine: Folding to Right; 16.Liigendatus: kahepoolne; 17.Sulused, lukustus: ASSA ABLOY liugveovarrega sulgur, sulgemisjärjesti; 18.Viimistlus: Tammespoon; 19.Mudel või toote tunnus: -; 20.Tootja: -
Name (Kahepoolsed:SU-14.:...) | In
922316 | uus 2 korrus
933230 | uus 3 korrus

# IfcDoor: SU-15, Ühepoolsed:SU-15:239323
In: 1 korrus
Type - OperationType: FOLDING_TO_LEFT; ParameterTakesPrecedence: no; Sizeable: no; Material: _Alumiiniumprofiil - must, Steel/Aluminium
Type - Ühepoolsed:SU-15:239323 - PanelOperation: FOLDING
OverallHeight: 1970 mm; OverallWidth: 750 mm
Pset_DoorCommon - IsExternal: no; Reference: SU-15
AR_IFC_UKSED - 01.Nimetus: Siseuks; 02.Materjal: Metall; 03.Kategooria / tüüp: SU-15; 04.Avamõõdu geomeetria: 750x1970; 05.Asukoha info: Interior; 06.Soojusläbivus: -; 07.Helipidavus: -; 08.Veepidavus: -; 09.Õhuläbilaskvus: -; 10.Tulekindlus: -; 11.Vastupanu tulekoormusele: -; 12.Klaaspakett: -; 13.Klaasingu erisused: -; 14.Päikesekiirgus tegur (g-väärtus): -; 15.Avanemine: Folding to Left; 16.Liigendatus: -; 17.Sulused, lukustus: ASSA ABLOY liugveovarrega sulgur, sulgemisjärjesti; 18.Viimistlus: RAL8019; 19.Mudel või toote tunnus: -; 20.Tootja: -

# IfcDoor: SU-1500_aken (3)
Type - OperationType: SINGLE_SWING_RIGHT; ParameterTakesPrecedence: no; Sizeable: no; Material: __Uks_hele tamm, EP Tavallinen lasi
Type - Aken ukse kohal:SU-1500_aken:1243665 - PanelOperation: SWINGING
OverallHeight: 2200 mm; OverallWidth: 1000 mm
Pset_DoorCommon - IsExternal: no; Reference: SU-1500_aken
AR_IFC_UKSED - 01.Nimetus: Siseuks; 02.Materjal: Puit; 03.Kategooria / tüüp: SU-17; 04.Avamõõdu geomeetria: 2350x2740; 05.Asukoha info: Interior; 06.Soojusläbivus: -; 07.Helipidavus: 30 dB; 08.Veepidavus: -; 09.Õhuläbilaskvus: -; 10.Tulekindlus: EI-30; 11.Vastupanu tulekoormusele: -; 12.Klaaspakett: karastatud klaas; 13.Klaasingu erisused: tuletõkke klaas; 14.Päikesekiirgus tegur (g-väärtus): -; 15.Avanemine: -; 16.Liigendatus: -; 17.Sulused, lukustus: -; 18.Viimistlus: Tammespoon; 19.Mudel või toote tunnus: -; 20.Tootja: -
Name (Aken ukse kohal:SU-1500_aken:...) | In
1243665 | 2 korrus
1421921 | 3 korrus
1421983 | 4 korrus

# IfcDoor: SU-1500_aken 2, Aken ukse kohal:SU-1500_aken 2:1663439
In: 1 korrus
Type - OperationType: SINGLE_SWING_LEFT; ParameterTakesPrecedence: no; Sizeable: no; Material: __Uks_hele tamm, EP Tavallinen lasi
Type - Aken ukse kohal:SU-1500_aken 2:1663439 - PanelOperation: SWINGING
OverallHeight: 2200 mm; OverallWidth: 850 mm
Pset_DoorCommon - IsExternal: no; Reference: SU-1500_aken 2
AR_IFC_UKSED - 01.Nimetus: Siseuks; 02.Materjal: Puit; 03.Kategooria / tüüp: SU-16; 04.Avamõõdu geomeetria: 850x2200; 05.Asukoha info: Interior; 06.Soojusläbivus: -; 07.Helipidavus: 30 dB; 08.Veepidavus: -; 09.Õhuläbilaskvus: -; 10.Tulekindlus: EI-30; 11.Vastupanu tulekoormusele: -; 12.Klaaspakett: karastatud klaas; 13.Klaasingu erisused: tuletõkke klaas; 14.Päikesekiirgus tegur (g-väärtus): -; 15.Avanemine: -; 16.Liigendatus: -; 17.Sulused, lukustus: -; 18.Viimistlus: Tammespoon; 19.Mudel või toote tunnus: -; 20.Tootja: -

# IfcDoor: SU-16, Kahepoolsed:SU-16:1243720
In: 1 korrus
Type - OperationType: FOLDING_TO_RIGHT; ParameterTakesPrecedence: no; Sizeable: no; Material: _Alumiiniumprofiil - must, __Uks_hele tamm, EP Tavallinen lasi
Type - Kahepoolsed:SU-16:1243720 - PanelOperation: FOLDING
OverallHeight: 2200 mm; OverallWidth: 1500 mm
Pset_DoorCommon - IsExternal: no; Reference: SU-16
AR_IFC_UKSED - 01.Nimetus: Siseuks; 02.Materjal: Puit; 03.Kategooria / tüüp: SU-16; 04.Avamõõdu geomeetria: 2350x2740; 05.Asukoha info: Interior; 06.Soojusläbivus: -; 07.Helipidavus: 30 dB; 08.Veepidavus: -; 09.Õhuläbilaskvus: -; 10.Tulekindlus: EI-30; 11.Vastupanu tulekoormusele: -; 12.Klaaspakett: karastatud klaas; 13.Klaasingu erisused: tuletõkke klaas; 14.Päikesekiirgus tegur (g-väärtus): -; 15.Avanemine: Folding to Right; 16.Liigendatus: kahepoolne; 17.Sulused, lukustus: ASSA ABLOY liugveovarrega sulgur, sulgemisjärjesti; 18.Viimistlus: Tammespoon; 19.Mudel või toote tunnus: -; 20.Tootja: -

# IfcDoor: SU-17 (3)
Type - OperationType: FOLDING_TO_RIGHT; ParameterTakesPrecedence: no; Sizeable: no; Material: _Alumiiniumprofiil - must, __Uks_hele tamm, EP Tavallinen lasi
Type - Kahepoolsed:SU-17:1243666 - PanelOperation: FOLDING
OverallHeight: 2200 mm; OverallWidth: 1500 mm
Pset_DoorCommon - IsExternal: no; Reference: SU-17
AR_IFC_UKSED - 01.Nimetus: Siseuks; 02.Materjal: Puit; 03.Kategooria / tüüp: SU-17; 04.Avamõõdu geomeetria: 2500x2740; 05.Asukoha info: Interior; 06.Soojusläbivus: -; 07.Helipidavus: 30 dB; 08.Veepidavus: -; 09.Õhuläbilaskvus: -; 10.Tulekindlus: EI-30; 11.Vastupanu tulekoormusele: -; 12.Klaaspakett: karastatud klaas; 13.Klaasingu erisused: tuletõkke klaas; 14.Päikesekiirgus tegur (g-väärtus): -; 15.Avanemine: Folding to Right; 16.Liigendatus: kahepoolne; 17.Sulused, lukustus: ASSA ABLOY liugveovarrega sulgur, sulgemisjärjesti; 18.Viimistlus: Tammespoon; 19.Mudel või toote tunnus: -; 20.Tootja: -
Name (Kahepoolsed:SU-17:...) | In
1243666 | 2 korrus
1421922 | 3 korrus
1421984 | 4 korrus

# IfcDoor: SU-18 (2)
In: 1 korrus
Type - OperationType: FOLDING_TO_LEFT; ParameterTakesPrecedence: no; Sizeable: no; Material: Door Handle - Aluminium, __Uks_hele tamm
Type - Lükanduks:SU-18:340810 - PanelOperation: FOLDING
OverallHeight: 2100 mm; OverallWidth: 800 mm
Pset_DoorCommon - IsExternal: no; Reference: SU-18
AR_IFC_UKSED - 01.Nimetus: Siseuks; 02.Materjal: Puit; 03.Kategooria / tüüp: SU-18; 04.Avamõõdu geomeetria: 800x2100; 05.Asukoha info: Interior; 06.Soojusläbivus: -; 07.Helipidavus: 34 dB; 08.Veepidavus: -; 09.Õhuläbilaskvus: -; 10.Tulekindlus: -; 11.Vastupanu tulekoormusele: -; 12.Klaaspakett: -; 13.Klaasingu erisused: -; 14.Päikesekiirgus tegur (g-väärtus): -; 15.Avanemine: -; 16.Liigendatus: -; 17.Sulused, lukustus: -; 18.Viimistlus: Tammespoon
Name (Lükanduks:SU-18:...)
340810
340992

# IfcDoor: SU-18., Lükanduks:SU-18.:337993
In: 1 korrus
Type - OperationType: FOLDING_TO_LEFT; ParameterTakesPrecedence: no; Sizeable: no; Material: Door Handle - Aluminium, __Uks_hele tamm
Type - Lükanduks:SU-18.:337993 - PanelOperation: FOLDING
OverallHeight: 2100 mm; OverallWidth: 800 mm
Pset_DoorCommon - IsExternal: no; Reference: SU-18.
AR_IFC_UKSED - 01.Nimetus: Siseuks; 02.Materjal: Puit; 03.Kategooria / tüüp: SU-18; 04.Avamõõdu geomeetria: 800x2100; 05.Asukoha info: Interior; 06.Soojusläbivus: -; 07.Helipidavus: 34 dB; 08.Veepidavus: -; 09.Õhuläbilaskvus: -; 10.Tulekindlus: -; 11.Vastupanu tulekoormusele: -; 12.Klaaspakett: -; 13.Klaasingu erisused: -; 14.Päikesekiirgus tegur (g-väärtus): -; 15.Avanemine: -; 16.Liigendatus: -; 17.Sulused, lukustus: -; 18.Viimistlus: Tammespoon

# IfcDoor: SU-19, Klaasist lükanduksed:SU-19:797009
In: 1 korrus
Type - ParameterTakesPrecedence: no; Sizeable: no; Material: Besam-Anodized Aluminium, Besam-Glass Clear
OverallHeight: 2540 mm; OverallWidth: 4120 mm
Pset_DoorCommon - IsExternal: no; Reference: SU-19
AR_IFC_UKSED - 01.Nimetus: Siseuks; 02.Materjal: Alumiinium; 03.Kategooria / tüüp: SU-19; 04.Avamõõdu geomeetria: 4100x2685; 05.Asukoha info: Interior; 06.Soojusläbivus: -; 07.Helipidavus: 30 dB; 08.Veepidavus: -; 09.Õhuläbilaskvus: -; 10.Tulekindlus: EI-30; 11.Vastupanu tulekoormusele: -; 12.Klaaspakett: karastatud klaas; 13.Klaasingu erisused: -; 14.Päikesekiirgus tegur (g-väärtus): -; 15.Avanemine: -; 16.Liigendatus: kahepoolne; 17.Sulused, lukustus: ASSA ABLOY liugveovarrega sulgur, sulgemisjärjesti; 18.Viimistlus: RAL8019; 19.Mudel või toote tunnus: -; 20.Tootja: -

# IfcDoor: SU-20, Ühepoolsed:SU-20:1353896
In: uus 1 korrus
Type - OperationType: FOLDING_TO_LEFT; ParameterTakesPrecedence: no; Sizeable: no; Material: _Alumiiniumprofiil - must, Steel/Aluminium
Type - Ühepoolsed:SU-20:1353896 - PanelOperation: FOLDING
OverallHeight: 1700 mm; OverallWidth: 800 mm
Pset_DoorCommon - IsExternal: no; Reference: SU-20
AR_IFC_UKSED - 01.Nimetus: Siseuks; 02.Materjal: Metall; 03.Kategooria / tüüp: SU-20; 04.Avamõõdu geomeetria: 800x1700; 05.Asukoha info: Interior; 06.Soojusläbivus: -; 07.Helipidavus: -; 08.Veepidavus: -; 09.Õhuläbilaskvus: -; 10.Tulekindlus: -; 11.Vastupanu tulekoormusele: -; 12.Klaaspakett: -; 13.Klaasingu erisused: -; 14.Päikesekiirgus tegur (g-väärtus): -; 15.Avanemine: Folding to Left; 16.Liigendatus: -; 17.Sulused, lukustus: -; 18.Viimistlus: RAL8019; 19.Mudel või toote tunnus: -; 20.Tootja: -

# IfcDoor: SU-21, Kahepoolsed:SU-21:1268425
In: 1 korrus
Type - OperationType: FOLDING_TO_RIGHT; ParameterTakesPrecedence: no; Sizeable: no; Material: _Alumiiniumprofiil - must, __Uks_hele tamm, EP Tavallinen lasi
Type - Kahepoolsed:SU-21:1268425 - PanelOperation: FOLDING
OverallHeight: 2100 mm; OverallWidth: 1200 mm
Pset_DoorCommon - IsExternal: no; Reference: SU-21
AR_IFC_UKSED - 01.Nimetus: Siseuks; 02.Materjal: Puit; 03.Kategooria / tüüp: SU-21; 04.Avamõõdu geomeetria: 1200x2100; 05.Asukoha info: Interior; 06.Soojusläbivus: -; 07.Helipidavus: 30 dB; 08.Veepidavus: -; 09.Õhuläbilaskvus: -; 10.Tulekindlus: -; 11.Vastupanu tulekoormusele: -; 12.Klaaspakett: karastatud klaas; 13.Klaasingu erisused: -; 14.Päikesekiirgus tegur (g-väärtus): -; 15.Avanemine: -; 16.Liigendatus: kahepoolne; 17.Sulused, lukustus: ASSA ABLOY liugveovarrega sulgur; 18.Viimistlus: Tammespoon; 19.Mudel või toote tunnus: -; 20.Tootja: -

# IfcDoor: SU-22, Kahepoolsed:SU-22:508662
In: 2 korrus
Type - OperationType: FOLDING_TO_RIGHT; ParameterTakesPrecedence: no; Sizeable: no; Material: _Alumiiniumprofiil - must, __Uks_hele tamm, EP Tavallinen lasi
Type - Kahepoolsed:SU-22:508662 - PanelOperation: FOLDING
OverallHeight: 2360 mm; OverallWidth: 1500 mm
Pset_DoorCommon - IsExternal: no; Reference: SU-22
AR_IFC_UKSED - 01.Nimetus: Siseuks; 02.Materjal: Puit; 03.Kategooria / tüüp: SU-22; 04.Avamõõdu geomeetria: 1500x2360; 05.Asukoha info: Interior; 06.Soojusläbivus: -; 07.Helipidavus: 30 dB; 08.Veepidavus: -; 09.Õhuläbilaskvus: -; 10.Tulekindlus: -; 11.Vastupanu tulekoormusele: -; 12.Klaaspakett: karastatud klaas; 13.Klaasingu erisused: -; 14.Päikesekiirgus tegur (g-väärtus): -; 15.Avanemine: Folding to Left; 16.Liigendatus: kahepoolne; 17.Sulused, lukustus: ASSA ABLOY liugveovarrega sulgur, sulgemisjärjesti; 18.Viimistlus: Tammespoon; 19.Mudel või toote tunnus: -; 20.Tootja: -

# IfcDoor: SU-23, Kahepoolsed:SU-23:1239711
In: 4 korrus
Type - OperationType: FOLDING_TO_RIGHT; ParameterTakesPrecedence: no; Sizeable: no; Material: _Alumiiniumprofiil - must, __Uks_hele tamm, EP Tavallinen lasi
Type - Kahepoolsed:SU-23:1239711 - PanelOperation: FOLDING
OverallHeight: 2420 mm; OverallWidth: 1500 mm
Pset_DoorCommon - IsExternal: no; Reference: SU-23
AR_IFC_UKSED - 01.Nimetus: Siseuks; 02.Materjal: Puit; 03.Kategooria / tüüp: SU-23; 04.Avamõõdu geomeetria: 1500x2420; 05.Asukoha info: Interior; 06.Soojusläbivus: -; 07.Helipidavus: 30 dB; 08.Veepidavus: -; 09.Õhuläbilaskvus: -; 10.Tulekindlus: -; 11.Vastupanu tulekoormusele: -; 12.Klaaspakett: karastatud klaas; 13.Klaasingu erisused: -; 14.Päikesekiirgus tegur (g-väärtus): -; 15.Avanemine: Folding to Left; 16.Liigendatus: kahepoolne; 17.Sulused, lukustus: ASSA ABLOY liugveovarrega sulgur, sulgemisjärjesti; 18.Viimistlus: Tammespoon; 19.Mudel või toote tunnus: -; 20.Tootja: -

# IfcDoor: SU-24, Kahepoolsed:SU-24:1438414
In: uus 1 korrus
Type - OperationType: FOLDING_TO_RIGHT; ParameterTakesPrecedence: no; Sizeable: no; Material: _Alumiiniumprofiil - must, __Uks_hele tamm, EP Tavallinen lasi
Type - Kahepoolsed:SU-24:1438414 - PanelOperation: FOLDING
OverallHeight: 2100 mm; OverallWidth: 1250 mm
Pset_DoorCommon - IsExternal: no; Reference: SU-24

# IfcDoor: SU-25, Kahepoolsed:SU-25:1455512
In: uus 1 korrus
Type - ParameterTakesPrecedence: no; Sizeable: no; Material: _Alumiiniumprofiil - must, Steel/Aluminium
OverallHeight: 2500 mm; OverallWidth: 1780 mm
Pset_DoorCommon - IsExternal: no; Reference: SU-25

# IfcDoor: SU16_ülemine, Ühepoolsed:SU16_ülemine:1243722
In: 1 korrus
Type - OperationType: SINGLE_SWING_RIGHT; ParameterTakesPrecedence: no; Sizeable: no; Material: _Alumiiniumprofiil - must, __Uks_hele tamm
Type - Ühepoolsed:SU16_ülemine:1243722 - PanelOperation: SWINGING
OverallHeight: 540 mm; OverallWidth: 2350 mm
Pset_DoorCommon - IsExternal: no; Reference: SU16_ülemine
AR_IFC_UKSED - 01.Nimetus: Siseuks; 02.Materjal: Puit; 03.Kategooria / tüüp: SU-16; 04.Avamõõdu geomeetria: 2350x540; 05.Asukoha info: Interior; 06.Soojusläbivus: -; 07.Helipidavus: 30 dB; 08.Veepidavus: -; 09.Õhuläbilaskvus: -; 10.Tulekindlus: EI-30; 11.Vastupanu tulekoormusele: -; 12.Klaaspakett: karastatud klaas; 13.Klaasingu erisused: tuletõkke klaas; 14.Päikesekiirgus tegur (g-väärtus): -; 15.Avanemine: -; 16.Liigendatus: -; 17.Sulused, lukustus: -; 18.Viimistlus: Tammespoon; 19.Mudel või toote tunnus: -; 20.Tootja: -

# IfcDoor: SU17_ülemine (3)
Type - OperationType: SINGLE_SWING_RIGHT; ParameterTakesPrecedence: no; Sizeable: no; Material: _Alumiiniumprofiil - must, __Uks_hele tamm
Type - Ühepoolsed:SU17_ülemine:1421710 - PanelOperation: SWINGING
OverallHeight: 540 mm; OverallWidth: 2500 mm
Pset_DoorCommon - IsExternal: no; Reference: SU17_ülemine
AR_IFC_UKSED - 01.Nimetus: Siseuks; 02.Materjal: Puit; 03.Kategooria / tüüp: SU-17; 04.Avamõõdu geomeetria: 540x2500; 05.Asukoha info: Interior; 06.Soojusläbivus: -; 07.Helipidavus: 30 dB; 08.Veepidavus: -; 09.Õhuläbilaskvus: -; 10.Tulekindlus: EI-30; 11.Vastupanu tulekoormusele: -; 12.Klaaspakett: karastatud klaas; 13.Klaasingu erisused: tuletõkke klaas; 14.Päikesekiirgus tegur (g-väärtus): -; 15.Avanemine: -; 16.Liigendatus: -; 17.Sulused, lukustus: -; 18.Viimistlus: Tammespoon; 19.Mudel või toote tunnus: -; 20.Tootja: -
Name (Ühepoolsed:SU17_ülemine:...) | In
1421710 | uus 2 korrus
1421923 | uus 3 korrus
1421985 | uus Katus

# IfcDoor: SU24_ülemine, Ühepoolsed2:SU24_ülemine:1445358
In: 1 korrus
Type - ParameterTakesPrecedence: no; Sizeable: no; Material: __Uks_hele tamm
OverallHeight: 600 mm; OverallWidth: 1250 mm
Pset_DoorCommon - IsExternal: no; Reference: SU24_ülemine

# IfcDoor: VU-01, Klaasist lükanduksed:VU-01:1418164
In: 1 korrus
Type - ParameterTakesPrecedence: no; Sizeable: no; Material: Steel/Aluminium, Besam-Glass Clear
OverallHeight: 2540 mm; OverallWidth: 4120 mm
Pset_DoorCommon - IsExternal: no; Reference: VU-01
AR_IFC_UKSED - 01.Nimetus: Välisuks; 02.Materjal: Alumiinium; 03.Kategooria / tüüp: VU-01; 04.Avamõõdu geomeetria: 4100x2685; 05.Asukoha info: Exterior; 06.Soojusläbivus: 1.0 W/m²K; 07.Helipidavus: 30 dB; 08.Veepidavus: 7A; 09.Õhuläbilaskvus: klass 4; 10.Tulekindlus: -; 11.Vastupanu tulekoormusele: C3; 12.Klaaspakett: karastatud klaas; 13.Klaasingu erisused: -; 14.Päikesekiirgus tegur (g-väärtus): 0.6; 15.Avanemine: -; 16.Liigendatus: kahepoolne; 17.Sulused, lukustus: ASSA ABLOY liugveovarrega sulgur, sulgemisjärjesti; 18.Viimistlus: RAL8019; 19.Mudel või toote tunnus: -; 20.Tootja: -

# IfcDoor: VU-02, Kahepoolsed:VU-02:239211
In: 1 korrus
Type - OperationType: FOLDING_TO_RIGHT; ParameterTakesPrecedence: no; Sizeable: no; Material: _Alumiiniumprofiil - must, Steel/Aluminium, EP Tavallinen lasi
Type - Kahepoolsed:VU-02:239211 - PanelOperation: FOLDING
OverallHeight: 2140 mm; OverallWidth: 1655 mm
Pset_DoorCommon - IsExternal: yes; Reference: VU-02
AR_IFC_UKSED - 01.Nimetus: Välisuks; 02.Materjal: Alumiinium; 03.Kategooria / tüüp: VU-02; 04.Avamõõdu geomeetria: 1655x2100; 05.Asukoha info: Exterior; 06.Soojusläbivus: 1.0 W/m²K; 07.Helipidavus: 34 dB; 08.Veepidavus: 7A; 09.Õhuläbilaskvus: klass 4; 10.Tulekindlus: -; 11.Vastupanu tulekoormusele: C3; 12.Klaaspakett: 3x klaaspakett; 13.Klaasingu erisused: Tripleksklaas; 14.Päikesekiirgus tegur (g-väärtus): 0.6; 15.Avanemine: Folding to Right; 16.Liigendatus: kahepoolne; 17.Sulused, lukustus: ASSA ABLOY liugveovarrega sulgur, sulgemisjärjesti; 18.Viimistlus: RAL8019; 19.Mudel või toote tunnus: -; 20.Tootja: -

# IfcDoor: VU-03, Kahepoolsed:VU-03:316793
In: 1 korrus
Type - OperationType: FOLDING_TO_RIGHT; ParameterTakesPrecedence: no; Sizeable: no; Material: _Alumiiniumprofiil - must, Steel/Aluminium, EP Tavallinen lasi
Type - Kahepoolsed:VU-03:316793 - PanelOperation: FOLDING
OverallHeight: 2652 mm; OverallWidth: 1280 mm
Pset_DoorCommon - IsExternal: yes; Reference: VU-03
AR_IFC_UKSED - 01.Nimetus: Välisuks; 02.Materjal: Alumiinium; 03.Kategooria / tüüp: VU-03; 04.Avamõõdu geomeetria: 1280x2650; 05.Asukoha info: Exterior; 06.Soojusläbivus: 1.0 W/m²K; 07.Helipidavus: 34 dB; 08.Veepidavus: 7A; 09.Õhuläbilaskvus: klass 4; 10.Tulekindlus: -; 11.Vastupanu tulekoormusele: C3; 12.Klaaspakett: 3x klaaspakett; 13.Klaasingu erisused: Tripleksklaas; 14.Päikesekiirgus tegur (g-väärtus): 0.6; 15.Avanemine: Folding to Left; 16.Liigendatus: kahepoolne; 17.Sulused, lukustus: ASSA ABLOY liugveovarrega sulgur, sulgemisjärjesti; 18.Viimistlus: RAL8019; 19.Mudel või toote tunnus: -; 20.Tootja: -

# IfcDoor: VU-04 (2)
In: 1 korrus
Type - OperationType: FOLDING_TO_LEFT; ParameterTakesPrecedence: no; Sizeable: no; Material: _Alumiiniumprofiil - must, Steel/Aluminium
Type - Ühepoolsed:VU-04:1257071 - PanelOperation: FOLDING
OverallHeight: 2200 mm; OverallWidth: 1000 mm
Pset_DoorCommon - IsExternal: yes; Reference: VU-04
AR_IFC_UKSED - 01.Nimetus: Välisuks; 02.Materjal: Teras; 03.Kategooria / tüüp: VU-04; 04.Avamõõdu geomeetria: 1000x2200; 05.Asukoha info: Exterior; 06.Soojusläbivus: 1.0 W/m²K; 07.Helipidavus: 30 dB; 08.Veepidavus: 7A; 09.Õhuläbilaskvus: klass 4; 10.Tulekindlus: -; 11.Vastupanu tulekoormusele: C3; 12.Klaaspakett: -; 13.Klaasingu erisused: -; 14.Päikesekiirgus tegur (g-väärtus): -; 15.Avanemine: Folding to Right; 16.Liigendatus: -; 17.Sulused, lukustus: ASSA ABLOY liugveovarrega sulgur; 18.Viimistlus: RAL8019; 19.Mudel või toote tunnus: -; 20.Tootja: -
Name (Ühepoolsed:VU-04:...)
1257071
1257104

# IfcDoor: VU-04 (2)
In: Katusekorrus
Type - OperationType: FOLDING_TO_LEFT; ParameterTakesPrecedence: no; Sizeable: no; Material: _Alumiiniumprofiil - must, Steel/Aluminium
Type - Ühepoolsed:VU-04:957025 - PanelOperation: FOLDING
OverallHeight: 2200 mm; OverallWidth: 1000 mm
Pset_DoorCommon - IsExternal: yes; Reference: VU-04
AR_IFC_UKSED - 01.Nimetus: Välisuks; 02.Materjal: Teras; 03.Kategooria / tüüp: VU-04; 04.Avamõõdu geomeetria: 1000x2200; 05.Asukoha info: Exterior; 06.Soojusläbivus: 1.0 W/m²K; 07.Helipidavus: 30 dB; 08.Veepidavus: 7A; 09.Õhuläbilaskvus: klass 4; 10.Tulekindlus: -; 11.Vastupanu tulekoormusele: C3; 12.Klaaspakett: -; 13.Klaasingu erisused: -; 14.Päikesekiirgus tegur (g-väärtus): -; 15.Avanemine: Folding to Right; 16.Liigendatus: -; 17.Sulused, lukustus: ASSA ABLOY liugveovarrega sulgur; 18.Viimistlus: RAL8019; 19.Mudel või toote tunnus: -; 20.Tootja: -
Name (Ühepoolsed:VU-04:...)
957025
957127

# IfcDoor: VU-04., Ühepoolsed:VU-04.:1010181
In: uus Katus
Type - OperationType: FOLDING_TO_LEFT; ParameterTakesPrecedence: no; Sizeable: no; Material: _Alumiiniumprofiil - must, Steel/Aluminium
Type - Ühepoolsed:VU-04.:1010181 - PanelOperation: FOLDING
OverallHeight: 2200 mm; OverallWidth: 1000 mm
Pset_DoorCommon - IsExternal: yes; Reference: VU-04.
AR_IFC_UKSED - 01.Nimetus: Välisuks; 02.Materjal: Teras; 03.Kategooria / tüüp: VU-04; 04.Avamõõdu geomeetria: 1000x2200; 05.Asukoha info: Exterior; 06.Soojusläbivus: 1.0 W/m²K; 07.Helipidavus: 30 dB; 08.Veepidavus: 7A; 09.Õhuläbilaskvus: klass 4; 10.Tulekindlus: -; 11.Vastupanu tulekoormusele: C3; 12.Klaaspakett: -; 13.Klaasingu erisused: -; 14.Päikesekiirgus tegur (g-väärtus): -; 15.Avanemine: Folding to Left; 16.Liigendatus: -; 17.Sulused, lukustus: ASSA ABLOY liugveovarrega sulgur; 18.Viimistlus: RAL8019; 19.Mudel või toote tunnus: -; 20.Tootja: -

# IfcDoor: VU-05, Ühepoolsed:VU-05:1339524
In: 1 korrus
Type - OperationType: FOLDING_TO_LEFT; ParameterTakesPrecedence: no; Sizeable: no; Material: _Alumiiniumprofiil - must, Steel/Aluminium
Type - Ühepoolsed:VU-05:1339524 - PanelOperation: FOLDING
OverallHeight: 2300 mm; OverallWidth: 900 mm
Pset_DoorCommon - IsExternal: yes; Reference: VU-05
AR_IFC_UKSED - 01.Nimetus: Välisuks; 02.Materjal: Teras; 03.Kategooria / tüüp: VU-05; 04.Avamõõdu geomeetria: 900x2300; 05.Asukoha info: Exterior; 06.Soojusläbivus: 1.0 W/m²K; 07.Helipidavus: -; 08.Veepidavus: 7A; 09.Õhuläbilaskvus: klass 4; 10.Tulekindlus: -; 11.Vastupanu tulekoormusele: C3; 12.Klaaspakett: -; 13.Klaasingu erisused: -; 14.Päikesekiirgus tegur (g-väärtus): -; 15.Avanemine: Folding to Right; 16.Liigendatus: -; 17.Sulused, lukustus: ASSA ABLOY liugveovarrega sulgur; 18.Viimistlus: RAL8019; 19.Mudel või toote tunnus: -; 20.Tootja: -

# IfcDoor: VU-06, Ühepoolsed:VU-06:1339736
In: 1 korrus
Type - OperationType: FOLDING_TO_LEFT; ParameterTakesPrecedence: no; Sizeable: no; Material: _Alumiiniumprofiil - must, Steel/Aluminium
Type - Ühepoolsed:VU-06:1339736 - PanelOperation: FOLDING
OverallHeight: 2300 mm; OverallWidth: 1300 mm
Pset_DoorCommon - IsExternal: yes; Reference: VU-06
AR_IFC_UKSED - 01.Nimetus: Välisuks; 02.Materjal: Teras; 03.Kategooria / tüüp: VU-06; 04.Avamõõdu geomeetria: 1390x2300; 05.Asukoha info: Interior; 06.Soojusläbivus: 1.0 W/m²K; 07.Helipidavus: -; 08.Veepidavus: 7A; 09.Õhuläbilaskvus: klass 4; 10.Tulekindlus: -; 11.Vastupanu tulekoormusele: C3; 12.Klaaspakett: -; 13.Klaasingu erisused: -; 14.Päikesekiirgus tegur (g-väärtus): -; 15.Avanemine: Folding to Right; 16.Liigendatus: -; 17.Sulused, lukustus: ASSA ABLOY liugveovarrega sulgur; 18.Viimistlus: RAL8019; 19.Mudel või toote tunnus: -; 20.Tootja: -

# IfcDoor: liftiuks (5)
Type - ParameterTakesPrecedence: no; Sizeable: no; Material: Wood - Pine Grained Horizontal
OverallHeight: 2100 mm; OverallWidth: 903.931 mm
Pset_DoorCommon - IsExternal: no; Reference: liftiuks
AR_IFC_UKSED - 01.Nimetus: Liftiuks; 02.Materjal: Alumiinium; 03.Kategooria / tüüp: -; 04.Avamõõdu geomeetria: 900x2100; 05.Asukoha info: Interior; 06.Soojusläbivus: -; 07.Helipidavus: -; 08.Veepidavus: -; 09.Õhuläbilaskvus: -; 10.Tulekindlus: E30; 11.Vastupanu tulekoormusele: -; 12.Klaaspakett: -; 13.Klaasingu erisused: -; 14.Päikesekiirgus tegur (g-väärtus): -; 15.Avanemine: -; 16.Liigendatus: kahepoolne; 17.Sulused, lukustus: -; 18.Viimistlus: -; 19.Mudel või toote tunnus: -; 20.Tootja: -
Name (liftiuks:liftiuks:...) | In
239221 | 1 korrus
239505 | 2 korrus
239648 | 3 korrus
239893 | 4 korrus
239920 | Katusekorrus

# IfcFlowTerminal: ___LED___subcomponent (4)
In: 501
Type - Material: Cibes_spotlight
Pset_DistributionFlowElementCommon - Reference: ___LED___subcomponent
Name (___LED___subcomponent:___LED___subcomponent:...)
1767891
1767893
1767894
1767935

# IfcMember: 20 x 20mm (235)
Type - ElementType: 20 x 20mm; PredefinedType: MEMBER
Material: __Uks_hele tamm
Pset_MemberCommon - LoadBearing: yes; Reference: 20 x 20mm
Name (Rectangular Mullion:20 x 20mm:...) | In | IsExternal | Span (mm)
329690 | 1 korrus | no | 2090
329691 | 1 korrus | no | 2080
338193 | 1 korrus | no | 400
338194 | 1 korrus | no | 400
339043 | 1 korrus | no | 908
341509 | 1 korrus | no | 2090
341510 | 1 korrus | no | 2080
341529 | 1 korrus | no | 400
341530 | 1 korrus | no | 400
341538 | 1 korrus | no | 912
489053 | 1 korrus | no | 2080
489054 | 1 korrus | no | 2090
489074 | 1 korrus | no | 300
489075 | 1 korrus | no | 300
489184 | 1 korrus | no | 11
1078339 | 1 korrus | no | 2090
1078340 | 1 korrus | no | 300
495742 | 1 korrus | no | 2080
495743 | 1 korrus | no | 2090
495763 | 1 korrus | no | 300
495764 | 1 korrus | no | 300
495770 | 1 korrus | no | 210
1076371 | 1 korrus | no | 3.86941
1078541 | 1 korrus | no | 2090
1078542 | 1 korrus | no | 300
1078622 | 1 korrus | no | 2090
1078623 | 1 korrus | no | 300
561698 | 2 korrus | no | 2110
515365 | 2 korrus | no | 2110
515367 | 2 korrus | no | 2110
515373 | 2 korrus | no | 290
515375 | 2 korrus | no | 290
515380 | 2 korrus | no | 2110
515381 | 2 korrus | no | 290
515405 | 2 korrus | no | 2110
515406 | 2 korrus | no | 2110
515408 | 2 korrus | no | 290
515409 | 2 korrus | no | 290
1202944 | 2 korrus | no | 2110
1202945 | 2 korrus | no | 290
520286 | 2 korrus | no | 2080
520306 | 2 korrus | no | 300
520312 | 2 korrus | no | 11.5476
520317 | 2 korrus | no | 1.54757
520318 | 2 korrus | no | 2080
520319 | 2 korrus | no | 300
1337281 | 2 korrus | no | 898.452
1337282 | 2 korrus | no | 100
1337285 | 2 korrus | no | 300
1337286 | 2 korrus | no | 300
555095 | 2 korrus | no | 2080
555114 | 2 korrus | no | 300
555120 | 2 korrus | no | 910
555125 | 2 korrus | no | 746.494
555126 | 2 korrus | no | 2080
555127 | 2 korrus | no | 300
1116307 | 2 korrus | no | 2090
1116308 | 2 korrus | no | 2090
1116309 | 2 korrus | no | 300
1116310 | 2 korrus | no | 300
555685 | 2 korrus | no | 2080
555704 | 2 korrus | no | 300
555710 | 2 korrus | no | 910
555715 | 2 korrus | no | 60
555716 | 2 korrus | no | 2080
555717 | 2 korrus | no | 300
562890 | 3 korrus | no | 2090
562891 | 3 korrus | no | 2080
562910 | 3 korrus | no | 300
562911 | 3 korrus | no | 300
562917 | 3 korrus | no | 910
562922 | 3 korrus | no | 98
562923 | 3 korrus | no | 2080
562924 | 3 korrus | no | 300
562979 | 3 korrus | no | 1
562980 | 3 korrus | no | 2090
562981 | 3 korrus | no | 300
563295 | 3 korrus | no | 899
1366799 | 3 korrus | no | 102
1366800 | 3 korrus | no | 2080
1366801 | 3 korrus | no | 300
563022 | 4 korrus | no | 2090
563023 | 4 korrus | no | 2080
563042 | 4 korrus | no | 300
563043 | 4 korrus | no | 300
563049 | 4 korrus | no | 910
563054 | 4 korrus | no | 100
563055 | 4 korrus | no | 2080
563056 | 4 korrus | no | 300
567768 | 3 korrus | no | 2090
567787 | 3 korrus | no | 300
567793 | 3 korrus | no | 738.145
567798 | 3 korrus | no | 171.855
567799 | 3 korrus | no | 2080
567800 | 3 korrus | no | 300
567806 | 3 korrus | no | 755.645
568494 | 3 korrus | no | 2090
568513 | 3 korrus | no | 300
568519 | 3 korrus | no | 2
568524 | 3 korrus | no | 476
568531 | 3 korrus | no | 12
1100869 | 3 korrus | no | 100
1100870 | 3 korrus | no | 2080
1100871 | 3 korrus | no | 300
1101102 | 3 korrus | no | 900
1101103 | 3 korrus | no | 2080
1101104 | 3 korrus | no | 300
569298 | 3 korrus | no | 2110
569299 | 3 korrus | no | 2110
569305 | 3 korrus | no | 290
569306 | 3 korrus | no | 290
569310 | 3 korrus | no | 2110
569311 | 3 korrus | no | 290
569331 | 3 korrus | no | 2110
569332 | 3 korrus | no | 2110
569333 | 3 korrus | no | 290
569334 | 3 korrus | no | 290
964666 | 3 korrus | no | 2110
964667 | 3 korrus | no | 290
574388 | 3 korrus | no | 2090
574389 | 3 korrus | no | 2080
574408 | 3 korrus | no | 300
574409 | 3 korrus | no | 300
574415 | 3 korrus | no | 910
574420 | 3 korrus | no | 1088.52
574421 | 3 korrus | no | 2080
574422 | 3 korrus | no | 300
574869 | 3 korrus | no | 2090
574870 | 3 korrus | no | 2080
574889 | 3 korrus | no | 300
574890 | 3 korrus | no | 300
574896 | 3 korrus | no | 910
574901 | 3 korrus | no | 100
574902 | 3 korrus | no | 2080
574903 | 3 korrus | no | 300
575484 | 3 korrus | no | 2090
575503 | 3 korrus | no | 300
1055219 | 3 korrus | no | 2090
1055220 | 3 korrus | no | 300
580374 | 4 korrus | no | 2090
580393 | 4 korrus | no | 300
580399 | 4 korrus | no | 473.855
580400 | 4 korrus | no | 1024.86
580405 | 4 korrus | no | 1380
1343611 | 4 korrus | no | 2090
580415 | 4 korrus | no | 2090
580434 | 4 korrus | no | 300
580440 | 4 korrus | no | 860
580446 | 4 korrus | no | 2080
580447 | 4 korrus | no | 300
1349785 | 4 korrus | no | 189.071
1349786 | 4 korrus | no | 2080
580461 | 4 korrus | no | 2110
580462 | 4 korrus | no | 2110
580468 | 4 korrus | no | 290
580469 | 4 korrus | no | 290
580473 | 4 korrus | no | 2110
580474 | 4 korrus | no | 290
580494 | 4 korrus | no | 2110
580495 | 4 korrus | no | 2110
580496 | 4 korrus | no | 290
580497 | 4 korrus | no | 290
1082803 | 4 korrus | no | 2110
1082804 | 4 korrus | no | 290
581272 | 4 korrus | no | 2110
581273 | 4 korrus | no | 2110
581279 | 4 korrus | no | 290
581280 | 4 korrus | no | 290
581284 | 4 korrus | no | 2110
581285 | 4 korrus | no | 290
581305 | 4 korrus | no | 2110
581307 | 4 korrus | no | 290
581584 | 4 korrus | no | 2110
581585 | 4 korrus | no | 290
581605 | 4 korrus | no | 2110
581607 | 4 korrus | no | 290
1350276 | 4 korrus | no | 2110
1350277 | 4 korrus | no | 2110
1350278 | 4 korrus | no | 290
1350279 | 4 korrus | no | 290
927999 | uus 2 korrus | no | 2500
928000 | uus 2 korrus | no | 2500
1457244 | uus 2 korrus | no | 2500
1457245 | uus 2 korrus | no | 2500
1458147 | uus 2 korrus | no | 2500
1458229 | uus 2 korrus | no | 2500
1458415 | uus 2 korrus | no | 2500
1562197 | uus 2 korrus | no | 2500
929408 | uus 2 korrus | no | 2500
929409 | uus 2 korrus | no | 2500
929410 | uus 2 korrus | no | 2500
929411 | uus 2 korrus | no | 2500
929414 | uus 2 korrus | no | 2500
929533 | uus 2 korrus | no | 2500
930157 | uus 2 korrus | no | 2500
930158 | uus 2 korrus | no | 2500
930159 | uus 2 korrus | no | 2500
930520 | uus 2 korrus | no | 2500
930521 | uus 2 korrus | no | 2500
930522 | uus 2 korrus | no | 2500
930856 | uus 2 korrus | no | 2500
930857 | uus 2 korrus | no | 2500
934566 | uus 3 korrus | no | 2500
934567 | uus 3 korrus | no | 2500
934568 | uus 3 korrus | no | 2500
934569 | uus 3 korrus | no | 2500
1095897 | uus 3 korrus | no | 2500
1005816 | uus 3 korrus | no | 2500
1005817 | uus 3 korrus | no | 2500
1117695 | 2 korrus | no | 2090
1117713 | 2 korrus | no | 300
1117726 | 2 korrus | no | 2090
1117727 | 2 korrus | no | 300
1745126 | 4 korrus | no | 2400
1745127 | 4 korrus | no | 2400
1745128 | 4 korrus | no | 2400
1333747 | 2 korrus | no | 2080
1333766 | 2 korrus | no | 300
1333772 | 2 korrus | no | 910
1333777 | 2 korrus | no | 61
1333778 | 2 korrus | no | 2080
1333779 | 2 korrus | no | 300
1334410 | 2 korrus | no | 2080
1334429 | 2 korrus | no | 300
1334435 | 2 korrus | no | 910
1334440 | 2 korrus | no | 60
1334441 | 2 korrus | no | 2080
1334442 | 2 korrus | no | 300
1455986 | 3 korrus | yes | 767.5 | Group: Model Group:KLF-01:1450670
1455987 | 3 korrus | yes | 927.5 | Group: Model Group:KLF-01:1450670
1662684 | 1 korrus | no | 2090
1662685 | 1 korrus | no | 2080
1662705 | 1 korrus | no | 400
1662706 | 1 korrus | no | 400
1662712 | 1 korrus | no | 908

# IfcMember: 25 x 50mm (2)
In: 4 korrus
Type - ElementType: 25 x 50mm; PredefinedType: MEMBER
Material: Metal - Aluminium
Pset_MemberCommon - IsExternal: no; LoadBearing: yes; Reference: 25 x 50mm; Span: 300 mm
Name (Rectangular Mullion:25 x 50mm:...)
1343612
1349787

# IfcMember: 35 x 190mm (480)
In: 3 korrus
Type - ElementType: 35 x 190mm; PredefinedType: MEMBER
Material: Steel/Aluminium
Pset_MemberCommon - IsExternal: yes; LoadBearing: yes; Reference: 35 x 190mm
Name (Rectangular Mullion:35 x 190mm:...) | Span (mm) | Group
1451099 | 1000 | Model Group:KLF-01:1450670
1451100 | 767.5 | Model Group:KLF-01:1450670
1451101 | 50.5723 | Model Group:KLF-01:1450670
1451102 | 677.5 | Model Group:KLF-01:1450670
1451103 | 927.5 | Model Group:KLF-01:1450670
1451104 | 935 | Model Group:KLF-01:1450670
1451107 | 677.5 | Model Group:KLF-01:1450670
1451108 | 685 | Model Group:KLF-01:1450670
1451111 | 685 | Model Group:KLF-01:1450670
1451112 | 815 | Model Group:KLF-01:1450670
1451115 | 815 | Model Group:KLF-01:1450670
1451116 | 965 | Model Group:KLF-01:1450670
1451119 | 965 | Model Group:KLF-01:1450670
1451120 | 385 | Model Group:KLF-01:1450670
1451123 | 385 | Model Group:KLF-01:1450670
1451124 | 565 | Model Group:KLF-01:1450670
1451127 | 565 | Model Group:KLF-01:1450670
1451128 | 685 | Model Group:KLF-01:1450670
1451131 | 685 | Model Group:KLF-01:1450670
1451132 | 785 | Model Group:KLF-01:1450670
1451135 | 785 | Model Group:KLF-01:1450670
1451136 | 965 | Model Group:KLF-01:1450670
1451139 | 965 | Model Group:KLF-01:1450670
1451140 | 685 | Model Group:KLF-01:1450670
1451143 | 685 | Model Group:KLF-01:1450670
1451144 | 965 | Model Group:KLF-01:1450670
1451147 | 965 | Model Group:KLF-01:1450670
1451148 | 2.49997 | Model Group:KLF-01:1450670
1451151 | 965 | Model Group:KLF-01:1450670
1451152 | 767.5 | Model Group:KLF-01:1450670
1451167 | 600 | Model Group:KLF-01:1450670
1451168 | 1000 | Model Group:KLF-01:1450670
1451183 | 600 | Model Group:KLF-01:1450670
1451184 | 1740 | Model Group:KLF-01:1450670
1451199 | 740 | Model Group:KLF-01:1450670
1451200 | 400 | Model Group:KLF-01:1450670
1451215 | 400 | Model Group:KLF-01:1450670
1451216 | 900 | Model Group:KLF-01:1450670
1451231 | 900 | Model Group:KLF-01:1450670
1451232 | 1700.32 | Model Group:KLF-01:1450670
1451247 | 850.16 | Model Group:KLF-01:1450670
1451262 | 900 | Model Group:KLF-01:1450670
1451263 | 760 | Model Group:KLF-01:1450670
1451264 | 850.16 | Model Group:KLF-01:1450670
1451265 | 850.16 | Model Group:KLF-01:1450670
1451266 | 850.16 | Model Group:KLF-01:1450670
1451267 | 850.16 | Model Group:KLF-01:1450670
1451268 | 850.16 | Model Group:KLF-01:1450670
1451269 | 850.16 | Model Group:KLF-01:1450670
1451270 | 850.16 | Model Group:KLF-01:1450670
1451271 | 850.16 | Model Group:KLF-01:1450670
1451272 | 850.16 | Model Group:KLF-01:1450670
1451273 | 850.16 | Model Group:KLF-01:1450670
1451274 | 850.16 | Model Group:KLF-01:1450670
1451275 | 50.5723 | Model Group:KLF-01:1450670
1451276 | 677.5 | Model Group:KLF-01:1450670
1451277 | 685 | Model Group:KLF-01:1450670
1451278 | 815 | Model Group:KLF-01:1450670
1451279 | 965 | Model Group:KLF-01:1450670
1451280 | 385 | Model Group:KLF-01:1450670
1451281 | 565 | Model Group:KLF-01:1450670
1451282 | 685 | Model Group:KLF-01:1450670
1451283 | 785 | Model Group:KLF-01:1450670
1451284 | 965 | Model Group:KLF-01:1450670
1451285 | 685 | Model Group:KLF-01:1450670
1451286 | 965 | Model Group:KLF-01:1450670
1451287 | 965 | Model Group:KLF-01:1450670
1451288 | 767.5 | Model Group:KLF-01:1450670
1451289 | 677.5 | Model Group:KLF-01:1450670
1451290 | 685 | Model Group:KLF-01:1450670
1451291 | 815 | Model Group:KLF-01:1450670
1451292 | 965 | Model Group:KLF-01:1450670
1451293 | 385 | Model Group:KLF-01:1450670
1451294 | 565 | Model Group:KLF-01:1450670
1451295 | 685 | Model Group:KLF-01:1450670
1451296 | 785 | Model Group:KLF-01:1450670
1451297 | 965 | Model Group:KLF-01:1450670
1451298 | 685 | Model Group:KLF-01:1450670
1451299 | 965 | Model Group:KLF-01:1450670
1451300 | 965 | Model Group:KLF-01:1450670
1451301 | 767.5 | Model Group:KLF-01:1450670
1451302 | 677.5 | Model Group:KLF-01:1450670
1451303 | 685 | Model Group:KLF-01:1450670
1451304 | 815 | Model Group:KLF-01:1450670
1451305 | 965 | Model Group:KLF-01:1450670
1451306 | 385 | Model Group:KLF-01:1450670
1451307 | 565 | Model Group:KLF-01:1450670
1451308 | 685 | Model Group:KLF-01:1450670
1451309 | 785 | Model Group:KLF-01:1450670
1451310 | 965 | Model Group:KLF-01:1450670
1451311 | 685 | Model Group:KLF-01:1450670
1451312 | 965 | Model Group:KLF-01:1450670
1451313 | 965 | Model Group:KLF-01:1450670
1451314 | 767.5 | Model Group:KLF-01:1450670
1451315 | 677.5 | Model Group:KLF-01:1450670
1451316 | 685 | Model Group:KLF-01:1450670
1451317 | 815 | Model Group:KLF-01:1450670
1451318 | 965 | Model Group:KLF-01:1450670
1451319 | 385 | Model Group:KLF-01:1450670
1451320 | 565 | Model Group:KLF-01:1450670
1451321 | 685 | Model Group:KLF-01:1450670
1451322 | 785 | Model Group:KLF-01:1450670
1451323 | 965 | Model Group:KLF-01:1450670
1451324 | 685 | Model Group:KLF-01:1450670
1451325 | 965 | Model Group:KLF-01:1450670
1451326 | 965 | Model Group:KLF-01:1450670
1451327 | 767.5 | Model Group:KLF-01:1450670
1451328 | 677.5 | Model Group:KLF-01:1450670
1451329 | 685 | Model Group:KLF-01:1450670
1451330 | 815 | Model Group:KLF-01:1450670
1451331 | 965 | Model Group:KLF-01:1450670
1451332 | 385 | Model Group:KLF-01:1450670
1451333 | 565 | Model Group:KLF-01:1450670
1451334 | 685 | Model Group:KLF-01:1450670
1451335 | 785 | Model Group:KLF-01:1450670
1451336 | 965 | Model Group:KLF-01:1450670
1451337 | 685 | Model Group:KLF-01:1450670
1451338 | 965 | Model Group:KLF-01:1450670
1451339 | 965 | Model Group:KLF-01:1450670
1451340 | 767.5 | Model Group:KLF-01:1450670
1451341 | 927.5 | Model Group:KLF-01:1450670
1451342 | 767.5 | Model Group:KLF-01:1450670
1451343 | 927.5 | Model Group:KLF-01:1450670
1451344 | 767.5 | Model Group:KLF-01:1450670
1451345 | 1000 | Model Group:KLF-01:1450670
1451346 | 600 | Model Group:KLF-01:1450670
1451347 | 740 | Model Group:KLF-01:1450670
1451348 | 400 | Model Group:KLF-01:1450670
1451349 | 900 | Model Group:KLF-01:1450670
1451350 | 1000 | Model Group:KLF-01:1450670
1451351 | 600 | Model Group:KLF-01:1450670
1451352 | 740 | Model Group:KLF-01:1450670
1451353 | 400 | Model Group:KLF-01:1450670
1451354 | 900 | Model Group:KLF-01:1450670
1451355 | 1000 | Model Group:KLF-01:1450670
1451356 | 600 | Model Group:KLF-01:1450670
1451357 | 740 | Model Group:KLF-01:1450670
1451358 | 400 | Model Group:KLF-01:1450670
1451359 | 900 | Model Group:KLF-01:1450670
1451360 | 1000 | Model Group:KLF-01:1450670
1451361 | 600 | Model Group:KLF-01:1450670
1451362 | 740 | Model Group:KLF-01:1450670
1451363 | 400 | Model Group:KLF-01:1450670
1451364 | 900 | Model Group:KLF-01:1450670
1451365 | 1000 | Model Group:KLF-01:1450670
1451366 | 600 | Model Group:KLF-01:1450670
1451367 | 740 | Model Group:KLF-01:1450670
1451368 | 400 | Model Group:KLF-01:1450670
1451369 | 900 | Model Group:KLF-01:1450670
1451370 | 1000 | Model Group:KLF-01:1450670
1451371 | 600 | Model Group:KLF-01:1450670
1451372 | 740 | Model Group:KLF-01:1450670
1451373 | 400 | Model Group:KLF-01:1450670
1451374 | 900 | Model Group:KLF-01:1450670
1451375 | 1000 | Model Group:KLF-01:1450670
1451376 | 600 | Model Group:KLF-01:1450670
1451377 | 740 | Model Group:KLF-01:1450670
1451378 | 400 | Model Group:KLF-01:1450670
1451379 | 900 | Model Group:KLF-01:1450670
1451380 | 1000 | Model Group:KLF-01:1450670
1451381 | 600 | Model Group:KLF-01:1450670
1451382 | 740 | Model Group:KLF-01:1450670
1451383 | 400 | Model Group:KLF-01:1450670
1451384 | 900 | Model Group:KLF-01:1450670
1451385 | 1000 | Model Group:KLF-01:1450670
1451386 | 600 | Model Group:KLF-01:1450670
1451387 | 740 | Model Group:KLF-01:1450670
1451388 | 400 | Model Group:KLF-01:1450670
1451389 | 900 | Model Group:KLF-01:1450670
1451390 | 1000 | Model Group:KLF-01:1450670
1451391 | 600 | Model Group:KLF-01:1450670
1451392 | 740 | Model Group:KLF-01:1450670
1451393 | 400 | Model Group:KLF-01:1450670
1451394 | 900 | Model Group:KLF-01:1450670
1451395 | 1000 | Model Group:KLF-01:1450670
1451396 | 600 | Model Group:KLF-01:1450670
1451397 | 740 | Model Group:KLF-01:1450670
1451398 | 400 | Model Group:KLF-01:1450670
1451399 | 900 | Model Group:KLF-01:1450670
1451400 | 1000 | Model Group:KLF-01:1450670
1451401 | 600 | Model Group:KLF-01:1450670
1451402 | 740 | Model Group:KLF-01:1450670
1451403 | 400 | Model Group:KLF-01:1450670
1451404 | 900 | Model Group:KLF-01:1450670
1451405 | 850.16 | Model Group:KLF-01:1450670
1451406 | 900 | Model Group:KLF-01:1450670
1451421 | 740 | Model Group:KLF-01:1450670
1451422 | 1740 | Model Group:KLF-01:1450670
1451423 | 1740 | Model Group:KLF-01:1450670
1451424 | 1740 | Model Group:KLF-01:1450670
1451425 | 1740 | Model Group:KLF-01:1450670
1451426 | 1740 | Model Group:KLF-01:1450670
1451427 | 1740 | Model Group:KLF-01:1450670
1451428 | 1740 | Model Group:KLF-01:1450670
1451429 | 1740 | Model Group:KLF-01:1450670
1451430 | 1740 | Model Group:KLF-01:1450670
1451431 | 1740 | Model Group:KLF-01:1450670
1451432 | 1740 | Model Group:KLF-01:1450670
1451433 | 1740 | Model Group:KLF-01:1450670
1451434 | 1740 | Model Group:KLF-01:1450670
1451449 | 850.16 | Model Group:KLF-01:1450670
1451450 | 1700.32 | Model Group:KLF-01:1450670
1451451 | 1700.32 | Model Group:KLF-01:1450670
1451452 | 1700.32 | Model Group:KLF-01:1450670
1451453 | 1700.32 | Model Group:KLF-01:1450670
1451454 | 1700.32 | Model Group:KLF-01:1450670
1451455 | 1700.32 | Model Group:KLF-01:1450670
1451456 | 1700.32 | Model Group:KLF-01:1450670
1451457 | 1700.32 | Model Group:KLF-01:1450670
1451458 | 1700.32 | Model Group:KLF-01:1450670
1451459 | 1700.32 | Model Group:KLF-01:1450670
1451460 | 1700.32 | Model Group:KLF-01:1450670
1451461 | 1700.32 | Model Group:KLF-01:1450670
1451462 | 1700.32 | Model Group:KLF-01:1450670
1451477 | 760 | Model Group:KLF-01:1450670
1451478 | 1184.43 | Model Group:KLF-01:1450670
1451479 | 760 | Model Group:KLF-01:1450670
1451480 | 685 | Model Group:KLF-01:1450670
1451481 | 965 | Model Group:KLF-01:1450670
1451482 | 785 | Model Group:KLF-01:1450670
1451483 | 685 | Model Group:KLF-01:1450670
1451484 | 767.5 | Model Group:KLF-01:1450670
1451485 | 685 | Model Group:KLF-01:1450670
1451486 | 965 | Model Group:KLF-01:1450670
1451487 | 785 | Model Group:KLF-01:1450670
1451488 | 685 | Model Group:KLF-01:1450670
1451489 | 767.5 | Model Group:KLF-01:1450670
1451490 | 767.5 | Model Group:KLF-01:1450670
1455972 | 1184.43 | Model Group:KLF-01:1450670
1455973 | 1184.43 | Model Group:KLF-01:1450670
1455974 | 50.5723 | Model Group:KLF-01:1450670
1453347 | 40 | Model Group:KLF-02:1453116
1453348 | 747.5 | Model Group:KLF-02:1453116
1453351 | 600 | Model Group:KLF-02:1453116
1453354 | 1740 | Model Group:KLF-02:1453116
1453357 | 400 | Model Group:KLF-02:1453116
1453360 | 900 | Model Group:KLF-02:1453116
1453363 | 1700.32 | Model Group:KLF-02:1453116
1453364 | 747.5 | Model Group:KLF-02:1453116
1453365 | 747.5 | Model Group:KLF-02:1453116
1453366 | 747.5 | Model Group:KLF-02:1453116
1453367 | 747.5 | Model Group:KLF-02:1453116
1453368 | 747.5 | Model Group:KLF-02:1453116
1453371 | 740 | Model Group:KLF-02:1453116
1453374 | 850.16 | Model Group:KLF-02:1453116
1453378 | 747.5 | Model Group:KLF-02:1453116
1453379 | 747.5 | Model Group:KLF-02:1453116
1453389 | 2525 | Model Group:KLF-02:1453116
1453390 | 2525 | Model Group:KLF-02:1453116
1453391 | 2525 | Model Group:KLF-02:1453116
1453392 | 2525 | Model Group:KLF-02:1453116
1453393 | 2525 | Model Group:KLF-02:1453116
1453394 | 2525 | Model Group:KLF-02:1453116
1453404 | 705 | Model Group:KLF-02:1453116
1453405 | 705 | Model Group:KLF-02:1453116
1453406 | 705 | Model Group:KLF-02:1453116
1453407 | 705 | Model Group:KLF-02:1453116
1453408 | 705 | Model Group:KLF-02:1453116
1453409 | 705 | Model Group:KLF-02:1453116
1453410 | 705 | Model Group:KLF-02:1453116
1453411 | 705 | Model Group:KLF-02:1453116
1453421 | 1427 | Model Group:KLF-02:1453116
1453422 | 1427 | Model Group:KLF-02:1453116
1453423 | 1427 | Model Group:KLF-02:1453116
1453424 | 1427 | Model Group:KLF-02:1453116
1453425 | 1427 | Model Group:KLF-02:1453116
1453426 | 1427 | Model Group:KLF-02:1453116
1453453 | 965 | Model Group:KLF-02:1453116
1453454 | 965 | Model Group:KLF-02:1453116
1453455 | 965 | Model Group:KLF-02:1453116
1453456 | 965 | Model Group:KLF-02:1453116
1453457 | 965 | Model Group:KLF-02:1453116
1453458 | 965 | Model Group:KLF-02:1453116
1453459 | 965 | Model Group:KLF-02:1453116
1453460 | 965 | Model Group:KLF-02:1453116
1453468 | 960 | Model Group:KLF-02:1453116
1453471 | 850.16 | Model Group:KLF-02:1453116
1453472 | 850.16 | Model Group:KLF-02:1453116
1453473 | 850.16 | Model Group:KLF-02:1453116
1453474 | 850.16 | Model Group:KLF-02:1453116
1453475 | 850.16 | Model Group:KLF-02:1453116
1453476 | 747.5 | Model Group:KLF-02:1453116
1453477 | 2525 | Model Group:KLF-02:1453116
1453478 | 705 | Model Group:KLF-02:1453116
1453479 | 1427 | Model Group:KLF-02:1453116
1453481 | 965 | Model Group:KLF-02:1453116
1453482 | 747.5 | Model Group:KLF-02:1453116
1453483 | 2525 | Model Group:KLF-02:1453116
1453484 | 705 | Model Group:KLF-02:1453116
1453485 | 965 | Model Group:KLF-02:1453116
1453486 | 1427 | Model Group:KLF-02:1453116
1453495 | 960 | Model Group:KLF-02:1453116
1453496 | 600 | Model Group:KLF-02:1453116
1453497 | 740 | Model Group:KLF-02:1453116
1453498 | 400 | Model Group:KLF-02:1453116
1453499 | 900 | Model Group:KLF-02:1453116
1453500 | 1740 | Model Group:KLF-02:1453116
1453501 | 1700.32 | Model Group:KLF-02:1453116
1453502 | 40 | Model Group:KLF-02:1453116
1453503 | 960 | Model Group:KLF-02:1453116
1453504 | 600 | Model Group:KLF-02:1453116
1453505 | 740 | Model Group:KLF-02:1453116
1453506 | 400 | Model Group:KLF-02:1453116
1453507 | 900 | Model Group:KLF-02:1453116
1453508 | 1740 | Model Group:KLF-02:1453116
1453509 | 1700.32 | Model Group:KLF-02:1453116
1453510 | 40 | Model Group:KLF-02:1453116
1453511 | 960 | Model Group:KLF-02:1453116
1453512 | 600 | Model Group:KLF-02:1453116
1453513 | 740 | Model Group:KLF-02:1453116
1453514 | 400 | Model Group:KLF-02:1453116
1453515 | 900 | Model Group:KLF-02:1453116
1453516 | 1740 | Model Group:KLF-02:1453116
1453517 | 1700.32 | Model Group:KLF-02:1453116
1453518 | 40 | Model Group:KLF-02:1453116
1453519 | 960 | Model Group:KLF-02:1453116
1453520 | 600 | Model Group:KLF-02:1453116
1453521 | 740 | Model Group:KLF-02:1453116
1453522 | 400 | Model Group:KLF-02:1453116
1453523 | 900 | Model Group:KLF-02:1453116
1453524 | 1740 | Model Group:KLF-02:1453116
1453525 | 1700.32 | Model Group:KLF-02:1453116
1453526 | 40 | Model Group:KLF-02:1453116
1453527 | 960 | Model Group:KLF-02:1453116
1453528 | 600 | Model Group:KLF-02:1453116
1453529 | 740 | Model Group:KLF-02:1453116
1453530 | 400 | Model Group:KLF-02:1453116
1453531 | 900 | Model Group:KLF-02:1453116
1453532 | 1740 | Model Group:KLF-02:1453116
1453533 | 1700.32 | Model Group:KLF-02:1453116
1453534 | 40 | Model Group:KLF-02:1453116
1658903 | 686.182 | Model Group:KLF-04:1658778
1658904 | 767.454 | Model Group:KLF-04:1658778
1658905 | 568.725 | Model Group:KLF-04:1658778
1658906 | 1527.5 | Model Group:KLF-04:1658778
1658909 | 1527.5 | Model Group:KLF-04:1658778
1658910 | 767.5 | Model Group:KLF-04:1658778
1658914 | 1700 | Model Group:KLF-04:1658778
1658915 | 585 | Model Group:KLF-04:1658778
1658919 | 1700 | Model Group:KLF-04:1658778
1658920 | 800 | Model Group:KLF-04:1658778
1658924 | 500 | Model Group:KLF-04:1658778
1658925 | 800 | Model Group:KLF-04:1658778
1658929 | 800 | Model Group:KLF-04:1658778
1658930 | 1700 | Model Group:KLF-04:1658778
1658934 | 1682.5 | Model Group:KLF-04:1658778
1658935 | 800 | Model Group:KLF-04:1658778
1658939 | 1250 | Model Group:KLF-04:1658778
1658943 | 601.749 | Model Group:KLF-04:1658778
1658944 | 568.725 | Model Group:KLF-04:1658778
1658945 | 767.5 | Model Group:KLF-04:1658778
1658946 | 767.5 | Model Group:KLF-04:1658778
1658947 | 767.5 | Model Group:KLF-04:1658778
1658948 | 767.5 | Model Group:KLF-04:1658778
1658949 | 837.5 | Model Group:KLF-04:1658778
1658950 | 767.454 | Model Group:KLF-04:1658778
1658951 | 767.454 | Model Group:KLF-04:1658778
1658952 | 585 | Model Group:KLF-04:1658778
1658953 | 1700 | Model Group:KLF-04:1658778
1658954 | 500 | Model Group:KLF-04:1658778
1658955 | 800 | Model Group:KLF-04:1658778
1658956 | 1682.5 | Model Group:KLF-04:1658778
1658957 | 1250 | Model Group:KLF-04:1658778
1658958 | 601.749 | Model Group:KLF-04:1658778
1658962 | 500 | Model Group:KLF-04:1658778
1658963 | 800 | Model Group:KLF-04:1658778
1658964 | 800 | Model Group:KLF-04:1658778
1658968 | 1250 | Model Group:KLF-04:1658778
1658969 | 782.5 | Model Group:KLF-04:1658778
1658970 | 782.5 | Model Group:KLF-04:1658778
1658974 | 1098.25 | Model Group:KLF-04:1658778
1658975 | 1098.25 | Model Group:KLF-04:1658778
1658976 | 767.5 | Model Group:KLF-04:1658778
1658977 | 767.5 | Model Group:KLF-04:1658778
1658984 | 585 | Model Group:KLF-04:1658778
1658985 | 686.182 | Model Group:KLF-04:1658778
1658986 | 686.182 | Model Group:KLF-04:1658778
1658987 | 1527.5 | Model Group:KLF-04:1658778
1658988 | 1527.5 | Model Group:KLF-04:1658778
1658989 | 767.454 | Model Group:KLF-04:1658778
1658990 | 601.749 | Model Group:KLF-04:1658778
1658991 | 1098.25 | Model Group:KLF-04:1658778
1658992 | 568.725 | Model Group:KLF-04:1658778
1658993 | 1527.5 | Model Group:KLF-04:1658778
1658994 | 1527.5 | Model Group:KLF-04:1658778
1658995 | 1527.5 | Model Group:KLF-04:1658778
1658996 | 1527.5 | Model Group:KLF-04:1658778
1658997 | 1527.5 | Model Group:KLF-04:1658778
1658998 | 1527.5 | Model Group:KLF-04:1658778
1660894 | 40 | Model Group:KLF-03:1660694
1660895 | 947.5 | Model Group:KLF-03:1660694
1660898 | 600 | Model Group:KLF-03:1660694
1660901 | 380 | Model Group:KLF-03:1660694
1660904 | 400 | Model Group:KLF-03:1660694
1660907 | 900 | Model Group:KLF-03:1660694
1660910 | 415.479 | Model Group:KLF-03:1660694
1660913 | 740 | Model Group:KLF-03:1660694
1660916 | 850.16 | Model Group:KLF-03:1660694
1660942 | 965 | Model Group:KLF-03:1660694
1660943 | 965 | Model Group:KLF-03:1660694
1660944 | 965 | Model Group:KLF-03:1660694
1660945 | 965 | Model Group:KLF-03:1660694
1660946 | 965 | Model Group:KLF-03:1660694
1660947 | 965 | Model Group:KLF-03:1660694
1660952 | 960 | Model Group:KLF-03:1660694
1660955 | 850.16 | Model Group:KLF-03:1660694
1660956 | 850.16 | Model Group:KLF-03:1660694
1660958 | 965 | Model Group:KLF-03:1660694
1660959 | 965 | Model Group:KLF-03:1660694
1660960 | 680 | Model Group:KLF-03:1660694
1660969 | 960 | Model Group:KLF-03:1660694
1660970 | 600 | Model Group:KLF-03:1660694
1660971 | 740 | Model Group:KLF-03:1660694
1660972 | 400 | Model Group:KLF-03:1660694
1660973 | 900 | Model Group:KLF-03:1660694
1660974 | 1360 | Model Group:KLF-03:1660694
1660975 | 1284.84 | Model Group:KLF-03:1660694
1660976 | 40 | Model Group:KLF-03:1660694
1660977 | 960 | Model Group:KLF-03:1660694
1660978 | 600 | Model Group:KLF-03:1660694
1660979 | 740 | Model Group:KLF-03:1660694
1660980 | 400 | Model Group:KLF-03:1660694
1660981 | 900 | Model Group:KLF-03:1660694
1660982 | 1284.84 | Model Group:KLF-03:1660694
1660983 | 40 | Model Group:KLF-03:1660694
1660996 | 680 | Model Group:KLF-03:1660694
1660997 | 1141.18 | Model Group:KLF-03:1660694
1661008 | 1141.18 | Model Group:KLF-03:1660694
1661009 | 947.5 | Model Group:KLF-03:1660694
1661016 | 1284.84 | Model Group:KLF-03:1660694
1661018 | 415.479 | Model Group:KLF-03:1660694
1661019 | 415.479 | Model Group:KLF-03:1660694
1661026 | 1360 | Model Group:KLF-03:1660694
1661028 | 380 | Model Group:KLF-03:1660694
1661029 | 1158.68 | Model Group:KLF-03:1660694
1661030 | 680 | Model Group:KLF-03:1660694
1661031 | 965 | Model Group:KLF-03:1660694
1661032 | 947.5 | Model Group:KLF-03:1660694
1661033 | 680 | Model Group:KLF-03:1660694
1661034 | 1141.18 | Model Group:KLF-03:1660694
1661035 | 947.5 | Model Group:KLF-03:1660694
1661036 | 680 | Model Group:KLF-03:1660694
1661037 | 1141.18 | Model Group:KLF-03:1660694
1661038 | 947.5 | Model Group:KLF-03:1660694
1661039 | 680 | Model Group:KLF-03:1660694
1661040 | 1141.18 | Model Group:KLF-03:1660694
1661041 | 947.5 | Model Group:KLF-03:1660694
1661042 | 680 | Model Group:KLF-03:1660694
1661043 | 1141.18 | Model Group:KLF-03:1660694
1661044 | 680 | Model Group:KLF-03:1660694
1661045 | 680 | Model Group:KLF-03:1660694
1661046 | 947.5 | Model Group:KLF-03:1660694
1661047 | 680 | Model Group:KLF-03:1660694
1661048 | 1141.18 | Model Group:KLF-03:1660694
1661049 | 850.16 | Model Group:KLF-03:1660694
1661050 | 850.16 | Model Group:KLF-03:1660694
1661051 | 947.5 | Model Group:KLF-03:1660694
1661052 | 947.5 | Model Group:KLF-03:1660694
1661053 | 1360 | Model Group:KLF-03:1660694
1661054 | 380 | Model Group:KLF-03:1660694
1661055 | 960 | Model Group:KLF-03:1660694
1661056 | 600 | Model Group:KLF-03:1660694
1661057 | 740 | Model Group:KLF-03:1660694
1661058 | 400 | Model Group:KLF-03:1660694
1661059 | 900 | Model Group:KLF-03:1660694
1661060 | 1360 | Model Group:KLF-03:1660694
1661061 | 1284.84 | Model Group:KLF-03:1660694
1661062 | 40 | Model Group:KLF-03:1660694
1661063 | 415.479 | Model Group:KLF-03:1660694
1661064 | 380 | Model Group:KLF-03:1660694
1661065 | 740 | Model Group:KLF-03:1660694
1661066 | 1360 | Model Group:KLF-03:1660694
1661067 | 1284.84 | Model Group:KLF-03:1660694
1661068 | 57.5 | Model Group:KLF-03:1660694
1888007 | 965 | Model Group:KLF-03:1660694
1888045 | 965 | Model Group:KLF-03:1660694
1888279 | 397.5 | Model Group:KLF-03:1660694
1888280 | 415.479 | Model Group:KLF-03:1660694
1888281 | 900 | Model Group:KLF-03:1660694
1888282 | 400 | Model Group:KLF-03:1660694

# IfcOpeningElement: Opening (424)
Name | In
SEIN - 008 | Katusekorrus | AR_IFC_SEINAD - Phase Created: Existing
SEIN - 008 | Katusekorrus | AR_IFC_SEINAD - Phase Created: Existing; 01.Nimetus: Ol.olev liftišahti sein; 02.Materjal: Silikaattellis; 03.Kategooria / tüüp: -; 04.Tulepüsivus: EI-60; 05.Asukoha info: Exterior; 06.Kandevelementide eristatud: bearing; 07.Helipidavus: -; 06.Soojusläbivus: -
SEIN - 006 | Katusekorrus | AR_IFC_SEINAD - Phase Created: Existing
2 x SEIN - 002 | 4 korrus | AR_IFC_SEINAD - Phase Created: Existing; 01.Nimetus: Sisesein; 02.Materjal: Silikaattellis; 03.Kategooria / tüüp: SS-1; 04.Tulepüsivus: -; 05.Asukoha info: Interior; 06.Kandevelementide eristatud: bearing; 07.Helipidavus: 48dB; 06.Soojusläbivus: -
2 x SEIN - 002 | 4 korrus | AR_IFC_SEINAD - Phase Created: Existing; 01.Nimetus: Sisesein; 02.Materjal: Silikaattellis; 03.Kategooria / tüüp: SS-1; 04.Tulepüsivus: EI-60; 05.Asukoha info: Interior; 06.Kandevelementide eristatud: bearing; 07.Helipidavus: 48dB; 06.Soojusläbivus: -
Ühepoolsed:SU-02:1746923:1 | 4 korrus
SEIN - 003 | 4 korrus | AR_IFC_SEINAD - Phase Created: Existing; 01.Nimetus: Välissein; 02.Materjal: Silikaattellis; 03.Kategooria / tüüp: VS-1; 04.Tulepüsivus: -; 05.Asukoha info: Exterior; 06.Kandevelementide eristatud: bearing; 07.Helipidavus: 56dB; 06.Soojusläbivus: 0,72W/m2K
SEIN - 003 | 4 korrus | AR_IFC_SEINAD - Phase Created: Existing; 01.Nimetus: Välissein; 02.Materjal: Silikaattellis; 03.Kategooria / tüüp: VS-1; 04.Tulepüsivus: R-60; 05.Asukoha info: Exterior; 06.Kandevelementide eristatud: bearing; 07.Helipidavus: 56dB; 06.Soojusläbivus: 0,72W/m2K
SEIN - 006 | 4 korrus | AR_IFC_SEINAD - Phase Created: Existing; 01.Nimetus: Sisesein; 02.Materjal: Silikaattellis; 03.Kategooria / tüüp: SS-1; 04.Tulepüsivus: -; 05.Asukoha info: Interior; 06.Kandevelementide eristatud: bearing; 07.Helipidavus: 48dB; 06.Soojusläbivus: -
SEIN - 006 | 2 korrus | AR_IFC_SEINAD - Phase Created: Existing; 01.Nimetus: Ol.olev liftišahti sein; 02.Materjal: Metall; 03.Kategooria / tüüp: -; 04.Tulepüsivus: -; 05.Asukoha info: Exterior; 06.Kandevelementide eristatud: nonbearing; 07.Helipidavus: -; 06.Soojusläbivus: -
SEIN - 008 | 2 korrus | AR_IFC_SEINAD - Phase Created: Existing; 01.Nimetus: Ol.olev liftišahti sein; 02.Materjal: Metall; 03.Kategooria / tüüp: -; 04.Tulepüsivus: -; 05.Asukoha info: Exterior; 06.Kandevelementide eristatud: nonbearing; 07.Helipidavus: -; 06.Soojusläbivus: -
SEIN - 007 | 2 korrus | AR_IFC_SEINAD - Phase Created: Existing; 01.Nimetus: Ol.olev liftišahti sein; 02.Materjal: Metall; 03.Kategooria / tüüp: -; 04.Tulepüsivus: -; 05.Asukoha info: Exterior; 06.Kandevelementide eristatud: nonbearing; 07.Helipidavus: -; 06.Soojusläbivus: -
2 x SEIN - 003 | 1 korrus | AR_IFC_SEINAD - Phase Created: Existing; 01.Nimetus: Sisesein; 02.Materjal: Silikaattellis; 03.Kategooria / tüüp: SS-1; 04.Tulepüsivus: -; 05.Asukoha info: Interior; 06.Kandevelementide eristatud: bearing; 07.Helipidavus: 48dB; 06.Soojusläbivus: -
2 x SEIN - 006 | Vundament | AR_IFC_SEINAD - Phase Created: Existing; 01.Nimetus: Välissein; 02.Materjal: Silikaattellis; 03.Kategooria / tüüp: VS-1; 04.Tulepüsivus: R-60; 05.Asukoha info: Exterior; 06.Kandevelementide eristatud: bearing; 07.Helipidavus: 56dB; 06.Soojusläbivus: 0,72W/m2K
SEIN - 010 | Vundament | AR_IFC_SEINAD - Phase Created: Existing; 01.Nimetus: Välissein; 02.Materjal: Silikaattellis; 03.Kategooria / tüüp: VS-1; 04.Tulepüsivus: R-60; 05.Asukoha info: Exterior; 06.Kandevelementide eristatud: bearing; 07.Helipidavus: 56dB; 06.Soojusläbivus: 0,72W/m2K
SEIN - 001 | 1 korrus | AR_IFC_SEINAD - Phase Created: Existing; 01.Nimetus: Välissein; 02.Materjal: Silikaattellis; 03.Kategooria / tüüp: VS-2; 04.Tulepüsivus: REI-60; 05.Asukoha info: Exterior; 06.Kandevelementide eristatud: bearing; 07.Helipidavus: 56dB; 06.Soojusläbivus: 0,15W/m2K
SEIN - 001 | 1 korrus | AR_IFC_SEINAD - Phase Created: Existing; 01.Nimetus: Sisesein; 02.Materjal: Silikaattellis; 03.Kategooria / tüüp: SS-1; 04.Tulepüsivus: EI-60; 05.Asukoha info: Interior; 06.Kandevelementide eristatud: bearing; 07.Helipidavus: 48dB; 06.Soojusläbivus: -
3 x SEIN - 002 | 1 korrus | AR_IFC_SEINAD - Phase Created: Existing; 01.Nimetus: Sisesein; 02.Materjal: Silikaattellis; 03.Kategooria / tüüp: SS-1; 04.Tulepüsivus: REI-240; 05.Asukoha info: Interior; 06.Kandevelementide eristatud: bearing; 07.Helipidavus: 52dB; 06.Soojusläbivus: -
SEIN - 001 | 1 korrus | AR_IFC_SEINAD - Phase Created: Existing; 01.Nimetus: Sisesein; 02.Materjal: Silikaattellis; 03.Kategooria / tüüp: SS-1; 04.Tulepüsivus: -; 05.Asukoha info: Interior; 06.Kandevelementide eristatud: bearing; 07.Helipidavus: 48dB; 06.Soojusläbivus: -
lifti aken:liftiaken 2:1674918:1 | uus 3 korrus
2 x SEIN - 004 | 1 korrus | AR_IFC_SEINAD - Phase Created: Existing; 01.Nimetus: Välissein; 02.Materjal: Silikaattellis; 03.Kategooria / tüüp: VS-1; 04.Tulepüsivus: R-60; 05.Asukoha info: Exterior; 06.Kandevelementide eristatud: bearing; 07.Helipidavus: 56dB; 06.Soojusläbivus: 0,72W/m2K
SEIN - 001 | 2 korrus | AR_IFC_SEINAD - Phase Created: Existing; 01.Nimetus: Välissein; 02.Materjal: Silikaattellis; 03.Kategooria / tüüp: VS-2; 04.Tulepüsivus: REI-60; 05.Asukoha info: Exterior; 06.Kandevelementide eristatud: bearing; 07.Helipidavus: 56dB; 06.Soojusläbivus: 0,15W/m2K
SEIN - 003 | 2 korrus | AR_IFC_SEINAD - Phase Created: Existing; 01.Nimetus: Välissein; 02.Materjal: Silikaattellis; 03.Kategooria / tüüp: VS-1; 04.Tulepüsivus: R-60; 05.Asukoha info: Exterior; 06.Kandevelementide eristatud: bearing; 07.Helipidavus: 56dB; 06.Soojusläbivus: 0,72W/m2K
8 x SEIN - 002 | 2 korrus | AR_IFC_SEINAD - Phase Created: Existing; 01.Nimetus: Sisesein; 02.Materjal: Silikaattellis; 03.Kategooria / tüüp: SS-1; 04.Tulepüsivus: REI-240; 05.Asukoha info: Interior; 06.Kandevelementide eristatud: bearing; 07.Helipidavus: 52dB; 06.Soojusläbivus: -
2 x SEIN - 002 | 2 korrus | AR_IFC_SEINAD - Phase Created: Existing; 01.Nimetus: Sisesein; 02.Materjal: Silikaattellis; 03.Kategooria / tüüp: SS-1; 04.Tulepüsivus: EI-60; 05.Asukoha info: Interior; 06.Kandevelementide eristatud: bearing; 07.Helipidavus: 48dB; 06.Soojusläbivus: -
lifti aken:liftiaken 2:1561275:1 | uus 3 korrus
2 x SEIN - 001 | 2 korrus | AR_IFC_SEINAD - Phase Created: Existing; 01.Nimetus: Sisesein; 02.Materjal: Silikaattellis; 03.Kategooria / tüüp: SS-1; 04.Tulepüsivus: EI-60; 05.Asukoha info: Interior; 06.Kandevelementide eristatud: bearing; 07.Helipidavus: 48dB; 06.Soojusläbivus: -
2 x SEIN - 004 | 2 korrus | AR_IFC_SEINAD - Phase Created: Existing; 01.Nimetus: Välissein; 02.Materjal: Silikaattellis; 03.Kategooria / tüüp: VS-1; 04.Tulepüsivus: R-60; 05.Asukoha info: Exterior; 06.Kandevelementide eristatud: bearing; 07.Helipidavus: 56dB; 06.Soojusläbivus: 0,72W/m2K
SEIN - 001 | 3 korrus | AR_IFC_SEINAD - Phase Created: Existing; 01.Nimetus: Välissein; 02.Materjal: Silikaattellis; 03.Kategooria / tüüp: VS-2; 04.Tulepüsivus: REI-60; 05.Asukoha info: Exterior; 06.Kandevelementide eristatud: bearing; 07.Helipidavus: 56dB; 06.Soojusläbivus: 0,15W/m2K
2 x SEIN - 003 | 3 korrus | AR_IFC_SEINAD - Phase Created: Existing; 01.Nimetus: Välissein; 02.Materjal: Silikaattellis; 03.Kategooria / tüüp: VS-1; 04.Tulepüsivus: R-60; 05.Asukoha info: Exterior; 06.Kandevelementide eristatud: bearing; 07.Helipidavus: 56dB; 06.Soojusläbivus: 0,72W/m2K
SEIN - 003 | 3 korrus | AR_IFC_SEINAD - Phase Created: Existing; 01.Nimetus: Sisesein; 02.Materjal: Silikaattellis; 03.Kategooria / tüüp: SS-1; 04.Tulepüsivus: EI-60; 05.Asukoha info: Interior; 06.Kandevelementide eristatud: bearing; 07.Helipidavus: 48dB; 06.Soojusläbivus: -
2 x SEIN - 002 | 3 korrus | AR_IFC_SEINAD - Phase Created: Existing; 01.Nimetus: Sisesein; 02.Materjal: Silikaattellis; 03.Kategooria / tüüp: SS-1; 04.Tulepüsivus: EI-60; 05.Asukoha info: Interior; 06.Kandevelementide eristatud: bearing; 07.Helipidavus: 48dB; 06.Soojusläbivus: -
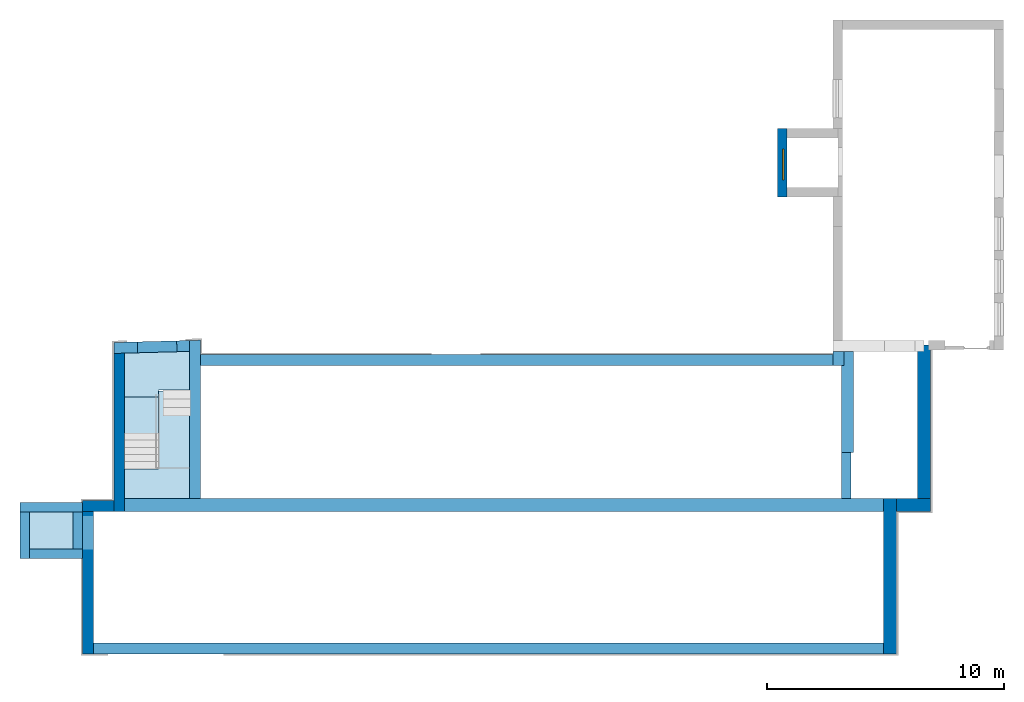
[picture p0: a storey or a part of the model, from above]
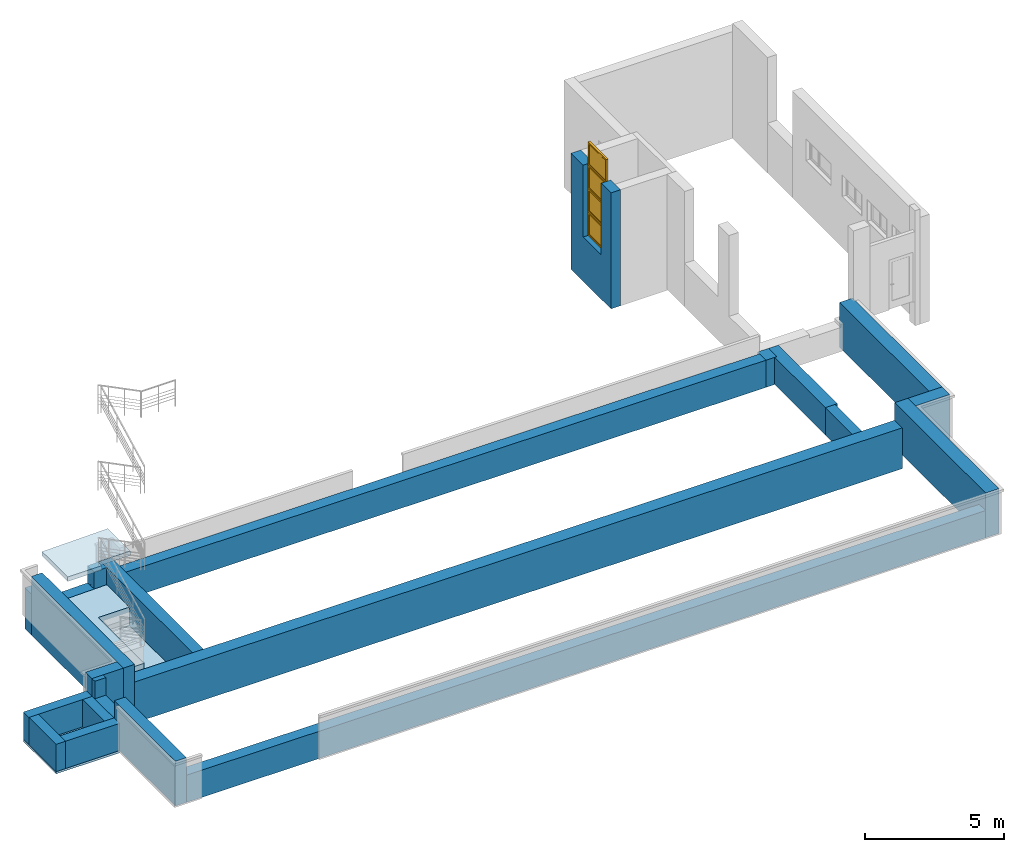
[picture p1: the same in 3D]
Properties of the parts of a building model (IFC2X3), part 3 of 5

# IfcOpeningElement: Opening (424)
Name | In
2 x SEIN - 004 | 3 korrus | AR_IFC_SEINAD - Phase Created: Existing; 01.Nimetus: Välissein; 02.Materjal: Silikaattellis; 03.Kategooria / tüüp: VS-1; 04.Tulepüsivus: R-60; 05.Asukoha info: Exterior; 06.Kandevelementide eristatud: bearing; 07.Helipidavus: 56dB; 06.Soojusläbivus: 0,72W/m2K
2 x SEIN - 001 | 3 korrus | AR_IFC_SEINAD - Phase Created: Existing; 01.Nimetus: Sisesein; 02.Materjal: Silikaattellis; 03.Kategooria / tüüp: SS-1; 04.Tulepüsivus: EI-60; 05.Asukoha info: Interior; 06.Kandevelementide eristatud: bearing; 07.Helipidavus: 48dB; 06.Soojusläbivus: -
lifti aken:liftiaken 2:1674826:1 | uus 2 korrus
2 x SEIN - 001 | 4 korrus | AR_IFC_SEINAD - Phase Created: Existing; 01.Nimetus: Välissein; 02.Materjal: Silikaattellis; 03.Kategooria / tüüp: VS-2; 04.Tulepüsivus: REI-60; 05.Asukoha info: Exterior; 06.Kandevelementide eristatud: bearing; 07.Helipidavus: 56dB; 06.Soojusläbivus: 0,15W/m2K
SEIN - 001 | 4 korrus | AR_IFC_SEINAD - Phase Created: Existing; 01.Nimetus: Sisesein; 02.Materjal: Silikaattellis; 03.Kategooria / tüüp: SS-1; 04.Tulepüsivus: EI-60; 05.Asukoha info: Interior; 06.Kandevelementide eristatud: bearing; 07.Helipidavus: 48dB; 06.Soojusläbivus: -
SEIN - 015 | Vundament | AR_IFC_SEINAD - Phase Created: Existing; 01.Nimetus: Välissein; 02.Materjal: Silikaattellis; 03.Kategooria / tüüp: VS-1; 04.Tulepüsivus: R-60; 05.Asukoha info: Exterior; 06.Kandevelementide eristatud: bearing; 07.Helipidavus: 56dB; 06.Soojusläbivus: 0,72W/m2K
SEIN - 002 | 1 korrus | AR_IFC_SEINAD - Phase Created: Existing; 01.Nimetus: Välissein; 02.Materjal: Silikaattellis; 03.Kategooria / tüüp: VS-2; 04.Tulepüsivus: REI-60; 05.Asukoha info: Exterior; 06.Kandevelementide eristatud: bearing; 07.Helipidavus: 56dB; 06.Soojusläbivus: 0,15W/m2K
SEIN - 001 | 1 korrus | AR_IFC_SEINAD - Phase Created: Existing; 01.Nimetus: Välissein; 02.Materjal: Silikaattellis; 03.Kategooria / tüüp: VS-1; 04.Tulepüsivus: R-60; 05.Asukoha info: Exterior; 06.Kandevelementide eristatud: bearing; 07.Helipidavus: 56dB; 06.Soojusläbivus: 0,72W/m2K
10 x SEIN - 002 | 1 korrus | AR_IFC_SEINAD - Phase Created: Existing; 01.Nimetus: Sisesein; 02.Materjal: Silikaattellis; 03.Kategooria / tüüp: SS-1; 04.Tulepüsivus: -; 05.Asukoha info: Interior; 06.Kandevelementide eristatud: bearing; 07.Helipidavus: 48dB; 06.Soojusläbivus: -
2 x SEIN - 003 | 1 korrus | AR_IFC_SEINAD - Phase Created: Existing; 01.Nimetus: Välissein; 02.Materjal: Silikaattellis; 03.Kategooria / tüüp: VS-2; 04.Tulepüsivus: REI-60; 05.Asukoha info: Exterior; 06.Kandevelementide eristatud: bearing; 07.Helipidavus: 56dB; 06.Soojusläbivus: 0,15W/m2K
4 x SEIN - 001 | 1 korrus | AR_IFC_SEINAD - Phase Created: Existing; 01.Nimetus: Välissein; 02.Materjal: Silikaattellis; 03.Kategooria / tüüp: VS-1; 04.Tulepüsivus: -; 05.Asukoha info: Exterior; 06.Kandevelementide eristatud: bearing; 07.Helipidavus: 56dB; 06.Soojusläbivus: 0,72W/m2K
lifti aken:liftiaken 2:1674848:1 | uus 2 korrus
SEIN - 003 | 2 korrus | AR_IFC_SEINAD - Phase Created: Existing; 01.Nimetus: Välissein; 02.Materjal: Silikaattellis; 03.Kategooria / tüüp: VS-1; 04.Tulepüsivus: -; 05.Asukoha info: Exterior; 06.Kandevelementide eristatud: bearing; 07.Helipidavus: 56dB; 06.Soojusläbivus: 0,72W/m2K
SEIN - 003 | 2 korrus | AR_IFC_SEINAD - Phase Created: Existing; 01.Nimetus: Sisesein; 02.Materjal: Silikaattellis; 03.Kategooria / tüüp: SS-1; 04.Tulepüsivus: EI-60; 05.Asukoha info: Interior; 06.Kandevelementide eristatud: bearing; 07.Helipidavus: 48dB; 06.Soojusläbivus: -
 | 2 korrus | AR_IFC_VAHELAED_PÕRANDAD - 01.Nimetus: Vahelagi; 02.Materjal: Õõnespaneel; 03.Kategooria / tüüp: VL-1; Phase Created: Existing
lifti aken:liftiaken 2:1674836:1 | uus 2 korrus
10 x SEIN - 001 | 2 korrus | AR_IFC_SEINAD - Phase Created: Existing; 01.Nimetus: Sisesein; 02.Materjal: Silikaattellis; 03.Kategooria / tüüp: SS-1; 04.Tulepüsivus: -; 05.Asukoha info: Interior; 06.Kandevelementide eristatud: bearing; 07.Helipidavus: 48dB; 06.Soojusläbivus: -
SEIN - 003 | 2 korrus | AR_IFC_SEINAD - Phase Created: Existing; 01.Nimetus: Sisesein; 02.Materjal: Silikaattellis; 03.Kategooria / tüüp: SS-1; 04.Tulepüsivus: -; 05.Asukoha info: Interior; 06.Kandevelementide eristatud: bearing; 07.Helipidavus: 48dB; 06.Soojusläbivus: -
SEIN - 005 | 2 korrus | AR_IFC_SEINAD - Phase Created: Existing; 01.Nimetus: Sisesein; 02.Materjal: Silikaattellis; 03.Kategooria / tüüp: SS-1; 04.Tulepüsivus: EI-60; 05.Asukoha info: Interior; 06.Kandevelementide eristatud: bearing; 07.Helipidavus: 48dB; 06.Soojusläbivus: -
2 x SEIN - 003 | 3 korrus | AR_IFC_SEINAD - Phase Created: Existing; 01.Nimetus: Välissein; 02.Materjal: Silikaattellis; 03.Kategooria / tüüp: VS-1; 04.Tulepüsivus: -; 05.Asukoha info: Exterior; 06.Kandevelementide eristatud: bearing; 07.Helipidavus: 56dB; 06.Soojusläbivus: 0,72W/m2K
lifti aken:liftiaken 2:1674783:1 | Vundament
SEIN - 003 | 3 korrus | AR_IFC_SEINAD - Phase Created: Existing; 01.Nimetus: Välissein; 02.Materjal: Silikaattellis; 03.Kategooria / tüüp: VS-2; 04.Tulepüsivus: REI-60; 05.Asukoha info: Exterior; 06.Kandevelementide eristatud: bearing; 07.Helipidavus: 56dB; 06.Soojusläbivus: 0,15W/m2K
2 x Basic Wall:VS-2.2_Juurdeehituse välissein:75447 | Vundament | AR_IFC_SEINAD - Phase Created: New Construction; 01.Nimetus: Välissein; 02.Materjal: Columbia kivi; 03.Kategooria / tüüp: VS-2.2; 04.Tulepüsivus: REI-60; 05.Asukoha info: Exterior; 06.Kandevelementide eristatud: bearing; 07.Helipidavus: 56dB; 06.Soojusläbivus: 0,15W/m2K
Basic Wall:SS-8_Bauroc sein niiske ja tava ruumide vahel:327654 | 1 korrus | AR_IFC_SEINAD - Phase Created: New Construction; 01.Nimetus: Sisesein; 02.Materjal: Kergplokk; 03.Kategooria / tüüp: SS-8; 04.Tulepüsivus: -; 05.Asukoha info: Interior; 06.Kandevelementide eristatud: nonbearing; 07.Helipidavus: 41dB; 06.Soojusläbivus: -
Basic Wall:SS-3_Kipssein tava ruumide vahel:327680 | 1 korrus | AR_IFC_SEINAD - Phase Created: New Construction; 01.Nimetus: Sisesein; 02.Materjal: Kips; 03.Kategooria / tüüp: SS-3; 04.Tulepüsivus: -; 05.Asukoha info: Interior; 06.Kandevelementide eristatud: nonbearing; 07.Helipidavus: 48dB; 06.Soojusläbivus: -
Basic Wall:SS-4_Kipssein tava ja niiske ruumi vahel:327681 | 1 korrus | AR_IFC_SEINAD - Phase Created: New Construction; 01.Nimetus: Sisesein; 02.Materjal: Kips; 03.Kategooria / tüüp: SS-4; 04.Tulepüsivus: -; 05.Asukoha info: Interior; 06.Kandevelementide eristatud: nonbearing; 07.Helipidavus: 48dB; 06.Soojusläbivus: -
Basic Wall:SS-3_Kipssein tava ruumide vahel:328809 | 1 korrus | AR_IFC_SEINAD - Phase Created: New Construction; 01.Nimetus: Sisesein; 02.Materjal: Kips; 03.Kategooria / tüüp: SS-3; 04.Tulepüsivus: -; 05.Asukoha info: Interior; 06.Kandevelementide eristatud: nonbearing; 07.Helipidavus: 48dB; 06.Soojusläbivus: -
lifti aken:liftiaken 2:1674811:1 | Vundament
lifti aken:liftiaken 2:1674798:1 | Vundament
lifti aken:liftiaken 2:1674678:1 | Vundament
Ühepoolsed:SU-20:1353896:1 | uus 1 korrus
Basic Roof:KL-2 .1_uus katus:384110:1 | uus Katus | AR_IFC_KATUSED - 01.Nimetus: Katuslagi; 02.Materjal: Õõnespaneel; 03.Kategooria / tüüp: KL-2.1; Phase Created: New Construction
fassaad3:fassaad3:402731:1 | uus Katus
trepi sein1:trepi sein1:411547:1 | 1 korrus
trepi sein1:trepi sein1:411547:2 | 1 korrus
trepi sein1:trepi sein1:411547:3 | 1 korrus
trepi sein1:trepi sein1:411547:4 | 1 korrus
trepi sein1:trepi sein1:411547:5 | 1 korrus
trepi sein1:trepi sein1:411547:6 | 1 korrus
trepi sein1:trepi sein1:411547:7 | 1 korrus
trepi sein1:trepi sein1:411547:8 | 1 korrus
trepi sein1:trepi sein1:411547:9 | 1 korrus
trepi sein1:trepi sein1:411547:10 | 1 korrus
trepi sein1:trepi sein1:411547:11 | 1 korrus
trepi sein1:trepi sein1:411547:12 | 1 korrus
trepi sein1:trepi sein1:411547:13 | 1 korrus
trepi sein1:trepi sein1:411547:14 | 1 korrus
trepi sein1:trepi sein1:411547:15 | 1 korrus
trepi sein1:trepi sein1:411547:16 | 1 korrus
trepi sein1:trepi sein1:411547:17 | 1 korrus
trepi sein1:trepi sein1:411547:18 | 1 korrus
trepi sein1:trepi sein1:411547:19 | 1 korrus
trepi sein1:trepi sein1:411547:20 | 1 korrus
trepi sein1:trepi sein1:411547:21 | 1 korrus
trepi sein1:trepi sein1:411547:22 | 1 korrus
trepi sein1:trepi sein1:411547:23 | 1 korrus
trepi sein1:trepi sein1:411547:24 | 1 korrus
trepi sein1:trepi sein1:411547:25 | 1 korrus
trepi sein1:trepi sein1:411547:26 | 1 korrus
trepi sein1:trepi sein1:411547:27 | 1 korrus
trepi sein1:trepi sein1:411547:28 | 1 korrus
trepi sein1:trepi sein1:411547:29 | 1 korrus
trepi sein1:trepi sein1:411547:30 | 1 korrus
trepi sein1:trepi sein1:411547:31 | 1 korrus
trepi sein1:trepi sein1:411547:32 | 1 korrus
trepi sein1:trepi sein1:411547:33 | 1 korrus
trepi sein1:trepi sein1:411547:34 | 1 korrus
trepi sein1:trepi sein1:411547:35 | 1 korrus
trepi sein1:trepi sein1:411547:36 | 1 korrus
trepi sein1:trepi sein1:411547:37 | 1 korrus
trepi sein1:trepi sein1:411547:38 | 1 korrus
trepi sein1:trepi sein1:411547:39 | 1 korrus
trepi sein1:trepi sein1:411547:40 | 1 korrus
trepi sein1:trepi sein1:411547:41 | 1 korrus
trepi sein1:trepi sein1:411547:42 | 1 korrus
trepi sein1:trepi sein1:411547:43 | 1 korrus
trepi sein1:trepi sein1:411547:44 | 1 korrus
trepi sein1:trepi sein1:411547:45 | 1 korrus
trepi sein1:trepi sein1:411547:46 | 1 korrus
trepi sein1:trepi sein1:411547:47 | 1 korrus
trepi sein1:trepi sein1:411547:48 | 1 korrus
trepi sein1:trepi sein1:411547:49 | 1 korrus
trepi sein1:trepi sein1:411547:50 | 1 korrus
trepi sein1:trepi sein1:411820:1 | 1 korrus
trepi sein1:trepi sein1:411820:2 | 1 korrus
trepi sein1:trepi sein1:411820:3 | 1 korrus
trepi sein1:trepi sein1:411820:4 | 1 korrus
trepi sein1:trepi sein1:411820:5 | 1 korrus
trepi sein1:trepi sein1:411820:6 | 1 korrus
trepi sein1:trepi sein1:411820:7 | 1 korrus
trepi sein1:trepi sein1:411820:8 | 1 korrus
trepi sein1:trepi sein1:411820:9 | 1 korrus
trepi sein1:trepi sein1:411820:10 | 1 korrus
trepi sein1:trepi sein1:411820:11 | 1 korrus
trepi sein1:trepi sein1:411820:12 | 1 korrus
trepi sein1:trepi sein1:411820:13 | 1 korrus
trepi sein1:trepi sein1:411820:14 | 1 korrus
trepi sein1:trepi sein1:411820:15 | 1 korrus
trepi sein1:trepi sein1:411820:16 | 1 korrus
trepi sein1:trepi sein1:411820:17 | 1 korrus
trepi sein1:trepi sein1:411820:18 | 1 korrus
trepi sein1:trepi sein1:411820:19 | 1 korrus
trepi sein1:trepi sein1:411820:20 | 1 korrus
trepi sein1:trepi sein1:411820:21 | 1 korrus
trepi sein1:trepi sein1:411820:22 | 1 korrus
trepi sein1:trepi sein1:411820:23 | 1 korrus
trepi sein1:trepi sein1:411820:24 | 1 korrus
trepi sein1:trepi sein1:411820:25 | 1 korrus
trepi sein1:trepi sein1:411820:26 | 1 korrus
trepi sein1:trepi sein1:411820:27 | 1 korrus
trepi sein1:trepi sein1:411820:28 | 1 korrus
trepi sein1:trepi sein1:411820:29 | 1 korrus
trepi sein1:trepi sein1:411820:30 | 1 korrus
trepi sein1:trepi sein1:411820:31 | 1 korrus
trepi sein1:trepi sein1:411820:32 | 1 korrus
trepi sein1:trepi sein1:411820:33 | 1 korrus
trepi sein1:trepi sein1:411820:34 | 1 korrus
trepi sein1:trepi sein1:411820:35 | 1 korrus
trepi sein1:trepi sein1:411820:36 | 1 korrus
trepi sein1:trepi sein1:411820:37 | 1 korrus
trepi sein1:trepi sein1:411820:38 | 1 korrus
trepi sein1:trepi sein1:411820:39 | 1 korrus
trepi sein1:trepi sein1:411820:40 | 1 korrus
trepi sein1:trepi sein1:411820:41 | 1 korrus
trepi sein1:trepi sein1:411820:42 | 1 korrus
trepi sein1:trepi sein1:411820:43 | 1 korrus
trepi sein1:trepi sein1:411820:44 | 1 korrus
trepi sein1:trepi sein1:411820:45 | 1 korrus
trepi sein1:trepi sein1:411820:46 | 1 korrus
trepi sein1:trepi sein1:411820:47 | 1 korrus
trepi sein1:trepi sein1:411820:48 | 1 korrus
trepi sein1:trepi sein1:411820:49 | 1 korrus
trepi sein1:trepi sein1:411820:50 | 1 korrus
Basic Wall:SS-3_Kipssein tava ruumide vahel:478667 | 1 korrus | AR_IFC_SEINAD - Phase Created: New Construction; 01.Nimetus: Sisesein; 02.Materjal: Kips; 03.Kategooria / tüüp: SS-3; 04.Tulepüsivus: -; 05.Asukoha info: Interior; 06.Kandevelementide eristatud: nonbearing; 07.Helipidavus: 48dB; 06.Soojusläbivus: -
Ventrestid:VR-02:1376210:1 | uus 3 korrus
Ühepoolsed:VU-04:1257104:1 | 1 korrus
Ühepoolsed:VU-04:1257071:1 | 1 korrus
Kahepoolsed:SU-25:1455512:1 | uus 1 korrus
Ühepoolsed:SU-01:1080922:1 | 4 korrus
Ühepoolsed:SU-01.:1080916:1 | 4 korrus
2 x Basic Wall:SS-3_Kipssein tava ruumide vahel:497312 | uus 1 korrus | AR_IFC_SEINAD - Phase Created: New Construction; 01.Nimetus: Sisesein; 02.Materjal: Kips; 03.Kategooria / tüüp: SS-3; 04.Tulepüsivus: -; 05.Asukoha info: Interior; 06.Kandevelementide eristatud: nonbearing; 07.Helipidavus: 48dB; 06.Soojusläbivus: -
2 x Basic Wall:SS-3_Kipssein tava ruumide vahel:497384 | uus 1 korrus | AR_IFC_SEINAD - Phase Created: New Construction; 01.Nimetus: Sisesein; 02.Materjal: Kips; 03.Kategooria / tüüp: SS-3; 04.Tulepüsivus: -; 05.Asukoha info: Interior; 06.Kandevelementide eristatud: nonbearing; 07.Helipidavus: 48dB; 06.Soojusläbivus: -
2 x Basic Wall:SS-3_Kipssein tava ruumide vahel:497476 | uus 1 korrus | AR_IFC_SEINAD - Phase Created: New Construction; 01.Nimetus: Sisesein; 02.Materjal: Kips; 03.Kategooria / tüüp: SS-3; 04.Tulepüsivus: -; 05.Asukoha info: Interior; 06.Kandevelementide eristatud: nonbearing; 07.Helipidavus: 48dB; 06.Soojusläbivus: -
Basic Wall:SS-3_Kipssein tava ruumide vahel:497568 | uus 1 korrus | AR_IFC_SEINAD - Phase Created: New Construction; 01.Nimetus: Sisesein; 02.Materjal: Kips; 03.Kategooria / tüüp: SS-3; 04.Tulepüsivus: -; 05.Asukoha info: Interior; 06.Kandevelementide eristatud: nonbearing; 07.Helipidavus: 48dB; 06.Soojusläbivus: -
Basic Wall:SS-4_Kipssein tava ja niiske ruumi vahel:497887 | uus 1 korrus | AR_IFC_SEINAD - Phase Created: New Construction; 01.Nimetus: Sisesein; 02.Materjal: Kips; 03.Kategooria / tüüp: SS-4; 04.Tulepüsivus: -; 05.Asukoha info: Interior; 06.Kandevelementide eristatud: nonbearing; 07.Helipidavus: 48dB; 06.Soojusläbivus: -
Ühepoolsed:VU-04.:1010181:1 | uus Katus
Ühepoolsed:SU-05:1445593:1 | uus 3 korrus
Ühepoolsed:VU-06:1339736:1 | 1 korrus
Ühepoolsed:VU-05:1339524:1 | 1 korrus
Ühepoolsed:SU-02:934430:1 | uus 3 korrus
Kahepoolsed:SU-14.:933230:1 | uus 3 korrus
Ühepoolsed:SU-05:1445577:1 | uus 2 korrus
Ühepoolsed:SU-05:900334:1 | uus 1 korrus
Ventrestid:VR-01:1380497:1 | Katusekorrus
Ühepoolsed:VU-04:957127:1 | Katusekorrus
Ühepoolsed:VU-04:957025:1 | Katusekorrus
Ühepoolsed:SU-06:1317124:1 | 3 korrus
Ühepoolsed:SU-05:563013:1 | 4 korrus
Ühepoolsed:SU-05:563011:1 | 4 korrus
Ühepoolsed:SU-05:562881:1 | 3 korrus
Ühepoolsed:SU-05:562879:1 | 3 korrus
Ühepoolsed:SU-05:519622:1 | 2 korrus
Ühepoolsed:SU-05:519475:1 | 2 korrus
Ühepoolsed:SU-09:1119743:1 | 2 korrus
Ühepoolsed:SU-08:499100:1 | uus 1 korrus
Ühepoolsed:SU-06:499061:1 | uus 1 korrus
Ühepoolsed2:SU24_ülemine:1445358:1 | uus 1 korrus
Kahepoolsed:SU-24:1438414:1 | uus 1 korrus
Ühepoolsed:SU-06:499027:1 | uus 1 korrus
Ühepoolsed:SU-02.:1316792:1 | uus 1 korrus
Ühepoolsed:SU-02:900544:1 | uus 1 korrus
Ühepoolsed:SU-02:900490:1 | uus 1 korrus
Ühepoolsed:SU-02:498907:1 | uus 1 korrus
Kahepoolsed:SU-14:488211:1 | 1 korrus
Kahepoolsed:SU-14.:922316:1 | uus 2 korrus
Kahepoolsed:SU-13:497043:1 | uus 1 korrus
4 x Basic Wall:VS-2.2_Juurdeehituse välissein:381772 | Vundament
Basic Wall:VS-2.2_Juurdeehituse välissein:377004 | Vundament
Basic Wall:SS-4_Kipssein tava ja niiske ruumi vahel:927330 | uus 2 korrus | AR_IFC_SEINAD - Phase Created: New Construction; 01.Nimetus: Sisesein; 02.Materjal: Kips; 03.Kategooria / tüüp: SS-4; 04.Tulepüsivus: -; 05.Asukoha info: Interior; 06.Kandevelementide eristatud: nonbearing; 07.Helipidavus: 48dB; 06.Soojusläbivus: -
Ühepoolsed:1000x2200_välisuks klaasiga:408534:1 | uus 1 korrus
Ühepoolsed:SU-05:342365:1 | 1 korrus
Ühepoolsed:SU-05.:342141:1 | 1 korrus
Ühepoolsed:SU-08:342066:1 | 1 korrus
Ühepoolsed:SU-05.:341906:1 | 1 korrus
2 x  | Katusekorrus | AR_IFC_VAHELAED_PÕRANDAD - 01.Nimetus: Vahelagi; 02.Materjal: Õõnespaneel; 03.Kategooria / tüüp: VL-2; Phase Created: New Construction
Basic Wall:SS-4_Kipssein tava ja niiske ruumi vahel:1005804 | uus 3 korrus | AR_IFC_SEINAD - Phase Created: New Construction; 01.Nimetus: Sisesein; 02.Materjal: Kips; 03.Kategooria / tüüp: SS-4; 04.Tulepüsivus: -; 05.Asukoha info: Interior; 06.Kandevelementide eristatud: nonbearing; 07.Helipidavus: 48dB; 06.Soojusläbivus: -
Ühepoolsed:SU-07:341632:1 | 1 korrus
Basic Wall:SS-3_Kipssein tava ruumide vahel:1080889 | 4 korrus | AR_IFC_SEINAD - Phase Created: New Construction; 01.Nimetus: Sisesein; 02.Materjal: Kips; 03.Kategooria / tüüp: SS-3; 04.Tulepüsivus: -; 05.Asukoha info: Interior; 06.Kandevelementide eristatud: nonbearing; 07.Helipidavus: 48dB; 06.Soojusläbivus: -
Kahepoolsed:SU-21:1268425:1 | 1 korrus
Ühepoolsed:SU-05.:341983:1 | 1 korrus
Ühepoolsed:SU-08.:342205:1 | 1 korrus
Basic Wall:SS-6_Šahti sein EI-60:1306080 | uus 1 korrus | AR_IFC_SEINAD - Phase Created: New Construction; 01.Nimetus: Sisesein; 02.Materjal: Columbia kivi; 03.Kategooria / tüüp: SS-6; 04.Tulepüsivus: EI-60; 05.Asukoha info: Interior; 06.Kandevelementide eristatud: nonbearing; 07.Helipidavus: 48dB; 06.Soojusläbivus: -
Basic Wall:SS-6_Šahti sein EI-60:1306081 | uus 1 korrus | AR_IFC_SEINAD - Phase Created: New Construction; 01.Nimetus: Sisesein; 02.Materjal: Columbia kivi; 03.Kategooria / tüüp: SS-6; 04.Tulepüsivus: EI-60; 05.Asukoha info: Interior; 06.Kandevelementide eristatud: nonbearing; 07.Helipidavus: 48dB; 06.Soojusläbivus: -
Ühepoolsed:SU-05:342177:1 | 1 korrus
Ühepoolsed:SU-06.:327227:1 | 1 korrus
Ühepoolsed:SU-05.:327042:1 | 1 korrus
Lükanduks:SU-18:340992:1 | 1 korrus
Lükanduks:SU-18.:337993:1 | 1 korrus
Lükanduks:SU-18:340810:1 | 1 korrus
Ühepoolsed:SU-02:323160:1 | 1 korrus
Ühepoolsed:1000x2200_välisuks klaasiga:394254:1 | Vundament
SEIN - 008 | 4 korrus
Aken ukse kohal:SU-1500_aken:1421983:1 | 4 korrus
Kahepoolsed:SU-17:1421984:1 | 4 korrus
Ühepoolsed:SU17_ülemine:1421985:1 | 4 korrus
Ühepoolsed:SU-02:239855:1 | 4 korrus
Kahepoolsed:SU-11:239854:1 | 4 korrus
Ühepoolsed:SU-02.:239851:1 | 4 korrus
SEIN - 003 | 4 korrus
9 x SEIN - 001 | 4 korrus
9 x SEIN - 005 | 2 korrus
9 x SEIN - 005 | 4 korrus
SEIN - 008 | 3 korrus
SEIN - 003 | 3 korrus
10 x SEIN - 001 | 3 korrus
Aken ukse kohal:SU-1500_aken:1421921:1 | 3 korrus
Kahepoolsed:SU-17:1421922:1 | 3 korrus
Ühepoolsed:SU17_ülemine:1421923:1 | 3 korrus
Ühepoolsed:SU-03:572865:1 | 3 korrus
Ühepoolsed:SU-03.:572708:1 | 3 korrus
Basic Wall:Juurdeehituse välissein_soojustuseta:1556599 | Vundament | AR_IFC_SEINAD - Phase Created: New Construction
Basic Wall:Juurdeehituse välissein_soojustuseta:1558816 | uus 2 korrus | AR_IFC_SEINAD - Phase Created: New Construction
Basic Wall:VS-2.2_Juurdeehituse välissein:1559791 | uus 2 korrus | AR_IFC_SEINAD - Phase Created: New Construction; 01.Nimetus: Välissein; 02.Materjal: Columbia kivi; 03.Kategooria / tüüp: VS-2.2; 04.Tulepüsivus: REI-60; 05.Asukoha info: Exterior; 06.Kandevelementide eristatud: bearing; 07.Helipidavus: 56dB; 06.Soojusläbivus: 0,15W/m2K
Basic Wall:VS-2.2_Juurdeehituse välissein:1559835 | uus 3 korrus | AR_IFC_SEINAD - Phase Created: New Construction; 01.Nimetus: Välissein; 02.Materjal: Columbia kivi; 03.Kategooria / tüüp: VS-2.2; 04.Tulepüsivus: REI-60; 05.Asukoha info: Exterior; 06.Kandevelementide eristatud: bearing; 07.Helipidavus: 56dB; 06.Soojusläbivus: 0,15W/m2K
Basic Wall:Juurdeehituse välissein_soojustuseta:1561929 | uus 3 korrus | AR_IFC_SEINAD - Phase Created: New Construction
Ühepoolsed:SU-03.:572231:1 | 3 korrus
Ühepoolsed:SU-03:571746:1 | 3 korrus
Ühepoolsed:SU-03:571676:1 | 3 korrus
Ühepoolsed:SU-03.:571561:1 | 3 korrus
Kahepoolsed:SU-11:239619:1 | 3 korrus
9 x SEIN - 005 | 3 korrus
2 x SEIN - 008 | 2 korrus
SEIN - 003 | 2 korrus
10 x SEIN - 001 | 2 korrus
SEIN - 008 | Katusekorrus
SEIN - 004 | 4 korrus
SEIN - 006 | 2 korrus
SEIN - 007 | 2 korrus
Ühepoolsed:SU-02.:1077138:1 | 1 korrus
Kahepoolsed:SU-11:1244838:1 | 1 korrus
Kahepoolsed:VU-02:239211:1 | 1 korrus
Ühepoolsed:SU-04:325530:1 | 1 korrus
Kahepoolsed:SU-11:1247419:1 | 2 korrus
Kahepoolsed:SU-11:239467:1 | 2 korrus
Ühepoolsed:SU-03.:556845:1 | 2 korrus
Ühepoolsed:SU-03:557605:1 | 2 korrus
Ühepoolsed:SU-02:557840:1 | 2 korrus
Ühepoolsed:SU-03.:1119601:1 | 2 korrus
Ühepoolsed:SU-03.:1119721:1 | 2 korrus
Kahepoolsed:SU-17:1243666:1 | 2 korrus
Aken ukse kohal:SU-1500_aken:1243665:1 | 2 korrus
Ühepoolsed:SU17_ülemine:1421710:1 | 2 korrus
Kahepoolsed:SU-22:508662:1 | 2 korrus
SEIN - 004 | 2 korrus
Kahepoolsed:SU-11:1247581:1 | 3 korrus
Ühepoolsed:SU-10:569781:1 | 3 korrus
SEIN - 004 | 3 korrus
Kahepoolsed:SU-14:569276:1 | 3 korrus
Kahepoolsed:SU-23:1239711:1 | 4 korrus
SEIN - 002 | 1 korrus
Kahepoolsed:SU-12.:239103:1 | 1 korrus
Kahepoolsed:VU-03:316793:1 | 1 korrus
7 x SEIN - 005 | 1 korrus
Ühepoolsed:SU-10:239116:1 | 1 korrus
Ühepoolsed:SU-10:1220456:1 | 1 korrus
Ühepoolsed:SU16_ülemine:1243722:1 | 1 korrus
Aken ukse kohal:SU-1500_aken 2:1663439:1 | 1 korrus
Kahepoolsed:SU-16:1243720:1 | 1 korrus
Klaasist lükanduksed:SU-19:797009:1 | 1 korrus
8 x SEIN - 001 | 1 korrus
SEIN - 003 | 1 korrus
Klaasist lükanduksed:VU-01:1418164:1 | 1 korrus
SEIN - 008 | 1 korrus
Kahepoolsed:SU-12:239321:1 | 1 korrus
Ühepoolsed:SU-15:239323:1 | 1 korrus

# IfcPlate: Glazed (588)
Type - ElementType: Glazed; PredefinedType: CURTAIN_PANEL; Material: <Unnamed> 20 mm
Pset_PlateCommon - LoadBearing: yes; Reference: Glazed
Name (System Panel:Glazed:...) | In | IsExternal
329682 | 1 korrus | no
329686 | 1 korrus | no
329684 | 1 korrus | no
339027 | 1 korrus | no
339029 | 1 korrus | no
339028 | 1 korrus | no
338179 | 1 korrus | no
338181 | 1 korrus | no
338180 | 1 korrus | no
338182 | 1 korrus | no
341502 | 1 korrus | no
1661308 | 1 korrus | no
341534 | 1 korrus | no
341536 | 1 korrus | no
1661309 | 1 korrus | no
341525 | 1 korrus | no
1661310 | 1 korrus | no
341528 | 1 korrus | no
489046 | 1 korrus | no
1078330 | 1 korrus | no
489048 | 1 korrus | no
489077 | 1 korrus | no
1078331 | 1 korrus | no
489080 | 1 korrus | no
489078 | 1 korrus | no
489070 | 1 korrus | no
1078332 | 1 korrus | no
489073 | 1 korrus | no
489071 | 1 korrus | no
495735 | 1 korrus | no
1078614 | 1 korrus | no
495737 | 1 korrus | no
1078531 | 1 korrus | no
495739 | 1 korrus | no
1076365 | 1 korrus | no
495766 | 1 korrus | no
1078615 | 1 korrus | no
495767 | 1 korrus | no
1078532 | 1 korrus | no
495769 | 1 korrus | no
495759 | 1 korrus | no
1078616 | 1 korrus | no
495760 | 1 korrus | no
1078533 | 1 korrus | no
495762 | 1 korrus | no
495761 | 1 korrus | no
1076367 | 1 korrus | no
515358 | 2 korrus | no
515362 | 2 korrus | no
515878 | 2 korrus | no
561697 | 2 korrus | no
919556 | 2 korrus | no
515364 | 2 korrus | no
515397 | 2 korrus | no
515400 | 2 korrus | no
1202938 | 2 korrus | no
515369 | 2 korrus | no
515371 | 2 korrus | no
515370 | 2 korrus | no
515372 | 2 korrus | no
515379 | 2 korrus | no
515398 | 2 korrus | no
515401 | 2 korrus | no
1202939 | 2 korrus | no
520278 | 2 korrus | no
1337269 | 2 korrus | no
520308 | 2 korrus | no
520301 | 2 korrus | no
1337267 | 2 korrus | no
1337271 | 2 korrus | no
555088 | 2 korrus | no
1116297 | 2 korrus | no
555185 | 2 korrus | no
555092 | 2 korrus | no
555090 | 2 korrus | no
555094 | 2 korrus | no
555122 | 2 korrus | no
555116 | 2 korrus | no
1116298 | 2 korrus | no
1116302 | 2 korrus | no
555186 | 2 korrus | no
555118 | 2 korrus | no
555117 | 2 korrus | no
555110 | 2 korrus | no
1116299 | 2 korrus | no
1116303 | 2 korrus | no
555187 | 2 korrus | no
555112 | 2 korrus | no
555111 | 2 korrus | no
555113 | 2 korrus | no
555124 | 2 korrus | no
555678 | 2 korrus | no
555682 | 2 korrus | no
555680 | 2 korrus | no
555712 | 2 korrus | no
555706 | 2 korrus | no
555708 | 2 korrus | no
555707 | 2 korrus | no
555700 | 2 korrus | no
555702 | 2 korrus | no
555701 | 2 korrus | no
555703 | 2 korrus | no
555714 | 2 korrus | no
562883 | 3 korrus | no
562885 | 3 korrus | no
562919 | 3 korrus | no
562913 | 3 korrus | no
562915 | 3 korrus | no
562914 | 3 korrus | no
562906 | 3 korrus | no
562907 | 3 korrus | no
562909 | 3 korrus | no
562921 | 3 korrus | no
562976 | 3 korrus | no
563289 | 3 korrus | no
1366790 | 3 korrus | no
562970 | 3 korrus | no
562971 | 3 korrus | no
562977 | 3 korrus | no
562964 | 3 korrus | no
562978 | 3 korrus | no
563291 | 3 korrus | no
1366792 | 3 korrus | no
563015 | 4 korrus | no
563017 | 4 korrus | no
563051 | 4 korrus | no
563045 | 4 korrus | no
563047 | 4 korrus | no
563046 | 4 korrus | no
563038 | 4 korrus | no
563039 | 4 korrus | no
563041 | 4 korrus | no
563053 | 4 korrus | no
567761 | 3 korrus | no
567763 | 3 korrus | no
567795 | 3 korrus | no
567765 | 3 korrus | no
567803 | 3 korrus | no
567789 | 3 korrus | no
567790 | 3 korrus | no
567792 | 3 korrus | no
567783 | 3 korrus | no
567784 | 3 korrus | no
567786 | 3 korrus | no
567797 | 3 korrus | no
567785 | 3 korrus | no
567805 | 3 korrus | no
568487 | 3 korrus | no
568493 | 3 korrus | no
568491 | 3 korrus | no
568489 | 3 korrus | no
1100859 | 3 korrus | no
568528 | 3 korrus | no
568515 | 3 korrus | no
568518 | 3 korrus | no
568509 | 3 korrus | no
568512 | 3 korrus | no
568511 | 3 korrus | no
568510 | 3 korrus | no
1101096 | 3 korrus | no
1100861 | 3 korrus | no
568530 | 3 korrus | no
569291 | 3 korrus | no
569295 | 3 korrus | no
569337 | 3 korrus | no
569297 | 3 korrus | no
569326 | 3 korrus | no
569329 | 3 korrus | no
964660 | 3 korrus | no
569301 | 3 korrus | no
569303 | 3 korrus | no
569302 | 3 korrus | no
569304 | 3 korrus | no
569309 | 3 korrus | no
569327 | 3 korrus | no
569330 | 3 korrus | no
964661 | 3 korrus | no
574381 | 3 korrus | no
574385 | 3 korrus | no
574383 | 3 korrus | no
574417 | 3 korrus | no
574411 | 3 korrus | no
574413 | 3 korrus | no
574412 | 3 korrus | no
574404 | 3 korrus | no
574406 | 3 korrus | no
574405 | 3 korrus | no
574407 | 3 korrus | no
574419 | 3 korrus | no
574862 | 3 korrus | no
574864 | 3 korrus | no
574898 | 3 korrus | no
574892 | 3 korrus | no
574894 | 3 korrus | no
574893 | 3 korrus | no
574885 | 3 korrus | no
574886 | 3 korrus | no
574888 | 3 korrus | no
574900 | 3 korrus | no
575477 | 3 korrus | no
575479 | 3 korrus | no
1055184 | 3 korrus | no
575505 | 3 korrus | no
575506 | 3 korrus | no
575508 | 3 korrus | no
1055185 | 3 korrus | no
575499 | 3 korrus | no
575500 | 3 korrus | no
575502 | 3 korrus | no
1055186 | 3 korrus | no
580367 | 4 korrus | no
1343603 | 4 korrus | no
580369 | 4 korrus | no
580402 | 4 korrus | no
580371 | 4 korrus | no
580395 | 4 korrus | no
580398 | 4 korrus | no
1343604 | 4 korrus | no
580389 | 4 korrus | no
580392 | 4 korrus | no
1343605 | 4 korrus | no
580390 | 4 korrus | no
580404 | 4 korrus | no
580391 | 4 korrus | no
580408 | 4 korrus | no
580442 | 4 korrus | no
1349775 | 4 korrus | no
580436 | 4 korrus | no
580439 | 4 korrus | no
580437 | 4 korrus | no
580430 | 4 korrus | no
580433 | 4 korrus | no
580444 | 4 korrus | no
1349777 | 4 korrus | no
580454 | 4 korrus | no
580458 | 4 korrus | no
580499 | 4 korrus | no
580460 | 4 korrus | no
580489 | 4 korrus | no
580492 | 4 korrus | no
1082797 | 4 korrus | no
580464 | 4 korrus | no
580466 | 4 korrus | no
580465 | 4 korrus | no
580467 | 4 korrus | no
580472 | 4 korrus | no
580490 | 4 korrus | no
580493 | 4 korrus | no
1082798 | 4 korrus | no
581265 | 4 korrus | no
581300 | 4 korrus | no
581269 | 4 korrus | no
581271 | 4 korrus | no
581275 | 4 korrus | no
581283 | 4 korrus | no
581301 | 4 korrus | no
581277 | 4 korrus | no
581278 | 4 korrus | no
581565 | 4 korrus | no
581582 | 4 korrus | no
1350265 | 4 korrus | no
1350268 | 4 korrus | no
581575 | 4 korrus | no
581583 | 4 korrus | no
581601 | 4 korrus | no
581576 | 4 korrus | no
1350266 | 4 korrus | no
1350269 | 4 korrus | no
927986 | uus 2 korrus | no
1458412 | uus 2 korrus | no
1458144 | uus 2 korrus | no
927992 | uus 2 korrus | no
927994 | uus 2 korrus | no
1457236 | uus 2 korrus | no
927996 | uus 2 korrus | no
1457238 | uus 2 korrus | no
928676 | uus 2 korrus | no
1562195 | uus 2 korrus | no
929399 | uus 2 korrus | no
929401 | uus 2 korrus | no
929403 | uus 2 korrus | no
929405 | uus 2 korrus | no
929407 | uus 2 korrus | no
929413 | uus 2 korrus | no
929530 | uus 2 korrus | no
930148 | uus 2 korrus | no
930152 | uus 2 korrus | no
930154 | uus 2 korrus | no
930513 | uus 2 korrus | no
930517 | uus 2 korrus | no
930519 | uus 2 korrus | no
930851 | uus 2 korrus | no
930853 | uus 2 korrus | no
934557 | uus 3 korrus | no
934561 | uus 3 korrus | no
934563 | uus 3 korrus | no
934565 | uus 3 korrus | no
1095894 | uus 3 korrus | no
1005813 | uus 3 korrus | no
1005815 | uus 3 korrus | no
1117690 | 2 korrus | no
1117692 | 2 korrus | no
1117723 | 2 korrus | no
1117719 | 2 korrus | no
1117715 | 2 korrus | no
1117716 | 2 korrus | no
1117717 | 2 korrus | no
1117724 | 2 korrus | no
1117720 | 2 korrus | no
1117710 | 2 korrus | no
1117711 | 2 korrus | no
1117712 | 2 korrus | no
1117725 | 2 korrus | no
1117721 | 2 korrus | no
1745116 | 4 korrus | no
1745119 | 4 korrus | no
1745121 | 4 korrus | no
1745123 | 4 korrus | no
1333740 | 2 korrus | no
1333744 | 2 korrus | no
1333742 | 2 korrus | no
1333774 | 2 korrus | no
1333768 | 2 korrus | no
1333770 | 2 korrus | no
1333769 | 2 korrus | no
1333762 | 2 korrus | no
1333764 | 2 korrus | no
1333763 | 2 korrus | no
1333765 | 2 korrus | no
1333776 | 2 korrus | no
1334403 | 2 korrus | no
1334407 | 2 korrus | no
1334405 | 2 korrus | no
1334437 | 2 korrus | no
1334431 | 2 korrus | no
1334433 | 2 korrus | no
1334432 | 2 korrus | no
1334425 | 2 korrus | no
1334427 | 2 korrus | no
1334426 | 2 korrus | no
1334428 | 2 korrus | no
1334439 | 2 korrus | no
1451146 | 3 korrus | yes | Group: Model Group:KLF-01:1450670
1451150 | 3 korrus | yes | Group: Model Group:KLF-01:1450670
1455956 | 3 korrus | yes | Group: Model Group:KLF-01:1450670
1455957 | 3 korrus | yes | Group: Model Group:KLF-01:1450670
1451475 | 3 korrus | yes | Group: Model Group:KLF-01:1450670
1451476 | 3 korrus | yes | Group: Model Group:KLF-01:1450670
1451260 | 3 korrus | yes | Group: Model Group:KLF-01:1450670
1451261 | 3 korrus | yes | Group: Model Group:KLF-01:1450670
1451234 | 3 korrus | yes | Group: Model Group:KLF-01:1450670
1451235 | 3 korrus | yes | Group: Model Group:KLF-01:1450670
1451236 | 3 korrus | yes | Group: Model Group:KLF-01:1450670
1451237 | 3 korrus | yes | Group: Model Group:KLF-01:1450670
1451238 | 3 korrus | yes | Group: Model Group:KLF-01:1450670
1451239 | 3 korrus | yes | Group: Model Group:KLF-01:1450670
1451240 | 3 korrus | yes | Group: Model Group:KLF-01:1450670
1451241 | 3 korrus | yes | Group: Model Group:KLF-01:1450670
1451242 | 3 korrus | yes | Group: Model Group:KLF-01:1450670
1451243 | 3 korrus | yes | Group: Model Group:KLF-01:1450670
1451244 | 3 korrus | yes | Group: Model Group:KLF-01:1450670
1451245 | 3 korrus | yes | Group: Model Group:KLF-01:1450670
1451246 | 3 korrus | yes | Group: Model Group:KLF-01:1450670
1451436 | 3 korrus | yes | Group: Model Group:KLF-01:1450670
1451437 | 3 korrus | yes | Group: Model Group:KLF-01:1450670
1451438 | 3 korrus | yes | Group: Model Group:KLF-01:1450670
1451439 | 3 korrus | yes | Group: Model Group:KLF-01:1450670
1451440 | 3 korrus | yes | Group: Model Group:KLF-01:1450670
1451441 | 3 korrus | yes | Group: Model Group:KLF-01:1450670
1451442 | 3 korrus | yes | Group: Model Group:KLF-01:1450670
1451443 | 3 korrus | yes | Group: Model Group:KLF-01:1450670
1451444 | 3 korrus | yes | Group: Model Group:KLF-01:1450670
1451445 | 3 korrus | yes | Group: Model Group:KLF-01:1450670
1451446 | 3 korrus | yes | Group: Model Group:KLF-01:1450670
1451447 | 3 korrus | yes | Group: Model Group:KLF-01:1450670
1451448 | 3 korrus | yes | Group: Model Group:KLF-01:1450670
1451218 | 3 korrus | yes | Group: Model Group:KLF-01:1450670
1451219 | 3 korrus | yes | Group: Model Group:KLF-01:1450670
1451220 | 3 korrus | yes | Group: Model Group:KLF-01:1450670
1451221 | 3 korrus | yes | Group: Model Group:KLF-01:1450670
1451222 | 3 korrus | yes | Group: Model Group:KLF-01:1450670
1451223 | 3 korrus | yes | Group: Model Group:KLF-01:1450670
1451224 | 3 korrus | yes | Group: Model Group:KLF-01:1450670
1451225 | 3 korrus | yes | Group: Model Group:KLF-01:1450670
1451226 | 3 korrus | yes | Group: Model Group:KLF-01:1450670
1451227 | 3 korrus | yes | Group: Model Group:KLF-01:1450670
1451228 | 3 korrus | yes | Group: Model Group:KLF-01:1450670
1451229 | 3 korrus | yes | Group: Model Group:KLF-01:1450670
1451230 | 3 korrus | yes | Group: Model Group:KLF-01:1450670
1451202 | 3 korrus | yes | Group: Model Group:KLF-01:1450670
1451203 | 3 korrus | yes | Group: Model Group:KLF-01:1450670
1451204 | 3 korrus | yes | Group: Model Group:KLF-01:1450670
1451205 | 3 korrus | yes | Group: Model Group:KLF-01:1450670
1451206 | 3 korrus | yes | Group: Model Group:KLF-01:1450670
1451207 | 3 korrus | yes | Group: Model Group:KLF-01:1450670
1451208 | 3 korrus | yes | Group: Model Group:KLF-01:1450670
1451209 | 3 korrus | yes | Group: Model Group:KLF-01:1450670
1451210 | 3 korrus | yes | Group: Model Group:KLF-01:1450670
1451211 | 3 korrus | yes | Group: Model Group:KLF-01:1450670
1451212 | 3 korrus | yes | Group: Model Group:KLF-01:1450670
1451213 | 3 korrus | yes | Group: Model Group:KLF-01:1450670
1451214 | 3 korrus | yes | Group: Model Group:KLF-01:1450670
1451186 | 3 korrus | yes | Group: Model Group:KLF-01:1450670
1451187 | 3 korrus | yes | Group: Model Group:KLF-01:1450670
1451188 | 3 korrus | yes | Group: Model Group:KLF-01:1450670
1451189 | 3 korrus | yes | Group: Model Group:KLF-01:1450670
1451190 | 3 korrus | yes | Group: Model Group:KLF-01:1450670
1451191 | 3 korrus | yes | Group: Model Group:KLF-01:1450670
1451192 | 3 korrus | yes | Group: Model Group:KLF-01:1450670
1451193 | 3 korrus | yes | Group: Model Group:KLF-01:1450670
1451194 | 3 korrus | yes | Group: Model Group:KLF-01:1450670
1451195 | 3 korrus | yes | Group: Model Group:KLF-01:1450670
1451196 | 3 korrus | yes | Group: Model Group:KLF-01:1450670
1451197 | 3 korrus | yes | Group: Model Group:KLF-01:1450670
1451198 | 3 korrus | yes | Group: Model Group:KLF-01:1450670
1451408 | 3 korrus | yes | Group: Model Group:KLF-01:1450670
1451409 | 3 korrus | yes | Group: Model Group:KLF-01:1450670
1451410 | 3 korrus | yes | Group: Model Group:KLF-01:1450670
1451411 | 3 korrus | yes | Group: Model Group:KLF-01:1450670
1451412 | 3 korrus | yes | Group: Model Group:KLF-01:1450670
1451413 | 3 korrus | yes | Group: Model Group:KLF-01:1450670
1451414 | 3 korrus | yes | Group: Model Group:KLF-01:1450670
1451415 | 3 korrus | yes | Group: Model Group:KLF-01:1450670
1451416 | 3 korrus | yes | Group: Model Group:KLF-01:1450670
1451417 | 3 korrus | yes | Group: Model Group:KLF-01:1450670
1451418 | 3 korrus | yes | Group: Model Group:KLF-01:1450670
1451419 | 3 korrus | yes | Group: Model Group:KLF-01:1450670
1451420 | 3 korrus | yes | Group: Model Group:KLF-01:1450670
1451170 | 3 korrus | yes | Group: Model Group:KLF-01:1450670
1451171 | 3 korrus | yes | Group: Model Group:KLF-01:1450670
1451172 | 3 korrus | yes | Group: Model Group:KLF-01:1450670
1451173 | 3 korrus | yes | Group: Model Group:KLF-01:1450670
1451174 | 3 korrus | yes | Group: Model Group:KLF-01:1450670
1451175 | 3 korrus | yes | Group: Model Group:KLF-01:1450670
1451176 | 3 korrus | yes | Group: Model Group:KLF-01:1450670
1451177 | 3 korrus | yes | Group: Model Group:KLF-01:1450670
1451178 | 3 korrus | yes | Group: Model Group:KLF-01:1450670
1451179 | 3 korrus | yes | Group: Model Group:KLF-01:1450670
1451180 | 3 korrus | yes | Group: Model Group:KLF-01:1450670
1451181 | 3 korrus | yes | Group: Model Group:KLF-01:1450670
1451182 | 3 korrus | yes | Group: Model Group:KLF-01:1450670
1451154 | 3 korrus | yes | Group: Model Group:KLF-01:1450670
1451155 | 3 korrus | yes | Group: Model Group:KLF-01:1450670
1451156 | 3 korrus | yes | Group: Model Group:KLF-01:1450670
1451157 | 3 korrus | yes | Group: Model Group:KLF-01:1450670
1451158 | 3 korrus | yes | Group: Model Group:KLF-01:1450670
1451159 | 3 korrus | yes | Group: Model Group:KLF-01:1450670
1451160 | 3 korrus | yes | Group: Model Group:KLF-01:1450670
1451161 | 3 korrus | yes | Group: Model Group:KLF-01:1450670
1451162 | 3 korrus | yes | Group: Model Group:KLF-01:1450670
1451163 | 3 korrus | yes | Group: Model Group:KLF-01:1450670
1451164 | 3 korrus | yes | Group: Model Group:KLF-01:1450670
1451165 | 3 korrus | yes | Group: Model Group:KLF-01:1450670
1451166 | 3 korrus | yes | Group: Model Group:KLF-01:1450670
1453337 | 3 korrus | yes | Group: Model Group:KLF-02:1453116
1453381 | 3 korrus | yes | Group: Model Group:KLF-02:1453116
1453396 | 3 korrus | yes | Group: Model Group:KLF-02:1453116
1453413 | 3 korrus | yes | Group: Model Group:KLF-02:1453116
1453445 | 3 korrus | yes | Group: Model Group:KLF-02:1453116
1453428 | 3 korrus | yes | Group: Model Group:KLF-02:1453116
1453373 | 3 korrus | yes | Group: Model Group:KLF-02:1453116
1453382 | 3 korrus | yes | Group: Model Group:KLF-02:1453116
1453397 | 3 korrus | yes | Group: Model Group:KLF-02:1453116
1453414 | 3 korrus | yes | Group: Model Group:KLF-02:1453116
1453446 | 3 korrus | yes | Group: Model Group:KLF-02:1453116
1453429 | 3 korrus | yes | Group: Model Group:KLF-02:1453116
1453362 | 3 korrus | yes | Group: Model Group:KLF-02:1453116
1453383 | 3 korrus | yes | Group: Model Group:KLF-02:1453116
1453398 | 3 korrus | yes | Group: Model Group:KLF-02:1453116
1453415 | 3 korrus | yes | Group: Model Group:KLF-02:1453116
1453447 | 3 korrus | yes | Group: Model Group:KLF-02:1453116
1453430 | 3 korrus | yes | Group: Model Group:KLF-02:1453116
1453359 | 3 korrus | yes | Group: Model Group:KLF-02:1453116
1453384 | 3 korrus | yes | Group: Model Group:KLF-02:1453116
1453399 | 3 korrus | yes | Group: Model Group:KLF-02:1453116
1453416 | 3 korrus | yes | Group: Model Group:KLF-02:1453116
1453448 | 3 korrus | yes | Group: Model Group:KLF-02:1453116
1453431 | 3 korrus | yes | Group: Model Group:KLF-02:1453116
1453356 | 3 korrus | yes | Group: Model Group:KLF-02:1453116
1453385 | 3 korrus | yes | Group: Model Group:KLF-02:1453116
1453400 | 3 korrus | yes | Group: Model Group:KLF-02:1453116
1453417 | 3 korrus | yes | Group: Model Group:KLF-02:1453116
1453449 | 3 korrus | yes | Group: Model Group:KLF-02:1453116
1453432 | 3 korrus | yes | Group: Model Group:KLF-02:1453116
1453370 | 3 korrus | yes | Group: Model Group:KLF-02:1453116
1453386 | 3 korrus | yes | Group: Model Group:KLF-02:1453116
1453401 | 3 korrus | yes | Group: Model Group:KLF-02:1453116
1453418 | 3 korrus | yes | Group: Model Group:KLF-02:1453116
1453450 | 3 korrus | yes | Group: Model Group:KLF-02:1453116
1453433 | 3 korrus | yes | Group: Model Group:KLF-02:1453116
1453353 | 3 korrus | yes | Group: Model Group:KLF-02:1453116
1453387 | 3 korrus | yes | Group: Model Group:KLF-02:1453116
1453402 | 3 korrus | yes | Group: Model Group:KLF-02:1453116
1453419 | 3 korrus | yes | Group: Model Group:KLF-02:1453116
1453451 | 3 korrus | yes | Group: Model Group:KLF-02:1453116
1453434 | 3 korrus | yes | Group: Model Group:KLF-02:1453116
1453350 | 3 korrus | yes | Group: Model Group:KLF-02:1453116
1453388 | 3 korrus | yes | Group: Model Group:KLF-02:1453116
1453403 | 3 korrus | yes | Group: Model Group:KLF-02:1453116
1453420 | 3 korrus | yes | Group: Model Group:KLF-02:1453116
1453452 | 3 korrus | yes | Group: Model Group:KLF-02:1453116
1453435 | 3 korrus | yes | Group: Model Group:KLF-02:1453116
1453467 | 3 korrus | yes | Group: Model Group:KLF-02:1453116
1658891 | 3 korrus | yes | Group: Model Group:KLF-04:1658778
1658908 | 3 korrus | yes | Group: Model Group:KLF-04:1658778
1658972 | 3 korrus | yes | Group: Model Group:KLF-04:1658778
1658973 | 3 korrus | yes | Group: Model Group:KLF-04:1658778
1658941 | 3 korrus | yes | Group: Model Group:KLF-04:1658778
1658942 | 3 korrus | yes | Group: Model Group:KLF-04:1658778
1658937 | 3 korrus | yes | Group: Model Group:KLF-04:1658778
1658938 | 3 korrus | yes | Group: Model Group:KLF-04:1658778
1658966 | 3 korrus | yes | Group: Model Group:KLF-04:1658778
1658967 | 3 korrus | yes | Group: Model Group:KLF-04:1658778
1658932 | 3 korrus | yes | Group: Model Group:KLF-04:1658778
1658933 | 3 korrus | yes | Group: Model Group:KLF-04:1658778
1658927 | 3 korrus | yes | Group: Model Group:KLF-04:1658778
1658928 | 3 korrus | yes | Group: Model Group:KLF-04:1658778
1658922 | 3 korrus | yes | Group: Model Group:KLF-04:1658778
1658923 | 3 korrus | yes | Group: Model Group:KLF-04:1658778
1658960 | 3 korrus | yes | Group: Model Group:KLF-04:1658778
1658961 | 3 korrus | yes | Group: Model Group:KLF-04:1658778
1658917 | 3 korrus | yes | Group: Model Group:KLF-04:1658778
1658918 | 3 korrus | yes | Group: Model Group:KLF-04:1658778
1658912 | 3 korrus | yes | Group: Model Group:KLF-04:1658778
1658913 | 3 korrus | yes | Group: Model Group:KLF-04:1658778
1658982 | 3 korrus | yes | Group: Model Group:KLF-04:1658778
1658983 | 3 korrus | yes | Group: Model Group:KLF-04:1658778
1660884 | 3 korrus | yes | Group: Model Group:KLF-03:1660694
1660999 | 3 korrus | yes | Group: Model Group:KLF-03:1660694
1660987 | 3 korrus | yes | Group: Model Group:KLF-03:1660694
1660934 | 3 korrus | yes | Group: Model Group:KLF-03:1660694
1660919 | 3 korrus | yes | Group: Model Group:KLF-03:1660694
1660915 | 3 korrus | yes | Group: Model Group:KLF-03:1660694
1661000 | 3 korrus | yes | Group: Model Group:KLF-03:1660694
1660988 | 3 korrus | yes | Group: Model Group:KLF-03:1660694
1660935 | 3 korrus | yes | Group: Model Group:KLF-03:1660694
1660920 | 3 korrus | yes | Group: Model Group:KLF-03:1660694
1661011 | 3 korrus | yes | Group: Model Group:KLF-03:1660694
1661012 | 3 korrus | yes | Group: Model Group:KLF-03:1660694
1661013 | 3 korrus | yes | Group: Model Group:KLF-03:1660694
1661014 | 3 korrus | yes | Group: Model Group:KLF-03:1660694
1661015 | 3 korrus | yes | Group: Model Group:KLF-03:1660694
1660909 | 3 korrus | yes | Group: Model Group:KLF-03:1660694
1661001 | 3 korrus | yes | Group: Model Group:KLF-03:1660694
1660989 | 3 korrus | yes | Group: Model Group:KLF-03:1660694
1660936 | 3 korrus | yes | Group: Model Group:KLF-03:1660694
1660921 | 3 korrus | yes | Group: Model Group:KLF-03:1660694
1660906 | 3 korrus | yes | Group: Model Group:KLF-03:1660694
1661002 | 3 korrus | yes | Group: Model Group:KLF-03:1660694
1660990 | 3 korrus | yes | Group: Model Group:KLF-03:1660694
1660937 | 3 korrus | yes | Group: Model Group:KLF-03:1660694
1660922 | 3 korrus | yes | Group: Model Group:KLF-03:1660694
1660903 | 3 korrus | yes | Group: Model Group:KLF-03:1660694
1661003 | 3 korrus | yes | Group: Model Group:KLF-03:1660694
1660991 | 3 korrus | yes | Group: Model Group:KLF-03:1660694
1660938 | 3 korrus | yes | Group: Model Group:KLF-03:1660694
1660923 | 3 korrus | yes | Group: Model Group:KLF-03:1660694
1660912 | 3 korrus | yes | Group: Model Group:KLF-03:1660694
1661004 | 3 korrus | yes | Group: Model Group:KLF-03:1660694
1660992 | 3 korrus | yes | Group: Model Group:KLF-03:1660694
1660939 | 3 korrus | yes | Group: Model Group:KLF-03:1660694
1660924 | 3 korrus | yes | Group: Model Group:KLF-03:1660694
1661021 | 3 korrus | yes | Group: Model Group:KLF-03:1660694
1661022 | 3 korrus | yes | Group: Model Group:KLF-03:1660694
1661023 | 3 korrus | yes | Group: Model Group:KLF-03:1660694
1661024 | 3 korrus | yes | Group: Model Group:KLF-03:1660694
1661025 | 3 korrus | yes | Group: Model Group:KLF-03:1660694
1660900 | 3 korrus | yes | Group: Model Group:KLF-03:1660694
1661005 | 3 korrus | yes | Group: Model Group:KLF-03:1660694
1660993 | 3 korrus | yes | Group: Model Group:KLF-03:1660694
1660940 | 3 korrus | yes | Group: Model Group:KLF-03:1660694
1660925 | 3 korrus | yes | Group: Model Group:KLF-03:1660694
1660897 | 3 korrus | yes | Group: Model Group:KLF-03:1660694
1661006 | 3 korrus | yes | Group: Model Group:KLF-03:1660694
1660994 | 3 korrus | yes | Group: Model Group:KLF-03:1660694
1660941 | 3 korrus | yes | Group: Model Group:KLF-03:1660694
1660926 | 3 korrus | yes | Group: Model Group:KLF-03:1660694
1660951 | 3 korrus | yes | Group: Model Group:KLF-03:1660694
1662677 | 1 korrus | no
1662681 | 1 korrus | no
1662679 | 1 korrus | no
1662708 | 1 korrus | no
1662710 | 1 korrus | no
1662709 | 1 korrus | no
1662701 | 1 korrus | no
1662703 | 1 korrus | no
1662702 | 1 korrus | no
1662704 | 1 korrus | no

# IfcRailing: Generic Models 7 (2)
Type - Material: __Metal Tumehall
Pset_RailingCommon - IsExternal: no; Reference: Generic Models 7
Name | In
Generic Models 1:Generic Models 7:1034498 | Vundament
Generic Models 2:Generic Models 7:1056262 | 1 korrus

# IfcRailing: Railing:1000mm trossidega piire, Railing:1000mm trossidega piire:1675756
In: 1 korrus
Material: __Tumehall
Pset_RailingCommon - IsExternal: no; Reference: 1000mm trossidega piire; Height: 1219.2 mm

# IfcRailing: Railing:500mm trossidega piire, Railing:500mm trossidega piire:1676931
In: uus 1 korrus
Material: __Tumehall
Pset_RailingCommon - IsExternal: no; Reference: 500mm trossidega piire; Height: 1219.2 mm

# IfcRailing: Railing:Piire hor_post - 1000mm (6)
Pset_RailingCommon - IsExternal: no; Reference: Piire hor_post - 1000mm; Height: 1219.2 mm
Name (Railing:Piire hor_post - 1000mm:...) | In
1372760 | uus 1 korrus
1373379 | uus 2 korrus
1445882 | uus 2 korrus
1446058 | uus 2 korrus
1446137 | uus 3 korrus
1446308 | uus 3 korrus

# IfcRamp: Ramp:kaldtee trepikojas 126:1419213, Ramp:kaldtee trepikojas 126:1419197
In: uus 1 korrus
Pset_RampCommon - IsExternal: no; Reference: kaldtee trepikojas 126

# IfcRampFlight: Ramp:kaldtee trepikojas 126:1419213, Ramp:kaldtee trepikojas 126:1419197:1
In: uus 1 korrus
Pset_RampFlightCommon - Reference: kaldtee trepikojas 126

# IfcRoof: Basic Roof:KL-1_olemasolev rekonstrueeritav katus, Basic Roof:KL-1_olemasolev rekonstrueeritav katus:999415
In: Katusekorrus
Pset_RoofCommon - IsExternal: yes; Reference: KL-1_olemasolev rekonstrueeritav katus; TotalArea: 160.2 m2; ProjectedArea: 159.873 m2
AR_IFC_KATUSED - 01.Nimetus: Katuslagi; 02.Materjal: Õõnespaneel; 03.Kategooria / tüüp: KL-1; Phase Created: New Construction

# IfcRoof: Basic Roof:KL-1_olemasolev rekonstrueeritav katus:956734, Basic Roof:KL-1_olemasolev rekonstrueeritav katus:998968
In: Katusekorrus
Material: Betoon paneel
Pset_RoofCommon - IsExternal: yes; Reference: KL-1_olemasolev rekonstrueeritav katus; TotalArea: 190.558 m2; ProjectedArea: 191.044 m2
AR_IFC_KATUSED - 01.Nimetus: Katuslagi; 02.Materjal: Õõnespaneel; 03.Kategooria / tüüp: KL-1; Phase Created: New Construction

# IfcRoof: Basic Roof:KL-2 (3)
Pset_RoofCommon - IsExternal: yes; Reference: KL-2
AR_IFC_KATUSED - 01.Nimetus: Katuslagi; 02.Materjal: Profiilplekk; 03.Kategooria / tüüp: KL-2; Phase Created: New Construction
Name (Basic Roof:KL-2:...) | In | TotalArea (m2) | ProjectedArea (m2)
957345 | Katusekorrus | 56.738 | 56.7034
1013743 | Katusekorrus | 17.2652 | 17.2547
1265658 | 1 korrus | 23.0765 | 23.0624

# IfcRoof: Basic Roof:KL-2 .1_uus katus:933391, Basic Roof:KL-2 .1_uus katus:384110
In: uus Katus
Pset_RoofCommon - IsExternal: yes; Reference: KL-2 .1_uus katus; TotalArea: 90.6496 m2; ProjectedArea: 91.4126 m2
AR_IFC_KATUSED - 01.Nimetus: Katuslagi; 02.Materjal: Õõnespaneel; 03.Kategooria / tüüp: KL-2.1; Phase Created: New Construction

# IfcRoof: Basic Roof:Olemasolev varikatus, Basic Roof:Olemasolev varikatus:1747687
In: 2 korrus
Pset_RoofCommon - IsExternal: yes; Reference: Olemasolev varikatus; TotalArea: 2.98473 m2; ProjectedArea: 2.98473 m2
AR_IFC_KATUSED - 01.Nimetus: Varikatus; 02.Materjal: Betoon; 03.Kategooria / tüüp: Varikatus5; Phase Created: New Construction

# IfcRoof: Basic Roof:Prügimaja katus, Basic Roof:Prügimaja katus:991063
In: 1 korrus
Pset_RoofCommon - IsExternal: yes; Reference: Prügimaja katus; TotalArea: 12.4168 m2; ProjectedArea: 12.3997 m2
AR_IFC_KATUSED - 01.Nimetus: Prügimaja katus; 02.Materjal: SWpaneel; 03.Kategooria / tüüp: Uus prügimaja katus; Phase Created: New Construction

# IfcRoof: Basic Roof:Vent.ruumi õõnespaneelid, Basic Roof:Vent.ruumi õõnespaneelid:979641
In: Katusekorrus
Pset_RoofCommon - IsExternal: yes; Reference: Vent.ruumi õõnespaneelid; TotalArea: 13.7463 m2; ProjectedArea: 13.7182 m2
AR_IFC_KATUSED - 01.Nimetus: Katuslagi; 02.Materjal: Õõnespaneel; 03.Kategooria / tüüp: Olemasoleva katuse õõnespaneelid; Phase Created: Existing

# IfcRoof: Basic Roof:Vent.ruumi õõnespaneelid:999304, Basic Roof:Vent.ruumi õõnespaneelid:956428
In: Katusekorrus
Material: Betoon paneel
Pset_RoofCommon - IsExternal: yes; Reference: Vent.ruumi õõnespaneelid; TotalArea: 40.1349 m2; ProjectedArea: 41.4829 m2
AR_IFC_KATUSED - 01.Nimetus: Katuslagi; 02.Materjal: Õõnespaneel; 03.Kategooria / tüüp: Olemasoleva katuse õõnespaneelid; Phase Created: Existing

# IfcRoof: Basic Roof:lifti katus, Basic Roof:lifti katus:1562392
In: uus Katus
Pset_RoofCommon - IsExternal: yes; Reference: lifti katus; TotalArea: 8.30731 m2; ProjectedArea: 8.30731 m2
AR_IFC_KATUSED - 01.Nimetus: Lifti katus; 02.Materjal: Plekk; 03.Kategooria / tüüp: Uus lifti katus; Phase Created: New Construction

# IfcRoof: KATUS - 002:KATUS - 002:201144, KATUS - 002:KATUS - 002:201146
In: Katus vent.
Material: Paint - Dark Gray
Pset_RoofCommon - IsExternal: yes; Reference: KATUS - 002; TotalArea: 6.31752 m2
AR_IFC_KATUSED - 01.Nimetus: Lifti katus; 02.Materjal: Plekk; 03.Kategooria / tüüp: Olemasolev lifti katus; Phase Created: Existing

# IfcRoof: OBJEKT-001:OBJEKT-001:200015, OBJEKT-001:OBJEKT-001:200017
In: 1 korrus
Material: Paint - Dark Gray
Pset_RoofCommon - Reference: OBJEKT-001; IsExternal: yes; TotalArea: 21.6007 m2
AR_IFC_KATUSED - 01.Nimetus: Varikatus; 02.Materjal: Betoon; 03.Kategooria / tüüp: Varikatus4; Phase Created: Existing

# IfcRoof: Päikesesirm:päikesesirm:977803 (6)
Material: Steel/Aluminium
Pset_RoofCommon - IsExternal: no; Reference: päikesesirm; TotalArea: 2.84451 m2
Pset_ManufacturerTypeInformation - Manufacturer: Kawneer
Name (Päikesesirm:päikesesirm:...) | In
977846 | 4 korrus
978829 | 4 korrus
978841 | 4 korrus
978851 | 4 korrus
978900 | 2 korrus
979346 | 2 korrus

# IfcSlab: Basic Roof:KL-1_olemasolev rekonstrueeritav katus, Basic Roof:KL-1_olemasolev rekonstrueeritav katus:999415
In: Katusekorrus
PredefinedType: ROOF; Material: SBS 10 mm, Jäik villaplaat 30 mm, Soojustus, polüuretaan 120 mm, Soojustus, polüuretaan 120 mm, Betoon 50 mm, Betoon paneel 220 mm
Pset_SlabCommon - IsExternal: yes; Reference: KL-1_olemasolev rekonstrueeritav katus; PitchAngle: 3.66 deg
AR_IFC_KATUSED - 01.Nimetus: Katuslagi; 02.Materjal: Õõnespaneel; 03.Kategooria / tüüp: KL-1; Phase Created: New Construction

# IfcSlab: Basic Roof:KL-2 (3)
PredefinedType: ROOF; Material: PVC 3 mm, Rocwool 120 mm, Profiilplekk 130 mm
Pset_SlabCommon - IsExternal: yes; Reference: KL-2; PitchAngle: 2 deg
AR_IFC_KATUSED - 01.Nimetus: Katuslagi; 02.Materjal: Profiilplekk; 03.Kategooria / tüüp: KL-2; Phase Created: New Construction
Name (Basic Roof:KL-2:...) | In
957345 | Katusekorrus
1013743 | Katusekorrus
1265658 | 1 korrus

# IfcSlab: Basic Roof:KL-2 .1_uus katus:933391, Basic Roof:KL-2 .1_uus katus:384110:1
In: uus Katus
PredefinedType: ROOF; Material: SBS 10 mm, Jäik villaplaat 30 mm, Soojustus, polüuretaan 200 mm, Soojustus, polüuretaan 150 mm, Betoon paneel 220 mm; Betoon paneel
Pset_SlabCommon - PitchAngle: 0 deg; IsExternal: yes; Reference: KL-2 .1_uus katus
AR_IFC_KATUSED - 01.Nimetus: Katuslagi; 02.Materjal: Õõnespaneel; 03.Kategooria / tüüp: KL-2.1; Phase Created: New Construction

# IfcSlab: Basic Roof:Olemasolev varikatus, Basic Roof:Olemasolev varikatus:1747687
In: 2 korrus
PredefinedType: ROOF; Material: Betoon 130 mm
Pset_SlabCommon - PitchAngle: 0 deg; IsExternal: yes; Reference: Olemasolev varikatus
AR_IFC_KATUSED - 01.Nimetus: Varikatus; 02.Materjal: Betoon; 03.Kategooria / tüüp: Varikatus5; Phase Created: New Construction

# IfcSlab: Basic Roof:Prügimaja katus, Basic Roof:Prügimaja katus:991063
In: 1 korrus
PredefinedType: ROOF; Material: SW katusepaneel 75 mm
Pset_SlabCommon - IsExternal: yes; Reference: Prügimaja katus; PitchAngle: 3 deg
AR_IFC_KATUSED - 01.Nimetus: Prügimaja katus; 02.Materjal: SWpaneel; 03.Kategooria / tüüp: Uus prügimaja katus; Phase Created: New Construction

# IfcSlab: Basic Roof:Vent.ruumi õõnespaneelid, Basic Roof:Vent.ruumi õõnespaneelid:979641
In: Katusekorrus
PredefinedType: ROOF; Material: Betoon paneel 220 mm
Pset_SlabCommon - IsExternal: yes; Reference: Vent.ruumi õõnespaneelid; PitchAngle: 3.66 deg
AR_IFC_KATUSED - 01.Nimetus: Katuslagi; 02.Materjal: Õõnespaneel; 03.Kategooria / tüüp: Olemasoleva katuse õõnespaneelid; Phase Created: Existing

# IfcSlab: Basic Roof:lifti katus, Basic Roof:lifti katus:1562392
In: uus Katus
PredefinedType: ROOF; Material: SW katusepaneel 75 mm
Pset_SlabCommon - PitchAngle: 0 deg; IsExternal: yes; Reference: lifti katus
AR_IFC_KATUSED - 01.Nimetus: Lifti katus; 02.Materjal: Plekk; 03.Kategooria / tüüp: Uus lifti katus; Phase Created: New Construction

# IfcSlab: Floor:Betoontasand 2 (3)
PredefinedType: FLOOR; Material: Betoon 100 mm
Pset_SlabCommon - LoadBearing: no; PitchAngle: 0 deg; IsExternal: yes; Reference: Betoontasand 2
AR_IFC_VAHELAED_PÕRANDAD - Phase Created: New Construction
Name (Floor:Betoontasand 2:...) | In | 01.Nimetus | 02.Materjal | 03.Kategooria / tüüp
319945 | 1 korrus | Põrand pinnasel | Betoon | P-1
1434928 | uus 3 korrus | Keerdtrepi põrand | Metallrest | -
1434935 | uus 2 korrus | Keerdtrepi põrand | Metallrest | -

# IfcSlab: Floor:Lifti põrand (2)
PredefinedType: FLOOR; Material: Betoon 100 mm
Pset_SlabCommon - LoadBearing: no; PitchAngle: 0 deg; IsExternal: yes; Reference: Lifti põrand
AR_IFC_VAHELAED_PÕRANDAD - 01.Nimetus: Põrand pinnasel; 02.Materjal: Betoon
Name (Floor:Lifti põrand:...) | In | 03.Kategooria / tüüp | Phase Created
1437954 | uus 1 korrus | P-2.1 | New Construction
1762341 | Vundament | - | Existing

# IfcSlab: Floor:Olemasolev põrand pinnasel, Floor:Olemasolev põrand pinnasel:239085
In: Vundament
PredefinedType: FLOOR; Material: Betoonplaat 238.7 mm
Pset_SlabCommon - LoadBearing: no; IsExternal: no; PitchAngle: 0 deg; Reference: Olemasolev põrand pinnasel
AR_IFC_VAHELAED_PÕRANDAD - Phase Created: Existing

# IfcSlab: Floor:P-1_Esimese korruse põrand (4)
In: 1 korrus
PredefinedType: FLOOR; Material: Viimistlus_kelder 20 mm, Betoon 100 mm, __Soojustus EPS 150 mm, Aluspinnas 100 mm
Pset_SlabCommon - LoadBearing: no; PitchAngle: 0 deg; IsExternal: yes; Reference: P-1_Esimese korruse põrand
AR_IFC_VAHELAED_PÕRANDAD - 01.Nimetus: Põrand pinnasel; 02.Materjal: Betoon; 03.Kategooria / tüüp: P-1
Name (Floor:P-1_Esimese korruse põrand:...) | Phase Created
239326 | Existing
293139 | New Construction
296916 | New Construction
312343 | New Construction

# IfcSlab: Floor:P-2.1_Esimese korruse põrand juurdeehitusel (2)
In: uus 1 korrus
PredefinedType: FLOOR; Material: Viimistlus_kelder 20 mm, Betoon 100 mm, __Soojustus EPS 150 mm, Aluspinnas 100 mm
Pset_SlabCommon - LoadBearing: no; PitchAngle: 0 deg; IsExternal: yes; Reference: P-2.1_Esimese korruse põrand juurdeehitusel
AR_IFC_VAHELAED_PÕRANDAD - 01.Nimetus: Põrand pinnasel; 02.Materjal: Betoon; 03.Kategooria / tüüp: P-2.1; Phase Created: New Construction
Name (Floor:P-2.1_Esimese korruse põrand juurdeehitusel:...)
311080
898270

# IfcSlab: Floor:Põrand tuulekojas, Floor:Põrand tuulekojas:239048
In: 1 korrus
PredefinedType: FLOOR; Material: GENEERILINE - KONSTRUKTRIOON 273.964 mm
Pset_SlabCommon - LoadBearing: no; IsExternal: no; PitchAngle: 0 deg; Reference: Põrand tuulekojas
AR_IFC_VAHELAED_PÕRANDAD - Phase Created: Existing

# IfcSlab: Floor:Trepimade1 (2)
PredefinedType: FLOOR; Material: Betoonplaat 120 mm
Pset_SlabCommon - LoadBearing: no; IsExternal: no; PitchAngle: 0 deg; Reference: Trepimade1
AR_IFC_VAHELAED_PÕRANDAD - Phase Created: Existing
Name (Floor:Trepimade1:...) | In
239497 | 2 korrus
239640 | 3 korrus

# IfcSlab: Floor:Trepimade2 (3)
PredefinedType: FLOOR; Material: Betoonplaat 140 mm
Pset_SlabCommon - LoadBearing: no; IsExternal: no; PitchAngle: 0 deg; Reference: Trepimade2
AR_IFC_VAHELAED_PÕRANDAD - Phase Created: Existing
Name (Floor:Trepimade2:...) | In
239876 | 4 korrus
239885 | 4 korrus
915744 | 3 korrus

# IfcSlab: Floor:Trepimade3, Floor:Trepimade3:239076
In: Vundament
PredefinedType: FLOOR; Material: Betoonplaat 195 mm
Pset_SlabCommon - LoadBearing: no; IsExternal: no; PitchAngle: 0 deg; Reference: Trepimade3
AR_IFC_VAHELAED_PÕRANDAD - Phase Created: Existing

# IfcSlab: Floor:Trepimade4 (2)
PredefinedType: FLOOR; Material: Betoonplaat 500 mm
Pset_SlabCommon - LoadBearing: no; IsExternal: no; PitchAngle: 0 deg; Reference: Trepimade4
AR_IFC_VAHELAED_PÕRANDAD - Phase Created: Existing
Name (Floor:Trepimade4:...) | In
239470 | 2 korrus
239622 | 3 korrus

# IfcSlab: Floor:Trepimade5, Floor:Trepimade5:239479
In: 2 korrus
PredefinedType: FLOOR; Material: Betoonplaat 400 mm
Pset_SlabCommon - LoadBearing: no; IsExternal: no; PitchAngle: 0 deg; Reference: Trepimade5
AR_IFC_VAHELAED_PÕRANDAD - Phase Created: Existing

# IfcSlab: Floor:Trepimade6, Floor:Trepimade6:239858
In: 4 korrus
PredefinedType: FLOOR; Material: Betoonplaat 290 mm
Pset_SlabCommon - LoadBearing: no; IsExternal: no; PitchAngle: 0 deg; Reference: Trepimade6
AR_IFC_VAHELAED_PÕRANDAD - Phase Created: Existing

# IfcSlab: Floor:Trepimade7, Floor:Trepimade7:239867
In: 4 korrus
PredefinedType: FLOOR; Material: Betoonplaat 460 mm
Pset_SlabCommon - LoadBearing: no; IsExternal: no; PitchAngle: 0 deg; Reference: Trepimade7
AR_IFC_VAHELAED_PÕRANDAD - Phase Created: Existing

# IfcSlab: Floor:Tuulekoja põrand, Floor:Tuulekoja põrand:239092
In: Vundament
PredefinedType: FLOOR; Material: Betoon 807.1 mm
Pset_SlabCommon - LoadBearing: no; IsExternal: no; PitchAngle: 0 deg; Reference: Tuulekoja põrand
AR_IFC_VAHELAED_PÕRANDAD - Phase Created: Existing

# IfcSlab: Floor:Uus trepimade, Floor:Uus trepimade:239488
In: 2 korrus
PredefinedType: FLOOR; Material: Betoon paneel 200 mm
Pset_SlabCommon - LoadBearing: no; IsExternal: no; PitchAngle: 0 deg; Reference: Uus trepimade
AR_IFC_VAHELAED_PÕRANDAD - Phase Created: Existing

# IfcSlab: Floor:VAHELAGI - 005 (3)
PredefinedType: FLOOR
Pset_SlabCommon - LoadBearing: no; IsExternal: no; PitchAngle: 0 deg; Reference: VAHELAGI - 005
AR_IFC_VAHELAED_PÕRANDAD - Phase Created: Existing
Name (Floor:VAHELAGI - 005:...) | In | Material
239446 | 2 korrus | GENEERILINE - KONSTRUKTRIOON 1120 mm
239606 | 3 korrus | GENEERILINE - KONSTRUKTRIOON 1150.43 mm
239839 | 4 korrus | GENEERILINE - KONSTRUKTRIOON 1099.57 mm

# IfcSlab: Floor:VL-1_vahelagi olemasolevas hoones (11)
PredefinedType: FLOOR; Material: Viimistlus 20 mm, Betoon 30 mm, Helisummutusvill 30 mm, __Kergkruus 30 mm, Betoon paneel 220 mm
Pset_SlabCommon - LoadBearing: no; IsExternal: no; Reference: VL-1_vahelagi olemasolevas hoones; ThermalTransmittance: 25.3333 kg/K/s3
AR_IFC_VAHELAED_PÕRANDAD - 01.Nimetus: Vahelagi; 02.Materjal: Õõnespaneel; 03.Kategooria / tüüp: VL-1; Phase Created: Existing
Name (Floor:VL-1_vahelagi olemasolevas hoones:...) | In | PitchAngle (deg)
239409 | 2 korrus
239423 | 2 korrus | 0
239430 | 2 korrus | 0
239569 | 3 korrus | 0
239576 | 3 korrus | 0
239590 | 3 korrus | 0
239599 | 3 korrus | 0
239805 | 4 korrus | 0
239816 | 4 korrus | 0
239823 | 4 korrus | 0
239830 | 4 korrus | 0

# IfcSlab: Floor:VL-2.1_vahelagi juurdeehitusel (4)
PredefinedType: FLOOR; Material: Viimistlus 20 mm, Betoon 80 mm, Helisummutusvill 50 mm, Betoon paneel 220 mm
Pset_SlabCommon - LoadBearing: no; IsExternal: no; PitchAngle: 0 deg; Reference: VL-2.1_vahelagi juurdeehitusel
AR_IFC_VAHELAED_PÕRANDAD - 01.Nimetus: Vahelagi; 02.Materjal: Õõnespaneel; 03.Kategooria / tüüp: VL-2.1; Phase Created: New Construction
Name (Floor:VL-2.1_vahelagi juurdeehitusel:...) | In
383128 | uus 2 korrus
384074 | uus 3 korrus
924481 | uus 2 korrus
942658 | uus 3 korrus

# IfcSlab: Floor:VL-2_vahelagi ventruumis, Floor:VL-2_vahelagi ventruumis:1003093
In: Katusekorrus
PredefinedType: FLOOR; Material: Viimistlus 20 mm, Betoon 30 mm, Helisummutusvill 30 mm
Pset_SlabCommon - LoadBearing: no; IsExternal: no; Reference: VL-2_vahelagi ventruumis
AR_IFC_VAHELAED_PÕRANDAD - 01.Nimetus: Vahelagi; 02.Materjal: Õõnespaneel; 03.Kategooria / tüüp: VL-2; Phase Created: New Construction

# IfcSlab: KATUS - 002:KATUS - 002:201144, KATUS - 002:KATUS - 002:201146:1
In: Katus vent.
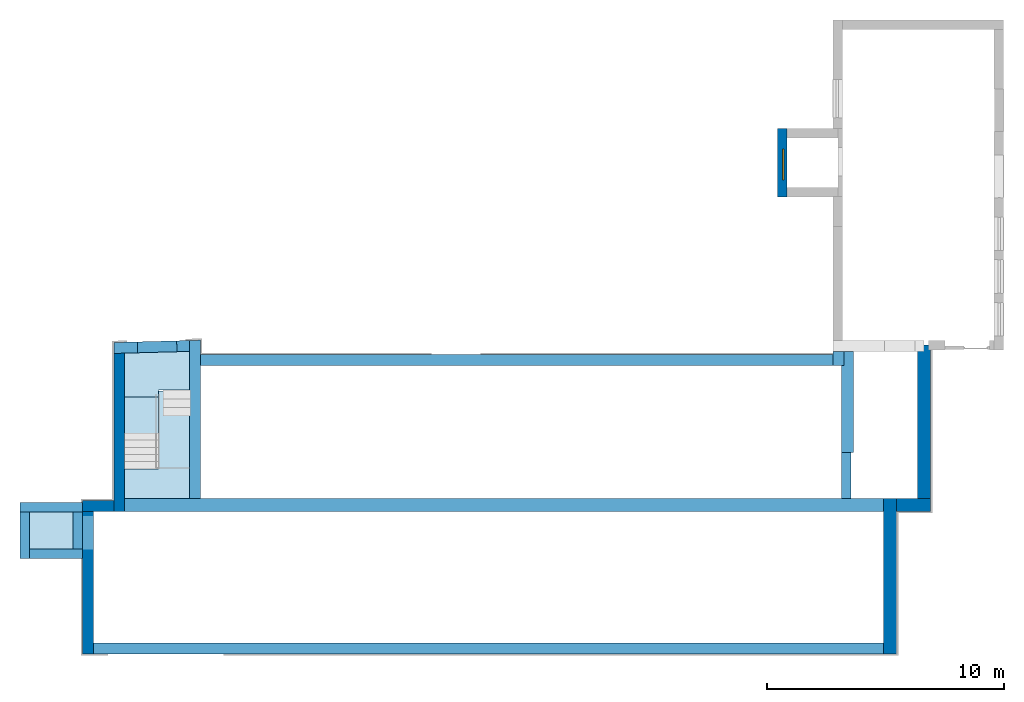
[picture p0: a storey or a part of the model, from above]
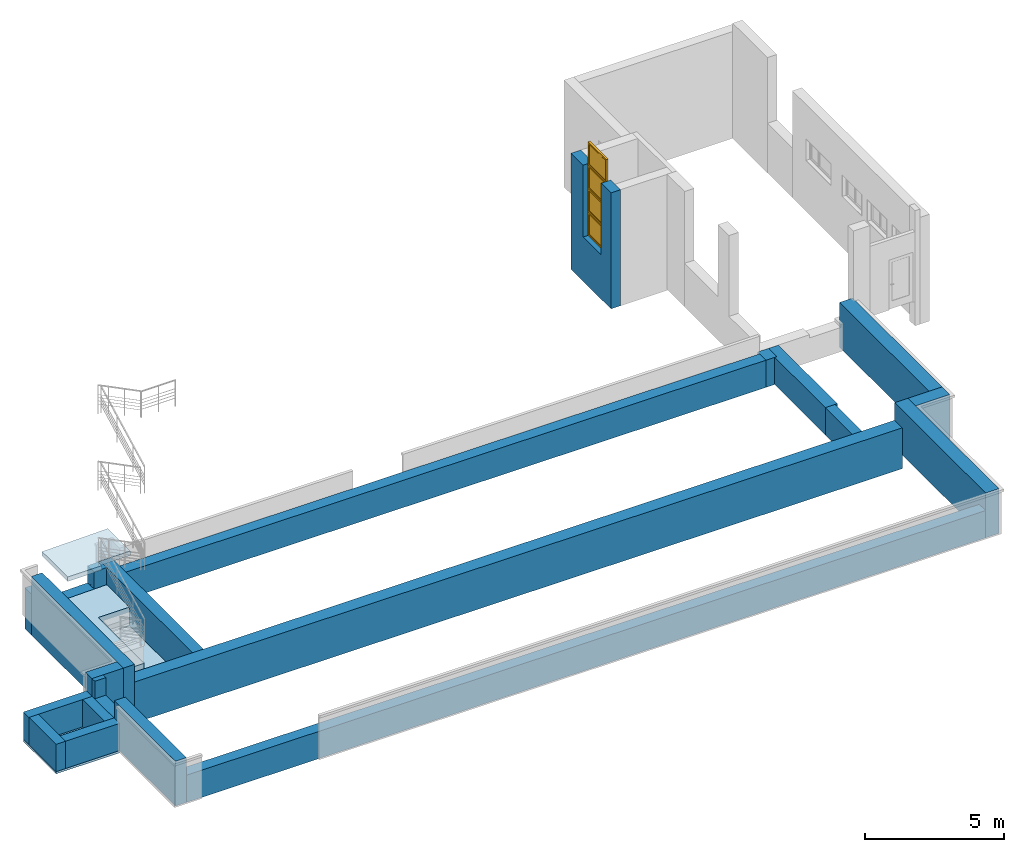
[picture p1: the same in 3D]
Properties of the parts of a building model (IFC2X3), part 4 of 5

# IfcSlab: KATUS - 002:KATUS - 002:201144, KATUS - 002:KATUS - 002:201146:1
PredefinedType: ROOF; Material: Paint - Dark Gray
Pset_SlabCommon - PitchAngle: 0 deg; IsExternal: yes; Reference: KATUS - 002
AR_IFC_KATUSED - 01.Nimetus: Lifti katus; 02.Materjal: Plekk; 03.Kategooria / tüüp: Olemasolev lifti katus; Phase Created: Existing

# IfcSlab: OBJEKT-014:OBJEKT-014, OBJEKT-014:OBJEKT-014:199931
In: 2 korrus
PredefinedType: FLOOR; Material: Paint - Sand Beige
Pset_SlabCommon - IsExternal: no; Reference: OBJEKT-014; PitchAngle: 0 deg
AR_IFC_VAHELAED_PÕRANDAD - Phase Created: Existing

# IfcSlab: Päikesesirm:päikesesirm:977803 (6)
PredefinedType: ROOF; Material: Steel/Aluminium
Pset_SlabCommon - IsExternal: no; PitchAngle: 0 deg; Reference: päikesesirm
Pset_ManufacturerTypeInformation - Manufacturer: Kawneer
Name (Päikesesirm:päikesesirm:...) | In
977846:1 | 4 korrus
978829:1 | 4 korrus
978841:1 | 4 korrus
978851:1 | 4 korrus
978900:1 | 2 korrus
979346:1 | 2 korrus

# IfcSlab: VAHELAGI - 005:VAHELAGI - 005, VAHELAGI - 005:VAHELAGI - 005:201509
In: Katus vent.
PredefinedType: FLOOR; Material: Paint - Sand Beige
Pset_SlabCommon - IsExternal: no; Reference: VAHELAGI - 005
AR_IFC_VAHELAED_PÕRANDAD - Phase Created: Existing

# IfcStair: Assembled Stair:Keerdtrepp:987047 (2)
Pset_StairCommon - IsExternal: yes; Reference: Keerdtrepp
Name (Assembled Stair:Stair:...) | In | NumberOfRiser | NumberOfTreads | RiserHeight (mm) | TreadLength (mm)
1372757 | uus 1 korrus | 18 | 18 | 187.368 | 280
1373376 | uus 2 korrus | 20 | 19 | 189.75 | 270

# IfcStair: LADDER_12760:LADDER_12760:1740343 (2)
In: 4 korrus
Name (LADDER_12760:LADDER_12760:...)
1740289 | Material: SIDE RAILS, LADDER CONNECTION, RUNGS
1740289 | Pset_StairCommon - IsExternal: no; Reference: LADDER_12760; NumberOfTreads: 19; RiserHeight: 189.75 mm; TreadLength: 270 mm

# IfcStair: OBJEKT-015:OBJEKT-015:200499 (2)
In: uus 2 korrus
Name (OBJEKT-015:OBJEKT-015:...)
200501 | Material: Paint - Sand Beige
200501 | Pset_StairCommon - IsExternal: no; Reference: OBJEKT-015; NumberOfTreads: 0

# IfcStair: OBJEKT-016:OBJEKT-016:200513 (2)
In: uus 2 korrus
Name (OBJEKT-016:OBJEKT-016:...)
200515 | Material: Paint - Sand Beige
200515 | Pset_StairCommon - IsExternal: no; Reference: OBJEKT-016; NumberOfTreads: 0

# IfcStair: OBJEKT-017:OBJEKT-017:201007 (2)
In: uus 3 korrus
Name (OBJEKT-017:OBJEKT-017:...)
201009 | Material: Paint - Sand Beige
201009 | Pset_StairCommon - IsExternal: no; Reference: OBJEKT-017; NumberOfTreads: 0

# IfcStair: OBJEKT-018:OBJEKT-018:201021 (2)
In: uus 3 korrus
Name (OBJEKT-018:OBJEKT-018:...)
201023 | Material: Paint - Sand Beige
201023 | Pset_StairCommon - IsExternal: no; Reference: OBJEKT-018; NumberOfTreads: 0

# IfcStair: OBJEKT-019:OBJEKT-019:200570 (2)
In: uus 3 korrus
Name (OBJEKT-019:OBJEKT-019:...)
200572 | Material: Paint - Sand Beige
200572 | Pset_StairCommon - IsExternal: no; Reference: OBJEKT-019; NumberOfTreads: 0

# IfcStair: OBJEKT-020 87690:OBJEKT-020 87690:200486 (2)
In: uus 2 korrus
Name (OBJEKT-020 87690:OBJEKT-020 87690:...)
200488 | Material: Paint - Sand Beige
200488 | Pset_StairCommon - IsExternal: no; Reference: OBJEKT-020 87690; NumberOfTreads: 0

# IfcStair: OBJEKT-020:OBJEKT-020:200030 (2)
In: uus 2 korrus
Name (OBJEKT-020:OBJEKT-020:...)
200032 | Material: Paint - Sand Beige
200032 | Pset_StairCommon - IsExternal: no; Reference: OBJEKT-020; NumberOfTreads: 0

# IfcStair: Precast Stair:Uus betoonist sisestrepp 2:898452, Precast Stair:Stair:898408
In: uus 1 korrus
Pset_StairCommon - IsExternal: yes; Reference: Uus betoonist sisestrepp 2; NumberOfRiser: 2; NumberOfTreads: 2; RiserHeight: 150 mm; TreadLength: 300 mm

# IfcStair: Precast Stair:Uus betoonist sisestrepp 3:925599, Precast Stair:Stair:925587
In: uus 2 korrus
Pset_StairCommon - IsExternal: yes; Reference: Uus betoonist sisestrepp 3; NumberOfRiser: 7; NumberOfTreads: 7; RiserHeight: 153.571 mm; TreadLength: 300 mm

# IfcStair: Precast Stair:Uus betoonist sisestrepp 4:942739, Precast Stair:Stair:942737
In: uus 3 korrus
Pset_StairCommon - IsExternal: yes; Reference: Uus betoonist sisestrepp 4; NumberOfRiser: 5; NumberOfTreads: 5; RiserHeight: 150 mm; TreadLength: 300 mm

# IfcStair: Precast Stair:Uus betoonist sisestrepp:836185, Precast Stair:Stair:836183
In: 1 korrus
Pset_StairCommon - IsExternal: yes; Reference: Uus betoonist sisestrepp; NumberOfRiser: 5; NumberOfTreads: 4; RiserHeight: 147 mm; TreadLength: 400 mm

# IfcStair: Precast Stair:Uus betoonist välistrepp:833109, Precast Stair:Stair:834397
In: 1 korrus
Pset_StairCommon - IsExternal: yes; Reference: Uus betoonist välistrepp; NumberOfRiser: 4; NumberOfTreads: 4; RiserHeight: 131.25 mm; TreadLength: 400 mm

# IfcStair: TR KONSTRUKTSIOON - 001 116686:TR KONSTRUKTSIOON - 001 116686:200583 (2)
In: uus 2 korrus
Name (TR KONSTRUKTSIOON - 001 116686:TR KONSTRUKTSIOON - 001 116686:...)
200585 | Material: Paint - Sand Beige
200585 | Pset_StairCommon - IsExternal: no; Reference: TR KONSTRUKTSIOON - 001 116686; NumberOfTreads: 0

# IfcStair: TR KONSTRUKTSIOON - 001 119095:TR KONSTRUKTSIOON - 001 119095:200689 (2)
In: uus 2 korrus
Name (TR KONSTRUKTSIOON - 001 119095:TR KONSTRUKTSIOON - 001 119095:...)
200691 | Material: Paint - Sand Beige
200691 | Pset_StairCommon - IsExternal: no; Reference: TR KONSTRUKTSIOON - 001 119095; NumberOfTreads: 0

# IfcStair: TR KONSTRUKTSIOON - 001 121584:TR KONSTRUKTSIOON - 001 121584:200795 (2)
In: uus 2 korrus
Name (TR KONSTRUKTSIOON - 001 121584:TR KONSTRUKTSIOON - 001 121584:...)
200797 | Material: Paint - Sand Beige
200797 | Pset_StairCommon - IsExternal: no; Reference: TR KONSTRUKTSIOON - 001 121584; NumberOfTreads: 0

# IfcStair: TR KONSTRUKTSIOON - 001 123993:TR KONSTRUKTSIOON - 001 123993:200901 (2)
In: uus 2 korrus
Name (TR KONSTRUKTSIOON - 001 123993:TR KONSTRUKTSIOON - 001 123993:...)
200903 | Material: Paint - Sand Beige
200903 | Pset_StairCommon - IsExternal: no; Reference: TR KONSTRUKTSIOON - 001 123993; NumberOfTreads: 0

# IfcStair: TR KONSTRUKTSIOON - 001 155075:TR KONSTRUKTSIOON - 001 155075:201172 (2)
In: uus 3 korrus
Name (TR KONSTRUKTSIOON - 001 155075:TR KONSTRUKTSIOON - 001 155075:...)
201174 | Material: Paint - Sand Beige
201174 | Pset_StairCommon - IsExternal: no; Reference: TR KONSTRUKTSIOON - 001 155075; NumberOfTreads: 0

# IfcStair: TR KONSTRUKTSIOON - 001 157626:TR KONSTRUKTSIOON - 001 157626:201278 (2)
In: uus 3 korrus
Name (TR KONSTRUKTSIOON - 001 157626:TR KONSTRUKTSIOON - 001 157626:...)
201280 | Material: Paint - Sand Beige
201280 | Pset_StairCommon - IsExternal: no; Reference: TR KONSTRUKTSIOON - 001 157626; NumberOfTreads: 0

# IfcStair: TR KONSTRUKTSIOON - 001 43229:TR KONSTRUKTSIOON - 001 43229:199538 (2)
In: uus 1 korrus
Name (TR KONSTRUKTSIOON - 001 43229:TR KONSTRUKTSIOON - 001 43229:...)
199540 | Material: Paint - Sand Beige
199540 | Pset_StairCommon - IsExternal: no; Reference: TR KONSTRUKTSIOON - 001 43229; NumberOfTreads: 0

# IfcStair: TR KONSTRUKTSIOON - 001 44406:TR KONSTRUKTSIOON - 001 44406:199644 (2)
In: Vundament
Name (TR KONSTRUKTSIOON - 001 44406:TR KONSTRUKTSIOON - 001 44406:...)
199646 | Material: Paint - Sand Beige
199646 | Pset_StairCommon - IsExternal: no; Reference: TR KONSTRUKTSIOON - 001 44406; NumberOfTreads: 0

# IfcStair: TR KONSTRUKTSIOON - 001 45625:TR KONSTRUKTSIOON - 001 45625:199713 (2)
In: Vundament
Name (TR KONSTRUKTSIOON - 001 45625:TR KONSTRUKTSIOON - 001 45625:...)
199715 | Material: Paint - Sand Beige
199715 | Pset_StairCommon - IsExternal: no; Reference: TR KONSTRUKTSIOON - 001 45625; NumberOfTreads: 0

# IfcStair: TR KONSTRUKTSIOON - 001 46686:TR KONSTRUKTSIOON - 001 46686:199733 (2)
In: 1 korrus
Name (TR KONSTRUKTSIOON - 001 46686:TR KONSTRUKTSIOON - 001 46686:...)
199735 | Material: Paint - Sand Beige
199735 | Pset_StairCommon - IsExternal: no; Reference: TR KONSTRUKTSIOON - 001 46686; NumberOfTreads: 0

# IfcStair: TR KONSTRUKTSIOON - 001 78655:TR KONSTRUKTSIOON - 001 78655:200089 (2)
In: 1 korrus
Name (TR KONSTRUKTSIOON - 001 78655:TR KONSTRUKTSIOON - 001 78655:...)
200091 | Material: Paint - Sand Beige
200091 | Pset_StairCommon - IsExternal: no; Reference: TR KONSTRUKTSIOON - 001 78655; NumberOfTreads: 0

# IfcStair: TR KONSTRUKTSIOON - 001 81467:TR KONSTRUKTSIOON - 001 81467:200195 (2)
In: 1 korrus
Name (TR KONSTRUKTSIOON - 001 81467:TR KONSTRUKTSIOON - 001 81467:...)
200197 | Material: Paint - Sand Beige
200197 | Pset_StairCommon - IsExternal: no; Reference: TR KONSTRUKTSIOON - 001 81467; NumberOfTreads: 0

# IfcStair: TR KONSTRUKTSIOON - 001 84430:TR KONSTRUKTSIOON - 001 84430:200301 (2)
In: 1 korrus
Name (TR KONSTRUKTSIOON - 001 84430:TR KONSTRUKTSIOON - 001 84430:...)
200303 | Material: Paint - Sand Beige
200303 | Pset_StairCommon - IsExternal: no; Reference: TR KONSTRUKTSIOON - 001 84430; NumberOfTreads: 0

# IfcStair: TR KONSTRUKTSIOON - 001 86768:TR KONSTRUKTSIOON - 001 86768:200407 (2)
In: 1 korrus
Name (TR KONSTRUKTSIOON - 001 86768:TR KONSTRUKTSIOON - 001 86768:...)
200409 | Material: Paint - Sand Beige
200409 | Pset_StairCommon - IsExternal: no; Reference: TR KONSTRUKTSIOON - 001 86768; NumberOfTreads: 0

# IfcStairFlight: Assembled Stair:Keerdtrepp:987047 (2)
Material: Metal - Galvanized
Pset_StairFlightCommon - NosingLength: 0 mm; Reference: 50 mm Tread 13 mm Riser (1); WalkingLineOffset: 450 mm; WaistThickness: 900 mm
Name (Assembled Stair:Stair:...) | In | NumberOfRiser = Pset_StairFlightCommon, NumberOfRiser | NumberOfTreads = Pset_StairFlightCommon, NumberOfTreads | RiserHeight (mm) | TreadLength (mm) | Pset_StairFlightCommon, RiserHeight (mm) | Pset_StairFlightCommon, TreadLength (mm) = TreadLengthAtOffset (mm)
1372757 Run 1 | uus 1 korrus | 18 | 18 | 0.614726 | 0.918635 | 187.368 | 280
1373376 Run 1 | uus 2 korrus | 20 | 19 | 0.622539 | 0.885827 | 189.75 | 270

# IfcStairFlight: Precast Stair:Uus betoonist sisestrepp 2:898452, Precast Stair:Stair:898408 Run 1
In: uus 1 korrus
NumberOfRiser: 2; NumberOfTreads: 2; RiserHeight: 0.492126 mm; TreadLength: 0.984252 mm
Pset_StairFlightCommon - Reference: Monolithic Run 150mm; NosingLength: 0 mm; NumberOfRiser: 2; NumberOfTreads: 2; RiserHeight: 150 mm; TreadLength: 300 mm; TreadLengthAtOffset: 300 mm; WalkingLineOffset: 800 mm; WaistThickness: 1600 mm

# IfcStairFlight: Precast Stair:Uus betoonist sisestrepp 3:925599, Precast Stair:Stair:925587 Run 1
In: uus 2 korrus
NumberOfRiser: 7; NumberOfTreads: 7; RiserHeight: 0.503843 mm; TreadLength: 0.984252 mm
Pset_StairFlightCommon - Reference: Monolithic Run 150mm; NosingLength: 0 mm; NumberOfRiser: 7; NumberOfTreads: 7; RiserHeight: 153.571 mm; TreadLength: 300 mm; TreadLengthAtOffset: 300 mm; WalkingLineOffset: 800 mm; WaistThickness: 1600 mm

# IfcStairFlight: Precast Stair:Uus betoonist sisestrepp 4:942739, Precast Stair:Stair:942737 Run 1
In: uus 3 korrus
NumberOfRiser: 5; NumberOfTreads: 5; RiserHeight: 0.492126 mm; TreadLength: 0.984252 mm
Pset_StairFlightCommon - Reference: Monolithic Run 150mm; NosingLength: 0 mm; NumberOfRiser: 5; NumberOfTreads: 5; RiserHeight: 150 mm; TreadLength: 300 mm; TreadLengthAtOffset: 300 mm; WalkingLineOffset: 800 mm; WaistThickness: 1600 mm

# IfcStairFlight: Precast Stair:Uus betoonist sisestrepp:836185, Precast Stair:Stair:836183 Run 1
In: 1 korrus
NumberOfRiser: 5; NumberOfTreads: 4; RiserHeight: 0.482283 mm; TreadLength: 1.31234 mm
Pset_StairFlightCommon - Reference: Monolithic Run 150mm; NosingLength: 0 mm; NumberOfRiser: 5; NumberOfTreads: 4; RiserHeight: 147 mm; TreadLength: 400 mm; TreadLengthAtOffset: 400 mm

# IfcStairFlight: Precast Stair:Uus betoonist välistrepp:833109, Precast Stair:Stair:834397 Run 1
In: 1 korrus
NumberOfRiser: 4; NumberOfTreads: 4; RiserHeight: 0.43061 mm; TreadLength: 1.31234 mm
Pset_StairFlightCommon - Reference: Monolithic Run 150mm; NumberOfRiser: 4; NumberOfTreads: 4; RiserHeight: 131.25 mm; TreadLength: 400 mm; TreadLengthAtOffset: 400 mm; NosingLength: 0 mm; WalkingLineOffset: 881.921 mm; WaistThickness: 1763.84 mm

# IfcTransportElement: 1100 x 1467 - 536 (3)
Type - Material: Kalea_glass, Kalea_glass_black, Kalea_RAL_9016
CapacityByWeight: 0 kg; CapacityByNumber: 0
Pset_ManufacturerTypeInformation - Manufacturer: (c) 2015 - Kalea Lifts AB
Name (C-side_Glass Panel:1100 x 1467 - 536:...) | In
1767882 | Katusekorrus
1767890 | 1 korrus
1767915 | 4 korrus

# IfcTransportElement: 1100 x 1467 - 805 (3)
Type - Material: Kalea_glass, Kalea_glass_black, Kalea_RAL_9016
CapacityByWeight: 0 kg; CapacityByNumber: 0
Pset_ManufacturerTypeInformation - Manufacturer: (c) 2015 - Kalea Lifts AB
Name (A-side_Glass Panel:1100 x 1467 - 805:...) | In
1767869 | 203
1767871 | 303
1767905 | 103

# IfcTransportElement: 1100 x 1467 - Left hinged (5)
Type - Material: Kalea_RAL_9016
CapacityByWeight: 0 kg; CapacityByNumber: 0
Pset_ManufacturerTypeInformation - Manufacturer: (c) 2015 - Kalea Lifts AB
Name (A-side_Door_EI60G:1100 x 1467 - Left hinged:...) | In
1767868 | 2 korrus
1767870 | 3 korrus
1767880 | 4 korrus
1767881 | Katusekorrus
1767895 | 1 korrus

# IfcTransportElement: 1100 x 1467 - Standard Height (904 mm) (16)
In: 1 korrus
Type - Material: Kalea_glass, Kalea_glass_black, Kalea_RAL_9016
CapacityByWeight: 0 kg; CapacityByNumber: 0
Pset_ManufacturerTypeInformation - Manufacturer: (c) 2015 - Kalea Lifts AB
Name (C-side_Glass Panel:1100 x 1467 - Standard Height (904 mm):...)
1767876
1767877
1767878
1767879
1767887
1767888
1767889
1767896
1767897
1767898
1767899
1767900
1767901
1767906
1767907
1767908

# IfcTransportElement: 1100x1467, Lift:1100x1467:1767892
In: 1 korrus
Type - Material: Kalea_RAL_9016_Traffic White, Kalea_Chrome, Kalea_seat_wood, Kalea_metal_construction, Kalea_floor_rubber, Kalea_template_solid, Kalea_lifting_screw
CapacityByWeight: 0 kg; CapacityByNumber: 0
Pset_ManufacturerTypeInformation - Manufacturer: Cibes Lift AB

# IfcTransportElement: 1100x1467 - 536 (2)
In: 1 korrus
Type - Material: Kalea_RAL_9016_Traffic White, Kalea_glass
CapacityByWeight: 0 kg; CapacityByNumber: 0
Pset_ManufacturerTypeInformation - Manufacturer: (c) 2015 - Kalea Lifts AB
Name (B-side_Glass Panel:1100x1467 - 536:...)
1767886
1767924

# IfcTransportElement: 1100x1467 - Standard Height (904 mm) (34)
In: 1 korrus
Type - Material: Kalea_RAL_9016_Traffic White, Kalea_glass
CapacityByWeight: 0 kg; CapacityByNumber: 0
Pset_ManufacturerTypeInformation - Manufacturer: (c) 2015 - Kalea Lifts AB
Name (B-side_Glass Panel:1100x1467 - Standard Height (904 mm):...)
1767872
1767873
1767874
1767875
1767883
1767884
1767885
1767902
1767903
1767904
1767909
1767910
1767911
1767912
1767913
1767914
1767916
1767917
1767918
1767919
1767920
1767921
1767922
1767923
1767925
1767926
1767927
1767928
1767929
1767930
1767931
1767932
1767933
1767934

# IfcTransportElement: KONE_Buffer_Extension_KM812340G06 (2)
In: uus 1 korrus
OperationType: ELEVATOR; CapacityByWeight: 0 kg; CapacityByNumber: 0
Name (KONE_Buffer_Extension_KM812340G06_CAR:KONE_Buffer_Extension_KM812340G06:...)
1652577
1652578

# IfcTransportElement: KONE_Buffer_PU_125x80D (2)
In: uus 1 korrus
OperationType: ELEVATOR; CapacityByWeight: 0 kg; CapacityByNumber: 0
Name (KONE_Buffer_PU_125x80D_CAR:KONE_Buffer_PU_125x80D:...)
1652575
1652576

# IfcTransportElement: KONE_CWT, KONE_CWT:KONE_CWT:1652570
In: 226a
OperationType: ELEVATOR; CapacityByWeight: 0 kg; CapacityByNumber: 0

# IfcTransportElement: KONE_CWT_Bracket_KM51010607V000_L97-565_LH (7)
OperationType: ELEVATOR; CapacityByWeight: 0 kg; CapacityByNumber: 0
Name (KONE_CWT_Bracket_KM51010607V000_L97-565_LH:KONE_CWT_Bracket_KM51010607V000_L97-565_LH:...) | In
1652599 | uus 1 korrus
1652600 | 132a
1652601 | uus 1 korrus
1652602 | 226a
1652603 | uus 1 korrus
1652604 | 327a
1652605 | 327a

# IfcTransportElement: KONE_CWT_guiderail (2)
In: 226a
OperationType: ELEVATOR; CapacityByWeight: 0 kg; CapacityByNumber: 0
Name (KONE_CWT_guiderail:KONE_CWT_guiderail:...)
1652571
1652572

# IfcTransportElement: KONE_Car, KONE_Car:KONE_Car:1652562
In: 132a
Type - Material: Stainless Steel-KONE-KONE Blue, Stainless Steel-KONE-Stainless Steel
OperationType: ELEVATOR; CapacityByWeight: 0 kg; CapacityByNumber: 0

# IfcTransportElement: KONE_Car_Bracket_Extension_KM755828G01_L115 (7)
Type - Material: Generic
OperationType: ELEVATOR; CapacityByWeight: 0 kg; CapacityByNumber: 0
Name (KONE_Car_Bracket_Extension_KM755828G01_L115:KONE_Car_Bracket_Extension_KM755828G01_L115:...) | In
1652586 | uus 1 korrus
1652588 | 132a
1652590 | uus 1 korrus
1652592 | 226a
1652594 | uus 1 korrus
1652596 | 327a
1652598 | 327a

# IfcTransportElement: KONE_Car_Bracket_KM51029396V001_L184-394 (7)
Type - Material: Generic
OperationType: ELEVATOR; CapacityByWeight: 0 kg; CapacityByNumber: 0
Name (KONE_Car_Bracket_KM51029396V001_L184-394:KONE_Car_Bracket_KM51029396V001_L184-394:...) | In
1652585 | uus 1 korrus
1652587 | 132a
1652589 | uus 1 korrus
1652591 | 226a
1652593 | uus 1 korrus
1652595 | 327a
1652597 | 327a

# IfcTransportElement: KONE_Car_Door_2L_Glass, KONE_Car_Door_2L_Glass:KONE_Car_Door_2L_Glass:1652564
In: 132a
Type - Material: Glass
OperationType: ELEVATOR; CapacityByWeight: 0 kg; CapacityByNumber: 0

# IfcTransportElement: KONE_Car_guiderail (2)
In: 226a
OperationType: ELEVATOR; CapacityByWeight: 0 kg; CapacityByNumber: 0
Name (KONE_Car_guiderail:KONE_Car_guiderail:...)
1652560
1652561

# IfcTransportElement: KONE_Combination_Bracket_KM51029396V002_L184-394_LH (7)
Type - Material: Generic
OperationType: ELEVATOR; CapacityByWeight: 0 kg; CapacityByNumber: 0
Name (KONE_Combination_Bracket_KM51029396V002_L184-394_LH:KONE_Combination_Bracket_KM51029396V002_L184-394_LH:...) | In
1652606 | uus 1 korrus
1652607 | 132a
1652608 | uus 1 korrus
1652609 | 226a
1652610 | uus 1 korrus
1652611 | 327a
1652612 | 327a

# IfcTransportElement: KONE_DRIVE_KDL16S_M500_Wall_Fixed_Short_Backplate_KCE_LH, KONE_DRIVE_KDL16S_M500_Wall_Fixed_Short_Backplate_KCE_LH:KONE_DRIVE_KDL16S_M500_Wall_Fixed_Short_Backplate_KCE_LH:1652616
In: 226a
OperationType: ELEVATOR; CapacityByWeight: 0 kg; CapacityByNumber: 0

# IfcTransportElement: KONE_Hook_Embedded (3)
In: uus 1 korrus
Type - Material: Site specified, Void
OperationType: ELEVATOR; CapacityByWeight: 0 kg; CapacityByNumber: 0
Name (KONE_Hook_Embedded:KONE_Hook_Embedded:...)
1652613
1652614
1652615

# IfcTransportElement: KONE_MACHINE_NMX11_MONO, KONE_MACHINE_NMX11_MONO:KONE_MACHINE_NMX11_MONO:1652563
In: 327a
Type - Material: Machine_Green
OperationType: ELEVATOR; CapacityByWeight: 0 kg; CapacityByNumber: 0

# IfcTransportElement: KONE_Pit_Ladder, KONE_Pit_Ladder:KONE_Pit_Ladder:1652567
In: 132a
Type - Material: Site specified
OperationType: ELEVATOR; CapacityByWeight: 0 kg; CapacityByNumber: 0

# IfcTransportElement: KONE_Shaft_Light, KONE_Shaft_Light:KONE_Shaft_Light:1652568
In: uus 1 korrus
Type - Material: Site specified
OperationType: ELEVATOR; CapacityByWeight: 0 kg; CapacityByNumber: 0

# IfcTransportElement: KONE_Wire_Channel, KONE_Wire_Channel:KONE_Wire_Channel:1652569
In: 132a
Type - Material: Site specified
OperationType: ELEVATOR; CapacityByWeight: 0 kg; CapacityByNumber: 0

# IfcWall: Basic Wall:VS-2.2_Juurdeehituse välissein (3)
Type - PredefinedType: STANDARD; Material: __Tuuletõkkeplaat 9 mm, __Soojustus EPS 200 mm, __Kergblokk 190 mm
Pset_WallCommon - LoadBearing: no; ExtendToStructure: no; IsExternal: yes; Reference: VS-2.2_Juurdeehituse välissein; ThermalTransmittance: 4 kg/K/s3
AR_IFC_SEINAD - 01.Nimetus: Välissein; 02.Materjal: Columbia kivi; 03.Kategooria / tüüp: VS-2.2; 04.Tulepüsivus: REI-60; 05.Asukoha info: Exterior; 06.Kandevelementide eristatud: bearing; 07.Helipidavus: 56dB; 06.Soojusläbivus: 0,15W/m2K; Phase Created: New Construction
Name (Basic Wall:VS-2.2_Juurdeehituse välissein:...) | In
377149 | uus 2 korrus
933159 | uus 3 korrus
1302768 | uus 3 korrus

# IfcWall: GENEERILINE - KONSTRUKTRIOON 300 x 685:GENEERILINE - KONSTRUKTRIOON 300 x 685, GENEERILINE - KONSTRUKTRIOON 300 x 685:GENEERILINE - KONSTRUKTRIOON 300 x 685:239030
In: 1 korrus
Type - Material: Betoon
Pset_WallCommon - ExtendToStructure: no; IsExternal: no; LoadBearing: yes; Reference: GENEERILINE - KONSTRUKTRIOON 300 x 685
AR_IFC_SEINAD - Phase Created: Existing

# IfcWall: OBJEKT-013, OBJEKT-013:OBJEKT-013:199924
In: 1 korrus
Type - Material: Paint - Light Gray
Pset_WallCommon - LoadBearing: no; ExtendToStructure: no; IsExternal: no; Reference: OBJEKT-013
AR_IFC_SEINAD - 01.Nimetus: Sisesein; 02.Materjal: Silikaattellis; 03.Kategooria / tüüp: SS-1; 04.Tulepüsivus: EI-60; 05.Asukoha info: Interior; 06.Kandevelementide eristatud: bearing; 07.Helipidavus: 48dB; 06.Soojusläbivus: -; Phase Created: Existing

# IfcWall: RB_karniis1:RB_karniis, RB_karniis1:RB_karniis:982825
In: uus Katus
Type - Material: Krohv
Pset_WallCommon - LoadBearing: no; ExtendToStructure: no; IsExternal: no; Reference: RB_karniis

# IfcWall: RB_karniis2:RB_karniis, RB_karniis2:RB_karniis:983191
In: uus Katus
Type - Material: Krohv
Pset_WallCommon - LoadBearing: no; ExtendToStructure: no; IsExternal: no; Reference: RB_karniis

# IfcWall: RB_karniis:RB_karniis, RB_karniis:RB_karniis:980458
In: uus Katus
Type - Material: Krohv
Pset_WallCommon - LoadBearing: no; ExtendToStructure: no; IsExternal: no; Reference: RB_karniis

# IfcWall: SEIN - 006 (5)
Type - Material: Paint - Sand Beige
Pset_WallCommon - LoadBearing: no; ExtendToStructure: no; IsExternal: no
AR_IFC_SEINAD - 01.Nimetus: Ol.olev liftišahti sein; 02.Materjal: Silikaattellis; 03.Kategooria / tüüp: -; 04.Tulepüsivus: EI-60; 05.Asukoha info: Exterior; 06.Kandevelementide eristatud: bearing; 07.Helipidavus: -; 06.Soojusläbivus: -; Phase Created: Existing
Name | In | Reference
SEIN - 006:SEIN - 006:199405 | 1 korrus | SEIN - 006
SEIN - 006 48900:SEIN - 006 48900:199963 | 2 korrus | SEIN - 006 48900
SEIN - 006 125756:SEIN - 006 125756:201055 | 3 korrus | SEIN - 006 125756
SEIN - 006 159147:SEIN - 006 159147:201404 | 4 korrus | SEIN - 006 159147
SEIN - 006 159396:SEIN - 006 159396:201418 | Katusekorrus | SEIN - 006 159396

# IfcWall: SEIN - 008 (5)
Type - Material: Paint - Sand Beige
Pset_WallCommon - LoadBearing: no; ExtendToStructure: no; IsExternal: no
AR_IFC_SEINAD - 01.Nimetus: Ol.olev liftišahti sein; 02.Materjal: Silikaattellis; 03.Kategooria / tüüp: -; 04.Tulepüsivus: EI-60; 05.Asukoha info: Exterior; 06.Kandevelementide eristatud: bearing; 07.Helipidavus: -; 06.Soojusläbivus: -; Phase Created: Existing
Name | In | Reference
SEIN - 008:SEIN - 008:199415 | 1 korrus | SEIN - 008
SEIN - 008 48780:SEIN - 008 48780:199945 | 2 korrus | SEIN - 008 48780
SEIN - 008 125636:SEIN - 008 125636:201037 | 3 korrus | SEIN - 008 125636
SEIN - 008 159027:SEIN - 008 159027:201386 | 4 korrus | SEIN - 008 159027
SEIN - 008 159267:SEIN - 008 159267:201411 | Katusekorrus | SEIN - 008 159267

# IfcWall: TALA - 009, TALA - 009:TALA - 009:199309
In: Vundament
Type - Material: Paint - Sand Beige
Pset_WallCommon - Reference: TALA - 009; LoadBearing: no; ExtendToStructure: no; IsExternal: no
AR_IFC_SEINAD - 01.Nimetus: Välissein; 02.Materjal: Paekivi; 03.Kategooria / tüüp: -; 04.Tulepüsivus: -; 05.Asukoha info: Exterior; 06.Kandevelementide eristatud: nonbearing; 07.Helipidavus: -; 06.Soojusläbivus: -; Phase Created: Existing

# IfcWall: fassaad1.1:fassaad 2, fassaad1.1:fassaad 2:1731952
In: uus 1 korrus
Type - Material: Steel/Aluminium
Pset_WallCommon - LoadBearing: no; ExtendToStructure: no; IsExternal: no; Reference: fassaad 2

# IfcWall: fassaad1.2:fassaad 2, fassaad1.2:fassaad 2:1733869
In: uus 2 korrus
Type - Material: Steel/Aluminium
Pset_WallCommon - LoadBearing: no; ExtendToStructure: no; IsExternal: no; Reference: fassaad 2

# IfcWall: fassaad1.3:fassaad 2, fassaad1.3:fassaad 2:1735820
In: uus 3 korrus
Type - Material: Steel/Aluminium
Pset_WallCommon - LoadBearing: no; ExtendToStructure: no; IsExternal: no; Reference: fassaad 2

# IfcWall: fassaad1.4:fassaad 2, fassaad1.4:fassaad 2:1738283
In: uus Katus
Type - Material: Steel/Aluminium
Pset_WallCommon - LoadBearing: no; ExtendToStructure: no; IsExternal: no; Reference: fassaad 2

# IfcWall: fassaad10.1:fassaad10.1, fassaad10.1:fassaad10.1:1696505
In: 3 korrus
Type - Material: Steel/Aluminium
Pset_WallCommon - LoadBearing: no; ExtendToStructure: no; IsExternal: no; Reference: fassaad10.1

# IfcWall: fassaad10.2:fassaad10.2, fassaad10.2:fassaad10.2:1696506
In: 2 korrus
Type - Material: Steel/Aluminium
Pset_WallCommon - LoadBearing: no; ExtendToStructure: no; IsExternal: no; Reference: fassaad10.2

# IfcWall: fassaad10:fassaad10, fassaad10:fassaad10:1696504
In: 4 korrus
Type - Material: Steel/Aluminium
Pset_WallCommon - LoadBearing: no; ExtendToStructure: no; IsExternal: no; Reference: fassaad10

# IfcWall: fassaad15:fassaad 2, fassaad15:fassaad 2:1654816
In: 1 korrus
Type - Material: Steel/Aluminium
Pset_WallCommon - LoadBearing: no; ExtendToStructure: no; IsExternal: no; Reference: fassaad 2

# IfcWall: fassaad16:fassaad 2 (2)
In: 1 korrus
Type - Material: Steel/Aluminium
Pset_WallCommon - LoadBearing: no; ExtendToStructure: no; IsExternal: no; Reference: fassaad 2
Name (fassaad16:fassaad 2:...)
1666413
1667527

# IfcWall: fassaad2.1:fassaad2.1, fassaad2.1:fassaad2.1:1728479
In: uus 1 korrus
Type - Material: Steel/Aluminium
Pset_WallCommon - LoadBearing: no; ExtendToStructure: no; IsExternal: no; Reference: fassaad2.1

# IfcWall: fassaad2.2:fassaad2.2, fassaad2.2:fassaad2.2:1728604
In: uus 2 korrus
Type - Material: Steel/Aluminium
Pset_WallCommon - LoadBearing: no; ExtendToStructure: no; IsExternal: no; Reference: fassaad2.2

# IfcWall: fassaad2:fassaad2, fassaad2:fassaad2:1729582
In: uus 3 korrus
Type - Material: Steel/Aluminium
Pset_WallCommon - LoadBearing: no; ExtendToStructure: no; IsExternal: no; Reference: fassaad2

# IfcWall: fassaad3.1:fassaad3.1, fassaad3.1:fassaad3.1:1719221
In: uus 1 korrus
Type - Material: Steel/Aluminium
Pset_WallCommon - LoadBearing: no; ExtendToStructure: no; IsExternal: no; Reference: fassaad3.1

# IfcWall: fassaad3.2:fassaad3.2, fassaad3.2:fassaad3.2:1724960
In: uus 2 korrus
Type - Material: Steel/Aluminium
Pset_WallCommon - LoadBearing: no; ExtendToStructure: no; IsExternal: no; Reference: fassaad3.2

# IfcWall: fassaad3.3:fassaad3.3, fassaad3.3:fassaad3.3:1726745
In: uus 3 korrus
Type - Material: Steel/Aluminium
Pset_WallCommon - LoadBearing: no; ExtendToStructure: no; IsExternal: no; Reference: fassaad3.3

# IfcWall: fassaad3:fassaad3, fassaad3:fassaad3:402731
In: uus Katus
Type - Material: Steel/Aluminium
Pset_WallCommon - LoadBearing: no; IsExternal: no; ExtendToStructure: yes; Reference: fassaad3

# IfcWall: fassaad4.1:fassaad4.1, fassaad4.1:fassaad4.1:1715753
In: uus Katus
Type - Material: Steel/Aluminium
Pset_WallCommon - LoadBearing: no; ExtendToStructure: no; IsExternal: no; Reference: fassaad4.1

# IfcWall: fassaad4.2:fassaad4.2, fassaad4.2:fassaad4.2:1716619
In: uus 3 korrus
Type - Material: Steel/Aluminium
Pset_WallCommon - LoadBearing: no; ExtendToStructure: no; IsExternal: no; Reference: fassaad4.2

# IfcWall: fassaad4.3:fassaad4.3, fassaad4.3:fassaad4.3:1717497
In: uus 2 korrus
Type - Material: Steel/Aluminium
Pset_WallCommon - LoadBearing: no; ExtendToStructure: no; IsExternal: no; Reference: fassaad4.3

# IfcWall: fassaad4:fassaad4, fassaad4:fassaad4:407674
In: uus 1 korrus
Type - Material: Steel/Aluminium
Pset_WallCommon - LoadBearing: no; IsExternal: no; ExtendToStructure: yes; Reference: fassaad4

# IfcWall: fassaad5.1:fassaad5.1, fassaad5.1:fassaad5.1:1703911
In: 3 korrus
Type - Material: Steel/Aluminium
Pset_WallCommon - LoadBearing: no; ExtendToStructure: no; IsExternal: no; Reference: fassaad5.1

# IfcWall: fassaad5.2:fassaad5.2, fassaad5.2:fassaad5.2:1705610
In: 2 korrus
Type - Material: Steel/Aluminium
Pset_WallCommon - LoadBearing: no; ExtendToStructure: no; IsExternal: no; Reference: fassaad5.2

# IfcWall: fassaad5.3:fassaad5.3, fassaad5.3:fassaad5.3:1706472
In: 1 korrus
Type - Material: Steel/Aluminium
Pset_WallCommon - LoadBearing: no; ExtendToStructure: no; IsExternal: no; Reference: fassaad5.3

# IfcWall: fassaad5:fassaad5, fassaad5:fassaad5:1699047
In: 4 korrus
Type - Material: Steel/Aluminium
Pset_WallCommon - LoadBearing: no; ExtendToStructure: no; IsExternal: no; Reference: fassaad5

# IfcWall: fassaad6.1:fassaad6.1, fassaad6.1:fassaad6.1:1700143
In: 3 korrus
Type - Material: Steel/Aluminium
Pset_WallCommon - LoadBearing: no; ExtendToStructure: no; IsExternal: no; Reference: fassaad6.1

# IfcWall: fassaad6.2:fassaad6.2, fassaad6.2:fassaad6.2:1700144
In: 2 korrus
Type - Material: Steel/Aluminium
Pset_WallCommon - LoadBearing: no; ExtendToStructure: no; IsExternal: no; Reference: fassaad6.2

# IfcWall: fassaad6.3:fassaad6.3, fassaad6.3:fassaad6.3:1702860
In: 1 korrus
Type - Material: Steel/Aluminium
Pset_WallCommon - LoadBearing: no; ExtendToStructure: no; IsExternal: no; Reference: fassaad6.3

# IfcWall: fassaad6:fassaad6, fassaad6:fassaad6:1700142
In: 4 korrus
Type - Material: Steel/Aluminium
Pset_WallCommon - LoadBearing: no; ExtendToStructure: no; IsExternal: no; Reference: fassaad6

# IfcWall: fassaad7.1:fassaad7.1, fassaad7.1:fassaad7.1:1708468
In: 3 korrus
Type - Material: Steel/Aluminium
Pset_WallCommon - LoadBearing: no; ExtendToStructure: no; IsExternal: no; Reference: fassaad7.1

# IfcWall: fassaad7.2:fassaad7.2, fassaad7.2:fassaad7.2:1708469
In: 2 korrus
Type - Material: Steel/Aluminium
Pset_WallCommon - LoadBearing: no; ExtendToStructure: no; IsExternal: no; Reference: fassaad7.2

# IfcWall: fassaad7.3:fassaad7.3, fassaad7.3:fassaad7.3:1708470
In: 1 korrus
Type - Material: Steel/Aluminium
Pset_WallCommon - LoadBearing: no; ExtendToStructure: no; IsExternal: no; Reference: fassaad7.3

# IfcWall: fassaad7:fassaad7, fassaad7:fassaad7:1708467
In: 4 korrus
Type - Material: Steel/Aluminium
Pset_WallCommon - LoadBearing: no; ExtendToStructure: no; IsExternal: no; Reference: fassaad7

# IfcWall: fassaad8.1:fassaad8.1, fassaad8.1:fassaad8.1:1684128
In: 3 korrus
Type - Material: Steel/Aluminium
Pset_WallCommon - LoadBearing: no; ExtendToStructure: no; IsExternal: no; Reference: fassaad8.1

# IfcWall: fassaad8.2:fassaad8.2, fassaad8.2:fassaad8.2:1686546
In: 2 korrus
Type - Material: Steel/Aluminium
Pset_WallCommon - LoadBearing: no; ExtendToStructure: no; IsExternal: no; Reference: fassaad8.2

# IfcWall: fassaad8.3:fassaad8.3, fassaad8.3:fassaad8.3:1688202
In: 1 korrus
Type - Material: Steel/Aluminium
Pset_WallCommon - LoadBearing: no; ExtendToStructure: no; IsExternal: no; Reference: fassaad8.3

# IfcWall: fassaad8:fassaad8, fassaad8:fassaad8:1683255
In: 4 korrus
Type - Material: Steel/Aluminium
Pset_WallCommon - LoadBearing: no; ExtendToStructure: no; IsExternal: no; Reference: fassaad8

# IfcWall: fassaad9.1:fassaad9.1, fassaad9.1:fassaad9.1:1693245
In: 3 korrus
Type - Material: Steel/Aluminium
Pset_WallCommon - LoadBearing: no; ExtendToStructure: no; IsExternal: no; Reference: fassaad9.1

# IfcWall: fassaad9.2:fassaad9.2, fassaad9.2:fassaad9.2:1694844
In: 2 korrus
Type - Material: Steel/Aluminium
Pset_WallCommon - LoadBearing: no; ExtendToStructure: no; IsExternal: no; Reference: fassaad9.2

# IfcWall: fassaad9:fassaad9, fassaad9:fassaad9:1691538
In: 4 korrus
Type - Material: Steel/Aluminium
Pset_WallCommon - LoadBearing: no; ExtendToStructure: no; IsExternal: no; Reference: fassaad9

# IfcWall: trepi sein1:trepi sein1 (2)
In: 1 korrus
Type - Material: Steel/Aluminium
Pset_WallCommon - LoadBearing: no; IsExternal: no; ExtendToStructure: yes; Reference: trepi sein1
Name (trepi sein1:trepi sein1:...)
411547
411820

# IfcWallStandardCase: Basic Wall:GENEERILINE - KONSTRUKTRIOON 160, SEIN - 010
In: 3 korrus
Type - PredefinedType: STANDARD; Material: GENEERILINE - KONSTRUKTRIOON 160 mm
Pset_WallCommon - LoadBearing: no; ExtendToStructure: no; IsExternal: yes; Reference: GENEERILINE - KONSTRUKTRIOON 160
AR_IFC_SEINAD - 01.Nimetus: Sisesein; 02.Materjal: Silikaattellis; 03.Kategooria / tüüp: SS-1; 04.Tulepüsivus: -; 05.Asukoha info: Interior; 06.Kandevelementide eristatud: nonbearing; 07.Helipidavus: 48dB; 06.Soojusläbivus: -; Phase Created: Existing

# IfcWallStandardCase: Basic Wall:GENEERILINE - KONSTRUKTRIOON 500, SEIN - 003
In: Vundament
Type - PredefinedType: STANDARD; Material: GENEERILINE - KONSTRUKTRIOON 500 mm
Pset_WallCommon - LoadBearing: no; ExtendToStructure: no; IsExternal: yes; Reference: GENEERILINE - KONSTRUKTRIOON 500
AR_IFC_SEINAD - Phase Created: Existing

# IfcWallStandardCase: Basic Wall:Juurdeehituse välissein_soojustuseta (3)
Type - PredefinedType: STANDARD; Material: __Kergblokk 190 mm
Pset_WallCommon - LoadBearing: no; ExtendToStructure: no; IsExternal: yes; Reference: Juurdeehituse välissein_soojustuseta; ThermalTransmittance: 4 kg/K/s3
AR_IFC_SEINAD - Phase Created: New Construction
Name (Basic Wall:Juurdeehituse välissein_soojustuseta:...) | In
1556599 | Vundament
1558816 | uus 2 korrus
1561929 | uus 3 korrus

# IfcWallStandardCase: Basic Wall:Kipssein šahtile (6)
Type - PredefinedType: STANDARD; Material: __Kips GN13_tava 12.5 mm, __Kips GN13_tava 12.5 mm, __Soojustus EPS 66 mm
Pset_WallCommon - LoadBearing: no; ExtendToStructure: no; IsExternal: no; Reference: Kipssein šahtile
AR_IFC_SEINAD - 01.Nimetus: Sisesein; 02.Materjal: Kips; 03.Kategooria / tüüp: SS-5; 04.Tulepüsivus: -; 05.Asukoha info: Interior; 06.Kandevelementide eristatud: nonbearing; 07.Helipidavus: 48dB; 06.Soojusläbivus: -; Phase Created: New Construction
Name (Basic Wall:Kipssein šahtile:...) | In
1767316 | 2 korrus
1767592 | 2 korrus
1767815 | 3 korrus
1767816 | 3 korrus
1767821 | 4 korrus
1767822 | 4 korrus

# IfcWallStandardCase: Basic Wall:Klaassein (2)
Type - PredefinedType: STANDARD; Material: _Klaas - must, peegelkile 152 mm
Pset_WallCommon - LoadBearing: no; ExtendToStructure: no; IsExternal: yes; Reference: Klaassein
AR_IFC_SEINAD - 01.Nimetus: Välissein; 02.Materjal: Klaas; 03.Kategooria / tüüp: VS-2.1; 04.Tulepüsivus: -; 05.Asukoha info: Exterior; 06.Kandevelementide eristatud: nonbearing; 07.Helipidavus: 56dB; 06.Soojusläbivus: 0,18W/m2K; Phase Created: New Construction
Name (Basic Wall:Klaassein:...) | In
310998 | Vundament
376781 | uus 1 korrus

# IfcWallStandardCase: Basic Wall:Liftišahti sein, SEIN - 006
In: Katusekorrus
Type - PredefinedType: STANDARD; Material: Tellis 309 mm
Pset_WallCommon - LoadBearing: no; ExtendToStructure: no; IsExternal: yes; Reference: Liftišahti sein
AR_IFC_SEINAD - Phase Created: Existing

# IfcWallStandardCase: Basic Wall:Parapett (4)
In: Katusekorrus
Type - PredefinedType: STANDARD; Material: __Tuuletõkkeplaat 9 mm, __Soojustus EPS 200 mm, Brick, Common 450 mm, __Kips GN13_tava 20 mm
Pset_WallCommon - ExtendToStructure: no; IsExternal: yes; ThermalTransmittance: 1.2 kg/K/s3; Reference: Parapett
AR_IFC_SEINAD - Phase Created: New Construction
Name | LoadBearing
2 x SEIN - 003 | no
2 x SEIN - 002 | yes

# IfcWallStandardCase: Basic Wall:SS-01_ol.olev tellissein100 (7)
Type - PredefinedType: STANDARD; Material: Tellis 90 mm, __Hall krohv 10 mm
Pset_WallCommon - LoadBearing: no; ExtendToStructure: no; IsExternal: no; Reference: SS-01_ol.olev tellissein100
AR_IFC_SEINAD - Phase Created: Existing
Name | In | 01.Nimetus | 02.Materjal | 03.Kategooria / tüüp | 04.Tulepüsivus | 05.Asukoha info | 06.Kandevelementide eristatud | 07.Helipidavus | 06.Soojusläbivus
SEIN - 008 | Katusekorrus
SEIN - 008 | Katusekorrus | Ol.olev liftišahti sein | Silikaattellis | - | EI-60 | Exterior | bearing | - | -
SEIN - 008 | 1 korrus | Ol.olev liftišahti sein | Silikaattellis | - | EI-60 | Exterior | bearing | - | -
SEIN - 003 | 1 korrus | Sisesein | Silikaattellis | SS-1 | - | Interior | bearing | 48dB | -
SEIN - 008 | 2 korrus | Ol.olev liftišahti sein | Silikaattellis | - | EI-60 | Exterior | bearing | - | -
SEIN - 008 | 3 korrus | Ol.olev liftišahti sein | Silikaattellis | - | EI-60 | Exterior | bearing | - | -
SEIN - 008 | 4 korrus | Ol.olev liftišahti sein | Silikaattellis | - | EI-60 | Exterior | bearing | - | -

# IfcWallStandardCase: Basic Wall:SS-01_ol.olev tellissein170, SEIN - 001
In: 2 korrus
Type - PredefinedType: STANDARD; Material: Tellis 160 mm, __Hall krohv 10 mm
Pset_WallCommon - LoadBearing: no; ExtendToStructure: no; IsExternal: no; Reference: SS-01_ol.olev tellissein170
AR_IFC_SEINAD - 01.Nimetus: Sisesein; 02.Materjal: Silikaattellis; 03.Kategooria / tüüp: SS-1; 04.Tulepüsivus: -; 05.Asukoha info: Interior; 06.Kandevelementide eristatud: bearing; 07.Helipidavus: 48dB; 06.Soojusläbivus: -; Phase Created: Existing

# IfcWallStandardCase: Basic Wall:SS-01_ol.olev tellissein190, SEIN - 003
In: 1 korrus
Type - PredefinedType: STANDARD; Material: __Hall krohv 10 mm, Tellis 170 mm, __Hall krohv 10 mm
Pset_WallCommon - LoadBearing: no; ExtendToStructure: no; IsExternal: no; Reference: SS-01_ol.olev tellissein190
AR_IFC_SEINAD - 01.Nimetus: Sisesein; 02.Materjal: Silikaattellis; 03.Kategooria / tüüp: SS-1; 04.Tulepüsivus: -; 05.Asukoha info: Interior; 06.Kandevelementide eristatud: bearing; 07.Helipidavus: 48dB; 06.Soojusläbivus: -; Phase Created: Existing

# IfcWallStandardCase: Basic Wall:SS-01_ol.olev tellissein200 (2)
Type - PredefinedType: STANDARD; Material: __Hall krohv 10 mm, Tellis 180 mm, __Hall krohv 10 mm
Pset_WallCommon - LoadBearing: no; ExtendToStructure: no; IsExternal: no; Reference: SS-01_ol.olev tellissein200
AR_IFC_SEINAD - 01.Nimetus: Sisesein; 02.Materjal: Silikaattellis; 03.Kategooria / tüüp: SS-1; 04.Tulepüsivus: -; 05.Asukoha info: Interior; 06.Kandevelementide eristatud: bearing; 07.Helipidavus: 48dB; 06.Soojusläbivus: -; Phase Created: Existing
Name | In
SEIN - 006 | 4 korrus
SEIN - 003 | 1 korrus

# IfcWallStandardCase: Basic Wall:SS-01_ol.olev tellissein300 (3)
In: 1 korrus
Type - PredefinedType: STANDARD; Material: __Hall krohv 10 mm, Tellis 280 mm, __Hall krohv 10 mm
Pset_WallCommon - ExtendToStructure: no; IsExternal: no; Reference: SS-01_ol.olev tellissein300
AR_IFC_SEINAD - 01.Nimetus: Sisesein; 02.Materjal: Silikaattellis; 03.Kategooria / tüüp: SS-1; 04.Tulepüsivus: -; 05.Asukoha info: Interior; 06.Kandevelementide eristatud: bearing; 07.Helipidavus: 48dB; 06.Soojusläbivus: -; Phase Created: Existing
Name | LoadBearing
SEIN - 001 | yes
SEIN - 002 | no
SEIN - 003 | no

# IfcWallStandardCase: Basic Wall:SS-01_ol.olev tellissein370, SEIN - 002
In: 1 korrus
Type - PredefinedType: STANDARD; Material: __Hall krohv 10 mm, Tellis 350 mm, __Hall krohv 10 mm
Pset_WallCommon - LoadBearing: no; ExtendToStructure: no; IsExternal: no; Reference: SS-01_ol.olev tellissein370
AR_IFC_SEINAD - 01.Nimetus: Sisesein; 02.Materjal: Silikaattellis; 03.Kategooria / tüüp: SS-1; 04.Tulepüsivus: -; 05.Asukoha info: Interior; 06.Kandevelementide eristatud: bearing; 07.Helipidavus: 48dB; 06.Soojusläbivus: -; Phase Created: Existing

# IfcWallStandardCase: Basic Wall:SS-01_ol.olev tellissein400 (15)
Type - PredefinedType: STANDARD; Material: __Hall krohv 10 mm, Tellis 380 mm, __Hall krohv 10 mm
Pset_WallCommon - ExtendToStructure: no; IsExternal: no; Reference: SS-01_ol.olev tellissein400
AR_IFC_SEINAD - 02.Materjal: Silikaattellis; 04.Tulepüsivus: EI-60; 06.Kandevelementide eristatud: bearing; 06.Soojusläbivus: -
Name | In | LoadBearing | 01.Nimetus | 03.Kategooria / tüüp | 05.Asukoha info | 07.Helipidavus | Phase Created
SEIN - 001 | 1 korrus | no | Sisesein | SS-1 | Interior | 48dB | Existing
SEIN - 002 | 2 korrus | yes | Sisesein | SS-1 | Interior | 48dB | Existing
SEIN - 001 | 2 korrus | yes | Sisesein | SS-1 | Interior | 48dB | Existing
SEIN - 003 | 3 korrus | yes | Sisesein | SS-1 | Interior | 48dB | Existing
SEIN - 002 | 3 korrus | yes | Sisesein | SS-1 | Interior | 48dB | Existing
SEIN - 001 | 3 korrus | yes | Sisesein | SS-1 | Interior | 48dB | Existing
SEIN - 001 | 4 korrus | yes | Sisesein | SS-1 | Interior | 48dB | Existing
SEIN - 003 | Vundament | no | Sisesein | SS-1 | Interior | 48dB | Existing
SEIN - 005 | Vundament | no | Ol.olev liftišahti sein | - | Exterior | - | Existing
SEIN - 006 | Vundament | no | Sisesein | SS-1 | Interior | 48dB | Existing
SEIN - 007 | Vundament | no | Ol.olev liftišahti sein | - | Exterior | - | Existing
SEIN - 003 | 1 korrus | yes | Sisesein | SS-1 | Interior | 48dB | Existing
SEIN - 003 | 2 korrus | yes | Sisesein | SS-1 | Interior | 48dB | Existing
SEIN - 003 | 4 korrus | yes | Sisesein | SS-1 | Interior | 48dB | Existing
SEIN - 006 | Vundament | no | Ol.olev liftišahti sein | - | Exterior | - | New Construction

# IfcWallStandardCase: Basic Wall:SS-01_ol.olev tellissein430, SEIN - 002
In: 4 korrus
Type - PredefinedType: STANDARD; Material: __Hall krohv 10 mm, Tellis 410 mm, __Hall krohv 10 mm
Pset_WallCommon - ExtendToStructure: no; IsExternal: no; LoadBearing: yes; Reference: SS-01_ol.olev tellissein430
AR_IFC_SEINAD - 01.Nimetus: Sisesein; 02.Materjal: Silikaattellis; 03.Kategooria / tüüp: SS-1; 04.Tulepüsivus: -; 05.Asukoha info: Interior; 06.Kandevelementide eristatud: bearing; 07.Helipidavus: 48dB; 06.Soojusläbivus: -; Phase Created: Existing

# IfcWallStandardCase: Basic Wall:SS-01_ol.olev tellissein450 (4)
Type - PredefinedType: STANDARD; Material: __Hall krohv 10 mm, Tellis 430 mm, __Hall krohv 10 mm
Pset_WallCommon - ExtendToStructure: no; IsExternal: no; LoadBearing: yes; Reference: SS-01_ol.olev tellissein450
AR_IFC_SEINAD - 01.Nimetus: Sisesein; 02.Materjal: Silikaattellis; 03.Kategooria / tüüp: SS-1; 04.Tulepüsivus: -; 05.Asukoha info: Interior; 06.Kandevelementide eristatud: bearing; 07.Helipidavus: 48dB; 06.Soojusläbivus: -; Phase Created: Existing
Name | In
SEIN - 002 | 1 korrus
SEIN - 002 | 2 korrus
SEIN - 002 | 3 korrus
SEIN - 002 | 4 korrus

# IfcWallStandardCase: Basic Wall:SS-01_ol.olev tellissein70 (2)
In: 2 korrus
Type - PredefinedType: STANDARD; Material: Tellis 60 mm, __Hall krohv 10 mm
Pset_WallCommon - LoadBearing: no; ExtendToStructure: no; IsExternal: no; Reference: SS-01_ol.olev tellissein70
AR_IFC_SEINAD - 01.Nimetus: Sisesein; 02.Materjal: Silikaattellis; 03.Kategooria / tüüp: SS-1; 04.Tulepüsivus: -; 05.Asukoha info: Interior; 06.Kandevelementide eristatud: bearing; 07.Helipidavus: 48dB; 06.Soojusläbivus: -; Phase Created: Existing
Name
SEIN - 002
SEIN - 003

# IfcWallStandardCase: Basic Wall:SS-1 (7)
Type - PredefinedType: STANDARD; Material: __Kips GN13_tava 20 mm, Masonry - Brick 510 mm, __Kips GN13_tava 20 mm
Pset_WallCommon - ExtendToStructure: no; IsExternal: no; LoadBearing: yes; Reference: SS-1
AR_IFC_SEINAD - 01.Nimetus: Sisesein; 02.Materjal: Silikaattellis; 03.Kategooria / tüüp: SS-1; 04.Tulepüsivus: REI-240; 05.Asukoha info: Interior; 06.Kandevelementide eristatud: bearing; 07.Helipidavus: 52dB; 06.Soojusläbivus: -; Phase Created: Existing
Name | In
3 x SEIN - 002 | 1 korrus
SEIN - 002 | 2 korrus
SEIN - 016 | Vundament
SEIN - 002 | 3 korrus
SEIN - 002 | 4 korrus

# IfcWallStandardCase: Basic Wall:SS-1_420mm (7)
Type - PredefinedType: STANDARD; Material: __Kips GN13_tava 20 mm, Brick, Common 380 mm, __Kips GN13_tava 20 mm
Pset_WallCommon - IsExternal: no; Reference: SS-1_420mm; ThermalTransmittance: 1.42105 kg/K/s3
AR_IFC_SEINAD - 01.Nimetus: Sisesein; 02.Materjal: Silikaattellis; 03.Kategooria / tüüp: SS-1; 04.Tulepüsivus: EI-60; 05.Asukoha info: Interior; 06.Kandevelementide eristatud: bearing; 07.Helipidavus: 48dB; 06.Soojusläbivus: -; Phase Created: Existing
Name | In | LoadBearing | ExtendToStructure
SEIN - 005 | 4 korrus | yes | yes
SEIN - 002 | 4 korrus | yes | no
SEIN - 002 | 3 korrus | no | no
SEIN - 005 | 1 korrus | yes | no
SEIN - 002 | 2 korrus | yes | no
SEIN - 005 | 2 korrus | yes | no
SEIN - 005 | 3 korrus | yes | no

# IfcWallStandardCase: Basic Wall:SS-2.1_Columbia kivi EI-60 sein (7)
Type - PredefinedType: STANDARD; Material: __Hall krohv 10 mm, __Kergblokk 190 mm, __Hall krohv 10 mm
Pset_WallCommon - LoadBearing: no; ExtendToStructure: no; IsExternal: no; Reference: SS-2.1_Columbia kivi EI-60 sein; ThermalTransmittance: 4 kg/K/s3
AR_IFC_SEINAD - 01.Nimetus: Sisesein; 02.Materjal: Columbia kivi; 03.Kategooria / tüüp: SS-2.1; 04.Tulepüsivus: EI-60; 05.Asukoha info: Interior; 06.Kandevelementide eristatud: bearing; 07.Helipidavus: 48dB; 06.Soojusläbivus: -; Phase Created: New Construction
Name (Basic Wall:SS-2.1_Columbia kivi EI-60 sein:...) | In
487801 | uus 1 korrus
487906 | uus 2 korrus
926213 | uus 2 korrus
926588 | uus 2 korrus
926820 | uus 1 korrus
926821 | uus 1 korrus
933223 | uus 3 korrus

# IfcWallStandardCase: Basic Wall:SS-3*_Kipssein EI-60 (6)
Type - PredefinedType: STANDARD; Material: __Kips GN13_tava 12.5 mm, __Kips GN13_tava 12.5 mm, __Soojustus EPS 66 mm, __Kips GN13_tava 12.5 mm, __Kips GN13_tava 12.5 mm
Pset_WallCommon - LoadBearing: no; ExtendToStructure: no; IsExternal: no; Reference: SS-3*_Kipssein EI-60
AR_IFC_SEINAD - 01.Nimetus: Sisesein; 05.Asukoha info: Interior; 07.Helipidavus: 48dB; 06.Soojusläbivus: -
Name | In | 02.Materjal | 03.Kategooria / tüüp | 04.Tulepüsivus | 06.Kandevelementide eristatud | Phase Created
SEIN - 005 | 2 korrus | Silikaattellis | SS-1 | EI-60 | bearing | Existing
Basic Wall:SS-3*_Kipssein EI-60:479979 | 1 korrus | Kips | SS-3* | EI-60 | nonbearing | New Construction
Basic Wall:SS-3*_Kipssein EI-60:516700 | 2 korrus | Kips | SS-3 | - | nonbearing | New Construction
Basic Wall:SS-3*_Kipssein EI-60:516905 | 2 korrus | Kips | SS-3 | - | nonbearing | New Construction
Basic Wall:SS-3*_Kipssein EI-60:570146 | 3 korrus | Kips | SS-3 | - | nonbearing | New Construction
Basic Wall:SS-3*_Kipssein EI-60:570187 | 3 korrus | Kips | SS-3 | - | nonbearing | New Construction

# IfcWallStandardCase: Basic Wall:SS-3_Kipssein tava ruumide vahel (127)
Type - PredefinedType: STANDARD; Material: __Kips GN13_tava 12.5 mm, __Kips GN13_tava 12.5 mm, __Soojustus EPS 66 mm, __Kips GN13_tava 12.5 mm, __Kips GN13_tava 12.5 mm
Pset_WallCommon - LoadBearing: no; IsExternal: no; Reference: SS-3_Kipssein tava ruumide vahel
AR_IFC_SEINAD - 01.Nimetus: Sisesein; 02.Materjal: Kips; 03.Kategooria / tüüp: SS-3; 04.Tulepüsivus: -; 05.Asukoha info: Interior; 06.Kandevelementide eristatud: nonbearing; 07.Helipidavus: 48dB; 06.Soojusläbivus: -; Phase Created: New Construction
Name | In | ExtendToStructure
SEIN - 005 | 2 korrus | no
Basic Wall:SS-3_Kipssein tava ruumide vahel:320641 | 1 korrus | no
Basic Wall:SS-3_Kipssein tava ruumide vahel:322742 | 1 korrus | no
Basic Wall:SS-3_Kipssein tava ruumide vahel:324248 | 1 korrus | no
Basic Wall:SS-3_Kipssein tava ruumide vahel:324256 | 1 korrus | no
Basic Wall:SS-3_Kipssein tava ruumide vahel:324262 | 1 korrus | no
Basic Wall:SS-3_Kipssein tava ruumide vahel:327653 | 1 korrus | no
Basic Wall:SS-3_Kipssein tava ruumide vahel:327680 | 1 korrus | no
Basic Wall:SS-3_Kipssein tava ruumide vahel:327812 | 1 korrus | no
Basic Wall:SS-3_Kipssein tava ruumide vahel:327813 | 1 korrus | no
Basic Wall:SS-3_Kipssein tava ruumide vahel:328809 | 1 korrus | no
Basic Wall:SS-3_Kipssein tava ruumide vahel:329290 | 1 korrus | no
Basic Wall:SS-3_Kipssein tava ruumide vahel:329291 | 1 korrus | no
Basic Wall:SS-3_Kipssein tava ruumide vahel:478667 | 1 korrus | no
Basic Wall:SS-3_Kipssein tava ruumide vahel:488148 | 1 korrus | no
Basic Wall:SS-3_Kipssein tava ruumide vahel:488469 | 1 korrus | no
Basic Wall:SS-3_Kipssein tava ruumide vahel:488876 | 1 korrus | no
Basic Wall:SS-3_Kipssein tava ruumide vahel:488961 | 1 korrus | no
Basic Wall:SS-3_Kipssein tava ruumide vahel:488998 | 1 korrus | no
Basic Wall:SS-3_Kipssein tava ruumide vahel:495644 | 1 korrus | no
Basic Wall:SS-3_Kipssein tava ruumide vahel:495928 | 1 korrus | no
Basic Wall:SS-3_Kipssein tava ruumide vahel:497312 | uus 1 korrus | no
Basic Wall:SS-3_Kipssein tava ruumide vahel:497384 | uus 1 korrus | no
Basic Wall:SS-3_Kipssein tava ruumide vahel:497476 | uus 1 korrus | no
Basic Wall:SS-3_Kipssein tava ruumide vahel:497568 | uus 1 korrus | no
Basic Wall:SS-3_Kipssein tava ruumide vahel:497664 | uus 1 korrus | no
Basic Wall:SS-3_Kipssein tava ruumide vahel:497784 | uus 1 korrus | no
Basic Wall:SS-3_Kipssein tava ruumide vahel:498742 | uus 1 korrus | no
Basic Wall:SS-3_Kipssein tava ruumide vahel:516153 | 2 korrus | no
Basic Wall:SS-3_Kipssein tava ruumide vahel:516998 | 2 korrus | no
Basic Wall:SS-3_Kipssein tava ruumide vahel:516999 | 2 korrus | no
Basic Wall:SS-3_Kipssein tava ruumide vahel:555960 | 2 korrus | no
Basic Wall:SS-3_Kipssein tava ruumide vahel:556211 | 2 korrus | no
Basic Wall:SS-3_Kipssein tava ruumide vahel:556217 | 2 korrus | no
Basic Wall:SS-3_Kipssein tava ruumide vahel:556489 | 2 korrus | no
SEIN - 009 | 3 korrus | no
Basic Wall:SS-3_Kipssein tava ruumide vahel:562871 | 3 korrus | no
Basic Wall:SS-3_Kipssein tava ruumide vahel:562872 | 3 korrus | no
Basic Wall:SS-3_Kipssein tava ruumide vahel:562873 | 3 korrus | no
Basic Wall:SS-3_Kipssein tava ruumide vahel:562874 | 3 korrus | no
Basic Wall:SS-3_Kipssein tava ruumide vahel:562875 | 3 korrus | no
Basic Wall:SS-3_Kipssein tava ruumide vahel:563003 | 4 korrus | yes
Basic Wall:SS-3_Kipssein tava ruumide vahel:563004 | 4 korrus | yes
Basic Wall:SS-3_Kipssein tava ruumide vahel:563005 | 4 korrus | yes
Basic Wall:SS-3_Kipssein tava ruumide vahel:563006 | 4 korrus | yes
Basic Wall:SS-3_Kipssein tava ruumide vahel:563007 | 4 korrus | yes
Basic Wall:SS-3_Kipssein tava ruumide vahel:563390 | 3 korrus | no
Basic Wall:SS-3_Kipssein tava ruumide vahel:563391 | 3 korrus | no
Basic Wall:SS-3_Kipssein tava ruumide vahel:563392 | 3 korrus | no
Basic Wall:SS-3_Kipssein tava ruumide vahel:563401 | 4 korrus | yes
Basic Wall:SS-3_Kipssein tava ruumide vahel:563402 | 4 korrus | yes
Basic Wall:SS-3_Kipssein tava ruumide vahel:567418 | 3 korrus | no
Basic Wall:SS-3_Kipssein tava ruumide vahel:567641 | 3 korrus | no
Basic Wall:SS-3_Kipssein tava ruumide vahel:567700 | 3 korrus | no
Basic Wall:SS-3_Kipssein tava ruumide vahel:569569 | 3 korrus | no
Basic Wall:SS-3_Kipssein tava ruumide vahel:569708 | 3 korrus | no
Basic Wall:SS-3_Kipssein tava ruumide vahel:570319 | 3 korrus | no
Basic Wall:SS-3_Kipssein tava ruumide vahel:570610 | 3 korrus | no
Basic Wall:SS-3_Kipssein tava ruumide vahel:570618 | 3 korrus | no
Basic Wall:SS-3_Kipssein tava ruumide vahel:570626 | 3 korrus | no
Basic Wall:SS-3_Kipssein tava ruumide vahel:570632 | 3 korrus | no
Basic Wall:SS-3_Kipssein tava ruumide vahel:570836 | 3 korrus | no
Basic Wall:SS-3_Kipssein tava ruumide vahel:570941 | 3 korrus | no
Basic Wall:SS-3_Kipssein tava ruumide vahel:575173 | 3 korrus | no
Basic Wall:SS-3_Kipssein tava ruumide vahel:575381 | 3 korrus | no
Basic Wall:SS-3_Kipssein tava ruumide vahel:575940 | 4 korrus | no
Basic Wall:SS-3_Kipssein tava ruumide vahel:578931 | 4 korrus | yes
Basic Wall:SS-3_Kipssein tava ruumide vahel:578945 | 4 korrus | yes
Basic Wall:SS-3_Kipssein tava ruumide vahel:578955 | 4 korrus | yes
Basic Wall:SS-3_Kipssein tava ruumide vahel:581801 | 4 korrus | yes
Basic Wall:SS-3_Kipssein tava ruumide vahel:581807 | 4 korrus | yes
Basic Wall:SS-3_Kipssein tava ruumide vahel:581813 | 4 korrus | yes
Basic Wall:SS-3_Kipssein tava ruumide vahel:581819 | 4 korrus | yes
Basic Wall:SS-3_Kipssein tava ruumide vahel:581825 | 4 korrus | yes
Basic Wall:SS-3_Kipssein tava ruumide vahel:895390 | uus 1 korrus | no
Basic Wall:SS-3_Kipssein tava ruumide vahel:900447 | uus 1 korrus | no
Basic Wall:SS-3_Kipssein tava ruumide vahel:926337 | uus 2 korrus | no
Basic Wall:SS-3_Kipssein tava ruumide vahel:926650 | uus 2 korrus | no
Basic Wall:SS-3_Kipssein tava ruumide vahel:928377 | uus 2 korrus | no
Basic Wall:SS-3_Kipssein tava ruumide vahel:929803 | uus 2 korrus | no
Basic Wall:SS-3_Kipssein tava ruumide vahel:931089 | uus 2 korrus | no
Basic Wall:SS-3_Kipssein tava ruumide vahel:931889 | uus 2 korrus | no
Basic Wall:SS-3_Kipssein tava ruumide vahel:932068 | uus 2 korrus | no
Basic Wall:SS-3_Kipssein tava ruumide vahel:933238 | uus 3 korrus | no
Basic Wall:SS-3_Kipssein tava ruumide vahel:934278 | uus 3 korrus | no
Basic Wall:SS-3_Kipssein tava ruumide vahel:934361 | uus 3 korrus | no
Basic Wall:SS-3_Kipssein tava ruumide vahel:934755 | uus 3 korrus | no
Basic Wall:SS-3_Kipssein tava ruumide vahel:1006214 | uus 3 korrus | no
Basic Wall:SS-3_Kipssein tava ruumide vahel:1076212 | 1 korrus | no
Basic Wall:SS-3_Kipssein tava ruumide vahel:1080846 | 4 korrus | no
Basic Wall:SS-3_Kipssein tava ruumide vahel:1080881 | 4 korrus | yes
Basic Wall:SS-3_Kipssein tava ruumide vahel:1080882 | 4 korrus | yes
Basic Wall:SS-3_Kipssein tava ruumide vahel:1080884 | 4 korrus | yes
Basic Wall:SS-3_Kipssein tava ruumide vahel:1080887 | 4 korrus | yes
Basic Wall:SS-3_Kipssein tava ruumide vahel:1080888 | 4 korrus | yes
Basic Wall:SS-3_Kipssein tava ruumide vahel:1080889 | 4 korrus | yes
Basic Wall:SS-3_Kipssein tava ruumide vahel:1081700 | 4 korrus | yes
Basic Wall:SS-3_Kipssein tava ruumide vahel:1116266 | 2 korrus | no
Basic Wall:SS-3_Kipssein tava ruumide vahel:1116267 | 2 korrus | no
Basic Wall:SS-3_Kipssein tava ruumide vahel:1116774 | 2 korrus | no
Basic Wall:SS-3_Kipssein tava ruumide vahel:1116923 | 2 korrus | no
Basic Wall:SS-3_Kipssein tava ruumide vahel:1116933 | 2 korrus | no
Basic Wall:SS-3_Kipssein tava ruumide vahel:1117117 | 2 korrus | no
Basic Wall:SS-3_Kipssein tava ruumide vahel:1117177 | 2 korrus | no
Basic Wall:SS-3_Kipssein tava ruumide vahel:1117300 | 2 korrus | no
Basic Wall:SS-3_Kipssein tava ruumide vahel:1117416 | 2 korrus | no
Basic Wall:SS-3_Kipssein tava ruumide vahel:1191529 | 2 korrus | no
Basic Wall:SS-3_Kipssein tava ruumide vahel:1192263 | 1 korrus | no
Basic Wall:SS-3_Kipssein tava ruumide vahel:1208655 | 3 korrus | no
Basic Wall:SS-3_Kipssein tava ruumide vahel:1208678 | 3 korrus | no
Basic Wall:SS-3_Kipssein tava ruumide vahel:1213716 | uus 1 korrus | no
Basic Wall:SS-3_Kipssein tava ruumide vahel:1254441 | 1 korrus | no
Basic Wall:SS-3_Kipssein tava ruumide vahel:1254553 | 1 korrus | no
Basic Wall:SS-3_Kipssein tava ruumide vahel:1260611 | uus 2 korrus | no
Basic Wall:SS-3_Kipssein tava ruumide vahel:1262944 | uus 3 korrus | yes
Basic Wall:SS-3_Kipssein tava ruumide vahel:1273203 | 4 korrus | yes
Basic Wall:SS-3_Kipssein tava ruumide vahel:1305448 | 4 korrus | yes
Basic Wall:SS-3_Kipssein tava ruumide vahel:1335158 | 3 korrus | no
Basic Wall:SS-3_Kipssein tava ruumide vahel:1336887 | 2 korrus | no
Basic Wall:SS-3_Kipssein tava ruumide vahel:1337789 | 3 korrus | no
Basic Wall:SS-3_Kipssein tava ruumide vahel:1337801 | 4 korrus | no
Basic Wall:SS-3_Kipssein tava ruumide vahel:1353895 | uus 1 korrus | no
Basic Wall:SS-3_Kipssein tava ruumide vahel:1354078 | uus 1 korrus | no
Basic Wall:SS-3_Kipssein tava ruumide vahel:1355978 | 1 korrus | no
Basic Wall:SS-3_Kipssein tava ruumide vahel:1355979 | 1 korrus | no
Basic Wall:SS-3_Kipssein tava ruumide vahel:1744423 | 4 korrus | no
Basic Wall:SS-3_Kipssein tava ruumide vahel:1745470 | 4 korrus | yes

# IfcWallStandardCase: Basic Wall:SS-4_Kipssein tava ja niiske ruumi vahel (17)
Type - PredefinedType: STANDARD; Material: __Kips GN13_tava 12.5 mm, __Kips GN13_tava 12.5 mm, __Soojustus EPS 66 mm, __Kips GKB_niiskuskindel 12.5 mm, __Kips GKB_niiskuskindel 12.5 mm, Keraamiline_plaat 10 mm
Pset_WallCommon - LoadBearing: no; IsExternal: no; Reference: SS-4_Kipssein tava ja niiske ruumi vahel
AR_IFC_SEINAD - 01.Nimetus: Sisesein; 02.Materjal: Kips; 03.Kategooria / tüüp: SS-4; 04.Tulepüsivus: -; 05.Asukoha info: Interior; 06.Kandevelementide eristatud: nonbearing; 07.Helipidavus: 48dB; 06.Soojusläbivus: -; Phase Created: New Construction
Name (Basic Wall:SS-4_Kipssein tava ja niiske ruumi vahel:...) | In | ExtendToStructure
327040 | 1 korrus | no
327681 | 1 korrus | no
328660 | 1 korrus | no
497887 | uus 1 korrus | no
497947 | uus 1 korrus | no
519033 | 2 korrus | no
562876 | 3 korrus | yes
563008 | 4 korrus | yes
927330 | uus 2 korrus | no
927543 | uus 2 korrus | no
927824 | uus 2 korrus | no
1005804 | uus 3 korrus | yes
1005805 | uus 3 korrus | yes
1005806 | uus 3 korrus | yes
1258210 | uus 1 korrus | no
1661994 | 1 korrus | no
1662051 | 1 korrus | no

# IfcWallStandardCase: Basic Wall:SS-5_Kipssein niiskete ruumide vahel (5)
Type - PredefinedType: STANDARD; Material: Keraamiline_plaat 10 mm, __Kips GKB_niiskuskindel 12.5 mm, __Kips GKB_niiskuskindel 12.5 mm, __Soojustus EPS 66 mm, __Kips GKB_niiskuskindel 12.5 mm, __Kips GKB_niiskuskindel 12.5 mm, Keraamiline_plaat 10 mm
Pset_WallCommon - LoadBearing: no; IsExternal: no; Reference: SS-5_Kipssein niiskete ruumide vahel
AR_IFC_SEINAD - 01.Nimetus: Sisesein; 02.Materjal: Kips; 03.Kategooria / tüüp: SS-5; 04.Tulepüsivus: -; 05.Asukoha info: Interior; 06.Kandevelementide eristatud: nonbearing; 07.Helipidavus: 48dB; 06.Soojusläbivus: -; Phase Created: New Construction
Name (Basic Wall:SS-5_Kipssein niiskete ruumide vahel:...) | In | ExtendToStructure
325892 | 1 korrus | no
327041 | 1 korrus | no
519160 | 2 korrus | no
562877 | 3 korrus | yes
563009 | 4 korrus | yes

# IfcWallStandardCase: Basic Wall:SS-6_Šahti sein EI-60 (39)
Type - PredefinedType: STANDARD; Material: __Helehall 10 mm, __Kergblokk 90 mm
Pset_WallCommon - LoadBearing: no; IsExternal: no; Reference: SS-6_Šahti sein EI-60; ThermalTransmittance: 8.44444 kg/K/s3
AR_IFC_SEINAD - 01.Nimetus: Sisesein; 02.Materjal: Columbia kivi; 03.Kategooria / tüüp: SS-6; 04.Tulepüsivus: EI-60; 05.Asukoha info: Interior; 06.Kandevelementide eristatud: nonbearing; 07.Helipidavus: 48dB; 06.Soojusläbivus: -; Phase Created: New Construction
Name (Basic Wall:SS-6_Šahti sein EI-60:...) | In | ExtendToStructure
513509 | 2 korrus | yes
513578 | 2 korrus | yes
513768 | 2 korrus | yes
513851 | 2 korrus | yes
513893 | 2 korrus | yes
514080 | 3 korrus | yes
514081 | 3 korrus | yes
514082 | 3 korrus | yes
514083 | 3 korrus | no
514084 | 3 korrus | yes
514138 | 4 korrus | yes
514139 | 4 korrus | yes
514140 | 4 korrus | yes
514141 | 4 korrus | yes
514142 | 4 korrus | yes
1004004 | uus 2 korrus | no
1004105 | uus 2 korrus | no
1005832 | uus 3 korrus | yes
1005833 | uus 3 korrus | yes
1306080 | uus 1 korrus | no
1306081 | uus 1 korrus | no
1332532 | uus 1 korrus | no
1332593 | uus 1 korrus | no
1332644 | uus 1 korrus | no
1338399 | 1 korrus | no
1338768 | 1 korrus | no
1338889 | 1 korrus | no
1340289 | 2 korrus | no
1340290 | 2 korrus | no
1341725 | uus 2 korrus | no
1341726 | uus 2 korrus | no
1341733 | uus 3 korrus | no
1341734 | uus 3 korrus | no
1341992 | uus 2 korrus | no
1342286 | uus 3 korrus | no
1342623 | 3 korrus | no
1342624 | 3 korrus | no
1342647 | 4 korrus | yes
1342648 | 4 korrus | yes

# IfcWallStandardCase: Basic Wall:SS-7_Bauroc sein niiskete ruumide vahel (2)
In: 1 korrus
Type - PredefinedType: STANDARD; Material: Keraamiline_plaat 10 mm, Bauroc 150 mm, Keraamiline_plaat 10 mm
Pset_WallCommon - LoadBearing: no; ExtendToStructure: no; IsExternal: no; Reference: SS-7_Bauroc sein niiskete ruumide vahel
AR_IFC_SEINAD - 01.Nimetus: Sisesein; 02.Materjal: Kergplokk; 03.Kategooria / tüüp: SS-7; 04.Tulepüsivus: -; 05.Asukoha info: Interior; 06.Kandevelementide eristatud: nonbearing; 07.Helipidavus: 41dB; 06.Soojusläbivus: -; Phase Created: New Construction
Name (Basic Wall:SS-7_Bauroc sein niiskete ruumide vahel:...)
328082
328201

# IfcWallStandardCase: Basic Wall:SS-8_Bauroc sein niiske ja tava ruumide vahel (5)
Type - PredefinedType: STANDARD; Material: Bauroc 150 mm, Keraamiline_plaat 10 mm
Pset_WallCommon - LoadBearing: no; ExtendToStructure: no; IsExternal: no; Reference: SS-8_Bauroc sein niiske ja tava ruumide vahel
AR_IFC_SEINAD - 01.Nimetus: Sisesein; 02.Materjal: Kergplokk; 03.Kategooria / tüüp: SS-8; 04.Tulepüsivus: -; 05.Asukoha info: Interior; 06.Kandevelementide eristatud: nonbearing; 07.Helipidavus: 41dB; 06.Soojusläbivus: -; Phase Created: New Construction
Name (Basic Wall:SS-8_Bauroc sein niiske ja tava ruumide vahel:...) | In
327401 | 1 korrus
327654 | 1 korrus
895083 | uus 1 korrus
895130 | uus 1 korrus
1254645 | 1 korrus

# IfcWallStandardCase: Basic Wall:SW kergpaneel 100mm (3)
In: 1 korrus
Type - PredefinedType: STANDARD; Material: External face timepruun h=1100mm 1 mm, Core Mineral wool Mineral Wool h=1100mm 98 mm, Internal face RAL 7035 h=1100mm 1 mm
Pset_WallCommon - LoadBearing: no; IsExternal: yes; Reference: SW kergpaneel 100mm
Pset_ManufacturerTypeInformation - Manufacturer: Ruukki
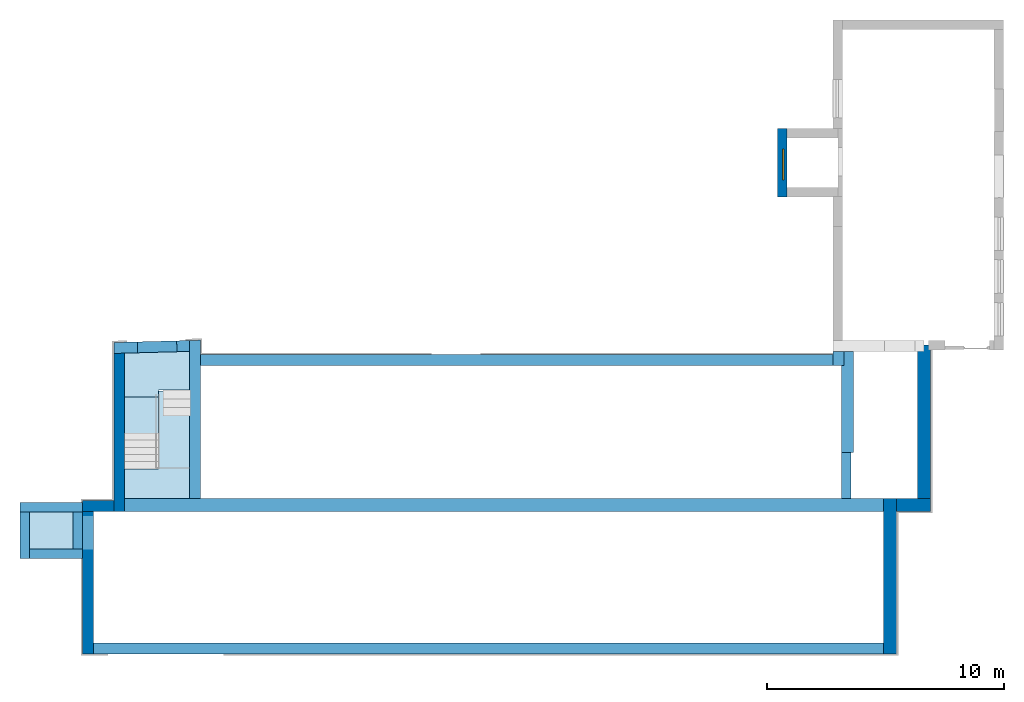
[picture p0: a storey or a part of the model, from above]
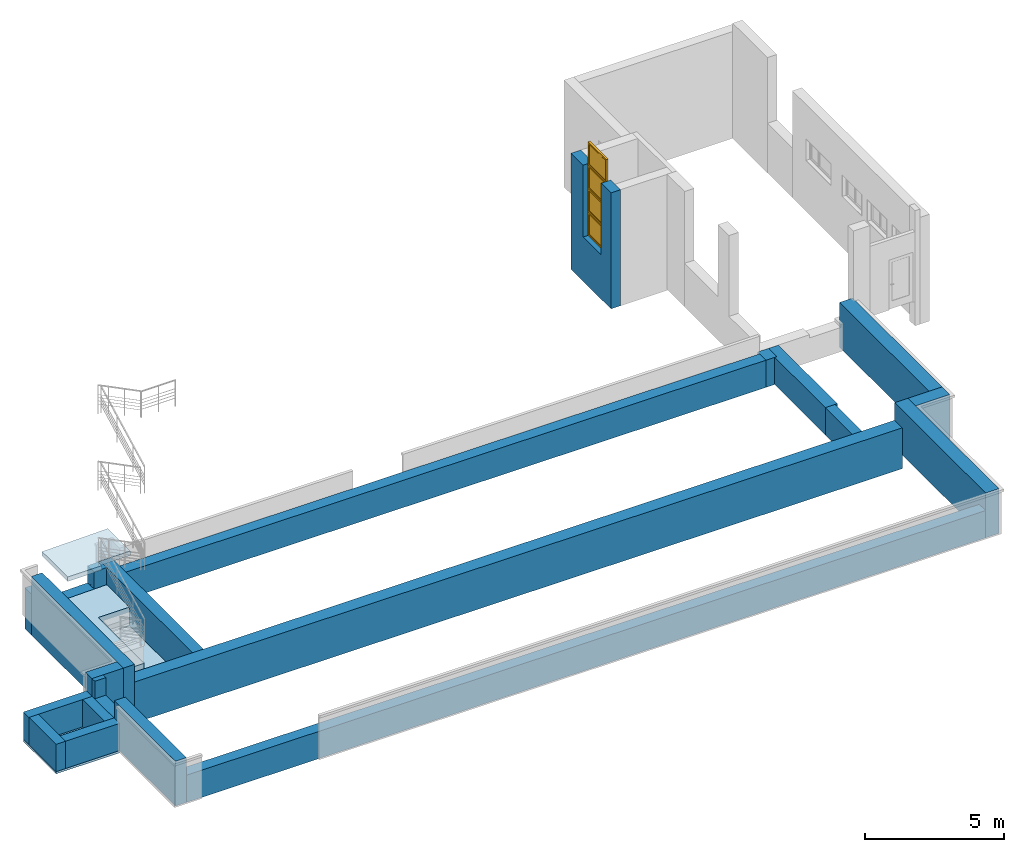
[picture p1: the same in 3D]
Properties of the parts of a building model (IFC2X3), part 5 of 5

# IfcWallStandardCase: Basic Wall:SW kergpaneel 100mm (3)
AR_IFC_SEINAD - 01.Nimetus: Sisesein; 02.Materjal: SW seinapaneel; 03.Kategooria / tüüp: SS-9; 04.Tulepüsivus: EI-60; 05.Asukoha info: Interior; 06.Kandevelementide eristatud: nonbearing; 07.Helipidavus: -; 06.Soojusläbivus: 0,45W/m2K; Phase Created: New Construction
Name (Basic Wall:SW kergpaneel 100mm:...) | ExtendToStructure
1256757 | no
1257009 | yes
1339507 | yes

# IfcWallStandardCase: Basic Wall:Uus tugimüür 200mm (3)
In: 1 korrus
Type - PredefinedType: STANDARD; Material: Betoon_uus konstr. 200 mm
Pset_WallCommon - ExtendToStructure: no; IsExternal: yes; LoadBearing: yes; Reference: Uus tugimüür 200mm
AR_IFC_SEINAD - 01.Nimetus: Tugimüür; 02.Materjal: Betoon; 03.Kategooria / tüüp: -; 04.Tulepüsivus: -; 05.Asukoha info: Exterior; 06.Kandevelementide eristatud: nonbearing; 07.Helipidavus: -; 06.Soojusläbivus: -; Phase Created: New Construction
Name (Basic Wall:Uus tugimüür 200mm:...)
832658
833536
1416707

# IfcWallStandardCase: Basic Wall:VS-01_Sokkel (3)
In: Vundament
Type - PredefinedType: STANDARD; Material: __Kips GN13_tava 20 mm, Masonry - Brick 510 mm, __Kips GN13_tava 20 mm
Pset_WallCommon - ExtendToStructure: no; IsExternal: yes; Reference: VS-01_Sokkel
AR_IFC_SEINAD - Phase Created: Existing
Name | LoadBearing
SEIN - 011 | yes
SEIN - 012 | no
SEIN - 013 | no

# IfcWallStandardCase: Basic Wall:VS-1 (30)
Type - PredefinedType: STANDARD; Material: Brick, Common 440 mm, __Kips GN13_tava 20 mm
Pset_WallCommon - ExtendToStructure: no; IsExternal: yes; Reference: VS-1; ThermalTransmittance: 1.22727 kg/K/s3
AR_IFC_SEINAD - 01.Nimetus: Välissein; 02.Materjal: Silikaattellis; 03.Kategooria / tüüp: VS-1; 04.Tulepüsivus: R-60; 05.Asukoha info: Exterior; 06.Kandevelementide eristatud: bearing; 07.Helipidavus: 56dB; 06.Soojusläbivus: 0,72W/m2K; Phase Created: Existing
Name | In | LoadBearing
2 x SEIN - 003 | 4 korrus | no
SEIN - 004 | 4 korrus | no
SEIN - 006 | Vundament | no
SEIN - 010 | Vundament | no
SEIN - 004 | 1 korrus | no
2 x SEIN - 003 | 2 korrus | no
SEIN - 004 | 2 korrus | no
2 x SEIN - 003 | 3 korrus | no
SEIN - 004 | 3 korrus | no
SEIN - 004 | Vundament | no
SEIN - 005 | Vundament | no
SEIN - 007 | Vundament | no
SEIN - 008 | Vundament | no
SEIN - 009 | Vundament | no
SEIN - 014 | Vundament | no
SEIN - 015 | Vundament | no
2 x SEIN - 003 | 1 korrus | no
SEIN - 005 | 1 korrus | no
SEIN - 001 | 1 korrus | yes
SEIN - 001 | 1 korrus | no
SEIN - 005 | 2 korrus | no
SEIN - 001 | 2 korrus | no
SEIN - 005 | 3 korrus | no
SEIN - 001 | 3 korrus | no
SEIN - 005 | 4 korrus | no
SEIN - 001 | 4 korrus | no

# IfcWallStandardCase: Basic Wall:VS-1_770 (4)
Type - PredefinedType: STANDARD; Material: Brick, Common 750 mm, __Kips GN13_tava 20 mm
Pset_WallCommon - LoadBearing: no; ExtendToStructure: no; IsExternal: yes; Reference: VS-1_770; ThermalTransmittance: 0.72 kg/K/s3
AR_IFC_SEINAD - 01.Nimetus: Välissein; 02.Materjal: Silikaattellis; 03.Kategooria / tüüp: VS-1; 04.Tulepüsivus: -; 05.Asukoha info: Exterior; 06.Kandevelementide eristatud: bearing; 07.Helipidavus: 56dB; 06.Soojusläbivus: 0,72W/m2K; Phase Created: Existing
Name | In
SEIN - 003 | 4 korrus
SEIN - 003 | 1 korrus
SEIN - 003 | 2 korrus
SEIN - 003 | 3 korrus

# IfcWallStandardCase: Basic Wall:VS-1krohviga_390mm (2)
In: 1 korrus
Type - PredefinedType: STANDARD; Material: Krohv 10 mm, Brick, Common 370 mm, Krohv 10 mm
Pset_WallCommon - LoadBearing: no; ExtendToStructure: no; IsExternal: yes; Reference: VS-1krohviga_390mm; ThermalTransmittance: 1.45946 kg/K/s3
AR_IFC_SEINAD - 01.Nimetus: Välissein; 02.Materjal: Silikaattellis; 03.Kategooria / tüüp: VS-1; 04.Tulepüsivus: -; 05.Asukoha info: Exterior; 06.Kandevelementide eristatud: bearing; 07.Helipidavus: 56dB; 06.Soojusläbivus: 0,72W/m2K; Phase Created: Existing

# IfcWallStandardCase: Basic Wall:VS-2.1_Juurdeehituse välissein 2 (14)
Type - PredefinedType: STANDARD; Material: __Soojustus EPS 57 mm, __Kergblokk 190 mm
Pset_WallCommon - LoadBearing: no; ExtendToStructure: no; IsExternal: yes; Reference: VS-2.1_Juurdeehituse välissein 2; ThermalTransmittance: 4 kg/K/s3
AR_IFC_SEINAD - 01.Nimetus: Välissein; 02.Materjal: Columbia kivi; 03.Kategooria / tüüp: VS-2.1; 04.Tulepüsivus: REI-60; 05.Asukoha info: Exterior; 06.Kandevelementide eristatud: bearing; 07.Helipidavus: 56dB; 06.Soojusläbivus: 0,18W/m2K; Phase Created: New Construction
Name (Basic Wall:VS-2.1_Juurdeehituse välissein 2:...) | In
917076 | uus 2 korrus
921838 | uus 2 korrus
921877 | uus 2 korrus
922112 | uus 2 korrus
922508 | uus 2 korrus
923022 | uus 2 korrus
923023 | uus 2 korrus
933224 | uus 3 korrus
933226 | uus 3 korrus
933227 | uus 3 korrus
933228 | uus 3 korrus
933231 | uus 3 korrus
933232 | uus 3 korrus
933233 | uus 3 korrus

# IfcWallStandardCase: Basic Wall:VS-2.2_Juurdeehituse välissein (29)
Type - PredefinedType: STANDARD; Material: __Tuuletõkkeplaat 9 mm, __Soojustus EPS 200 mm, __Kergblokk 190 mm
Pset_WallCommon - LoadBearing: no; IsExternal: yes; Reference: VS-2.2_Juurdeehituse välissein; ThermalTransmittance: 4 kg/K/s3
AR_IFC_SEINAD - 01.Nimetus: Välissein; 02.Materjal: Columbia kivi; 03.Kategooria / tüüp: VS-2.2; 04.Tulepüsivus: REI-60; 05.Asukoha info: Exterior; 06.Kandevelementide eristatud: bearing; 07.Helipidavus: 56dB; 06.Soojusläbivus: 0,15W/m2K; Phase Created: New Construction
Name (Basic Wall:VS-2.2_Juurdeehituse välissein:...) | In | ExtendToStructure
309975 | Vundament | no
310801 | Vundament | yes
310907 | Vundament | no
377004 | Vundament | yes
377151 | uus 2 korrus | no
378082 | Vundament | no
379398 | uus 2 korrus | no
381772 | Vundament | yes
896983 | Vundament | no
897494 | Vundament | no
931607 | uus 2 korrus | no
931608 | uus 2 korrus | no
933160 | uus 3 korrus | no
933161 | uus 3 korrus | no
933260 | uus 3 korrus | no
933261 | uus 3 korrus | no
1013210 | Vundament | no
1299815 | uus 3 korrus | no
1557649 | Vundament | no
1557706 | Vundament | no
1557779 | Vundament | no
1559790 | uus 2 korrus | no
1559791 | uus 2 korrus | no
1559792 | uus 2 korrus | no
1559834 | uus 3 korrus | no
1559835 | uus 3 korrus | no
1559836 | uus 3 korrus | no
1560450 | uus 2 korrus | no
1561749 | uus 3 korrus | no

# IfcWallStandardCase: Basic Wall:VS-2_olemasolev sein fassaadikassettidega (25)
Type - PredefinedType: STANDARD; Material: __Tuuletõkkeplaat 9 mm, __Soojustus EPS 200 mm, Brick, Common 450 mm, __Kips GN13_tava 20 mm
Pset_WallCommon - ExtendToStructure: no; IsExternal: yes; Reference: VS-2_olemasolev sein fassaadikassettidega; ThermalTransmittance: 1.2 kg/K/s3
AR_IFC_SEINAD - 01.Nimetus: Välissein; 02.Materjal: Silikaattellis; 03.Kategooria / tüüp: VS-2; 04.Tulepüsivus: REI-60; 05.Asukoha info: Exterior; 06.Kandevelementide eristatud: bearing; 07.Helipidavus: 56dB; 06.Soojusläbivus: 0,15W/m2K; Phase Created: Existing
Name | In | LoadBearing
SEIN - 002 | 4 korrus | yes
SEIN - 001 | 1 korrus | no
SEIN - 001 | 2 korrus | no
SEIN - 001 | 3 korrus | no
SEIN - 001 | 4 korrus | no
SEIN - 002 | 1 korrus | no
SEIN - 002 | 1 korrus | yes
3 x SEIN - 003 | 1 korrus | no
SEIN - 002 | 2 korrus | no
SEIN - 002 | 2 korrus | yes
3 x SEIN - 003 | 2 korrus | no
SEIN - 002 | 3 korrus | no
SEIN - 002 | 3 korrus | yes
3 x SEIN - 003 | 3 korrus | no
SEIN - 002 | 4 korrus | no
3 x SEIN - 003 | 4 korrus | no
Basic Wall:VS-2_olemasolev sein fassaadikassettidega:1681789 | 2 korrus | no

# IfcWallStandardCase: Basic Wall:VS-3.1_SW kergpaneel 100mm (6)
In: 1 korrus
Type - PredefinedType: STANDARD; Material: External face timepruun h=1100mm 1 mm, Core Mineral wool Mineral Wool h=1100mm 98 mm, Internal face RAL 7035 h=1100mm 1 mm
Pset_WallCommon - LoadBearing: no; IsExternal: yes; Reference: VS-3.1_SW kergpaneel 100mm
Pset_ManufacturerTypeInformation - Manufacturer: Ruukki
AR_IFC_SEINAD - 01.Nimetus: Välissein; 02.Materjal: SW seinapaneel; 03.Kategooria / tüüp: VS-3.1; 04.Tulepüsivus: EI-60; 05.Asukoha info: Exterior; 06.Kandevelementide eristatud: nonbearing; 07.Helipidavus: 29 dB; 06.Soojusläbivus: 0,45W/m2K; Phase Created: New Construction
Name (Basic Wall:VS-3.1_SW kergpaneel 100mm:...) | ExtendToStructure
990233 | yes
990314 | no
990656 | no
990735 | no
1256818 | yes
1256850 | no

# IfcWallStandardCase: Basic Wall:VS-3_vent.ruumide ja ladude välissein (9)
Type - PredefinedType: STANDARD; Material: External face timepruun h=1100mm 54 mm, Core Mineral wool Mineral Wool h=1100mm 200 mm, __Kips GKB_niiskuskindel 12 mm
Pset_WallCommon - ExtendToStructure: no; IsExternal: yes; Reference: VS-3_vent.ruumide ja ladude välissein
Pset_ManufacturerTypeInformation - Manufacturer: Ruukki
AR_IFC_SEINAD - 01.Nimetus: Välissein; 02.Materjal: Metallkarkass_soojustus; 03.Kategooria / tüüp: VS-3; 04.Tulepüsivus: EI-60; 05.Asukoha info: Exterior; 06.Kandevelementide eristatud: bearing; 07.Helipidavus: -; 06.Soojusläbivus: 0,16W/m2K; Phase Created: New Construction
Name (Basic Wall:VS-3_vent.ruumide ja ladude välissein:...) | In | LoadBearing
749950 | Katusekorrus | yes
795364 | Katusekorrus | no
795415 | Katusekorrus | no
795488 | Katusekorrus | no
795529 | Katusekorrus | no
795624 | Katusekorrus | no
1008999 | uus Katus | no
1009001 | uus Katus | no
1014851 | Katusekorrus | yes

# IfcWallStandardCase: Basic Wall:ol.olev liftišahti sein (3)
In: 2 korrus
Type - PredefinedType: STANDARD; Material: Lifti sein_hall 100 mm
Pset_WallCommon - LoadBearing: no; ExtendToStructure: no; IsExternal: yes; Reference: ol.olev liftišahti sein
AR_IFC_SEINAD - 01.Nimetus: Ol.olev liftišahti sein; 02.Materjal: Metall; 03.Kategooria / tüüp: -; 04.Tulepüsivus: -; 05.Asukoha info: Exterior; 06.Kandevelementide eristatud: nonbearing; 07.Helipidavus: -; 06.Soojusläbivus: -; Phase Created: Existing
Name
SEIN - 006
SEIN - 008
SEIN - 007

# IfcWallStandardCase: Basic Wall:vundament 390mm (2)
In: 1 korrus
Type - PredefinedType: STANDARD; Material: Betoon 390 mm
Pset_WallCommon - LoadBearing: no; ExtendToStructure: no; IsExternal: yes; Reference: vundament 390mm
Name | Phase Created
SEIN - 001 | Existing
SEIN - 001 | New Construction

# IfcWindow: A-01, Aken_neljaosaline:A-01:1285516
In: 1 korrus
Type - ParameterTakesPrecedence: no; Sizeable: no; Material: PihlaPRO Tavallinen lasi, Alumiini, RAL 9010 valkoinen, Mänty, NCS S 0502-Y Valkoinen, Kumi
OverallHeight: 1476.18 mm; OverallWidth: 1560 mm
Pset_WindowCommon - IsExternal: yes; Reference: A-01
AR_IFC_AKNAD - 01.Nimetus: Välisaken; 02.Materjal: PVC; 03.Kategooria / tüüp: A-01; 04.Avamõõdu geomeetria: 1390x1540; 05.Asukoha info: Exterior; 06.Soojusläbivus: 0.8 W/m2K; 07.Helipidavus: 34 dB; 08.Veepidavus: 7A; 09.Õhuläbilaskvus: klass 4; 10.Tulekindlus: -; 11.Vastupanu tulekoormusele: C3; 12.Klaaspakett: 3x klaaspakett; 13.Klaasingu erisused: päiksekaitseklaas; 14.Päikesekiirgus tegur (g-väärtus): 0.3; 15.Avanemine: Folding to Right and up; 16.Liigendatus: 4-ruuduga; 17.Sulused, lukustus: mikrotuulutus, tootja; 18.Viimistlus: RAL 8019

# IfcWindow: A-02, Aken_1850x2100:A-02:239765
In: 4 korrus
Type - OperationType: DOUBLE_PANEL_VERTICAL; ParameterTakesPrecedence: no; Sizeable: no; Material: Paint - Titanium White, Paint - Dark Gray, Glass - Clear Fast
OverallHeight: 2100 mm; OverallWidth: 1850 mm
Pset_WindowCommon - IsExternal: yes; Reference: A-02
AR_IFC_AKNAD - 01.Nimetus: Välisaken; 02.Materjal: PVC; 03.Kategooria / tüüp: A-02; 04.Avamõõdu geomeetria: 1850x2100; 05.Asukoha info: Exterior; 06.Soojusläbivus: 0.8 W/m2K; 07.Helipidavus: 34 dB; 08.Veepidavus: 7A; 09.Õhuläbilaskvus: klass 4; 10.Tulekindlus: -; 11.Vastupanu tulekoormusele: C3; 12.Klaaspakett: 3x klaaspakett; 13.Klaasingu erisused: päiksekaitseklaas; 14.Päikesekiirgus tegur (g-väärtus): 0.3; 15.Avanemine: Folding to Up; 16.Liigendatus: 4-ruuduga; 17.Sulused, lukustus: Suitsueemalduaken; 18.Viimistlus: RAL 8019

# IfcWindow: A-03, Uus aken_kaheosaline:A-03:397021
In: uus 1 korrus
Type - ParameterTakesPrecedence: no; Sizeable: no; Material: PihlaPRO Tavallinen lasi, Alumiini, RAL 9010 valkoinen, Mänty, NCS S 0502-Y Valkoinen, Kumi
OverallHeight: 721.493 mm; OverallWidth: 1620 mm
Pset_WindowCommon - IsExternal: yes; Reference: A-03
AR_IFC_AKNAD - 01.Nimetus: Välisaken; 02.Materjal: PVC; 03.Kategooria / tüüp: A-03; 04.Avamõõdu geomeetria: 600x1600; 05.Asukoha info: Exterior; 06.Soojusläbivus: 0.8 W/m2K; 07.Helipidavus: 34 dB; 08.Veepidavus: 7A; 09.Õhuläbilaskvus: klass 4; 10.Tulekindlus: -; 11.Vastupanu tulekoormusele: C3; 12.Klaaspakett: 3x klaaspakett; 13.Klaasingu erisused: -; 14.Päikesekiirgus tegur (g-väärtus): 0.5; 15.Avanemine: Folding to Right and up; 16.Liigendatus: 2-ruuduga; 17.Sulused, lukustus: mikrotuulutus, tootja; 18.Viimistlus: RAL 8019

# IfcWindow: A-04 (3)
In: uus 1 korrus
Type - ParameterTakesPrecedence: no; Sizeable: no; Material: EP Tavallinen lasi, Alumiini, RAL 9010 valkoinen, Mänty, NCS S 0502-Y Valkoinen, Kumi
OverallHeight: 1061.49 mm; OverallWidth: 1420 mm
Pset_WindowCommon - IsExternal: yes; Reference: A-04
AR_IFC_AKNAD - 01.Nimetus: Välisaken; 02.Materjal: PVC; 03.Kategooria / tüüp: A-04; 04.Avamõõdu geomeetria: 940x1400; 05.Asukoha info: Exterior; 06.Soojusläbivus: 0.8 W/m2K; 07.Helipidavus: 34 dB; 08.Veepidavus: 7A; 09.Õhuläbilaskvus: klass 4; 10.Tulekindlus: -; 11.Vastupanu tulekoormusele: C3; 12.Klaaspakett: 3x klaaspakett; 13.Klaasingu erisused: -; 14.Päikesekiirgus tegur (g-väärtus): 0.5; 15.Avanemine: Folding to Right and up; 16.Liigendatus: 2-ruuduga; 17.Sulused, lukustus: mikrotuulutus, tootja; 18.Viimistlus: RAL 8019
Name (Uus aken_kaheosaline:A-04:...)
901008
901806
901816

# IfcWindow: A-05, Uus aken_kaheosaline:A-05:901826
In: uus 1 korrus
Type - ParameterTakesPrecedence: no; Sizeable: no; Material: EP Tavallinen lasi, Alumiini, RAL 9010 valkoinen, Mänty, NCS S 0502-Y Valkoinen, Kumi
OverallHeight: 1061.49 mm; OverallWidth: 1820 mm
Pset_WindowCommon - IsExternal: yes; Reference: A-05
AR_IFC_AKNAD - 01.Nimetus: Välisaken; 02.Materjal: PVC; 03.Kategooria / tüüp: A-05; 04.Avamõõdu geomeetria: 940x1800; 05.Asukoha info: Exterior; 06.Soojusläbivus: 0.8 W/m2K; 07.Helipidavus: 34 dB; 08.Veepidavus: 7A; 09.Õhuläbilaskvus: klass 4; 10.Tulekindlus: -; 11.Vastupanu tulekoormusele: C3; 12.Klaaspakett: 3x klaaspakett; 13.Klaasingu erisused: -; 14.Päikesekiirgus tegur (g-väärtus): 0.5; 15.Avanemine: Folding to Right and up; 16.Liigendatus: 2-ruuduga; 17.Sulused, lukustus: mikrotuulutus, tootja; 18.Viimistlus: RAL 8019

# IfcWindow: AKEN - 001 (2)
Type - ParameterTakesPrecedence: no; Sizeable: no; Material: Paint - Light Gray, Paint - Titanium White, Paint - Dark Gray
OverallHeight: 4200 mm; Group: Model Group:Olemasolev aken 4200x8460(h):1743131
Pset_WindowCommon - IsExternal: yes; ThermalTransmittance: 0 kg/K/s3; GlazingAreaFraction: 0
Name | In | OverallWidth (mm) | Reference
AKEN - 001 60764:AKEN - 001 60764:239400 | 2 korrus | 445.564 | AKEN - 001 60764
AKEN - 001 109507:AKEN - 001 109507:239563 | 3 korrus | 394.7 | AKEN - 001 109507

# IfcWindow: AKEN - 001 (3)
Type - ParameterTakesPrecedence: no; Sizeable: no; Material: Paint - Titanium White, Paint - Dark Gray, Glass - Clear Fast
OverallWidth: 4200 mm; Group: Model Group:Olemasolev aken 4200x8460(h):1743131
Pset_WindowCommon - IsExternal: yes; ThermalTransmittance: 0 kg/K/s3
Name | In | OverallHeight (mm) | Reference | GlazingAreaFraction
AKEN - 001 59458:AKEN - 001 59458:239399 | 2 korrus | 2124.87 | AKEN - 001 59458 | 7.46849
AKEN - 001 108205:AKEN - 001 108205:239562 | 3 korrus | 2934.87 | AKEN - 001 108205 | 10.4561
AKEN - 001 148806:AKEN - 001 148806:239789 | 4 korrus | 2560 | AKEN - 001 148806 | 9.1568

# IfcWindow: AKEN - 003 (3)
In: 2 korrus
Type - ParameterTakesPrecedence: no; Sizeable: no; Material: Paint - Dark Gray, Glass - Clear Fast
Pset_WindowCommon - IsExternal: yes; ThermalTransmittance: 0 kg/K/s3
Name | OverallHeight (mm) | OverallWidth (mm) | Reference | GlazingAreaFraction
AKEN - 003 67802:AKEN - 003 67802:239418 | 1800 | 15500 | AKEN - 003 67802 | 24.9355
AKEN - 003 68899:AKEN - 003 68899:239419 | 15579.7 | 1877.86 | AKEN - 003 68899 | 26.4007
AKEN - 003 69996:AKEN - 003 69996:239420 | 1900 | 15579.7 | AKEN - 003 69996 | 26.7295

# IfcWindow: Aken_1300x1500 (10)
In: 1 korrus
Type - OperationType: SINGLE_PANEL; ParameterTakesPrecedence: no; Sizeable: no; Material: Paint - Dark Gray, Paint - Titanium White, Glass - Clear Fast
OverallHeight: 1500 mm; OverallWidth: 1300 mm
Pset_WindowCommon - IsExternal: yes; Reference: Aken_1300x1500
AR_IFC_AKNAD - 01.Nimetus: Välisaken; 02.Materjal: PVC; 03.Kategooria / tüüp: Olemasolev aken; 04.Avamõõdu geomeetria: 1300x1500; 05.Asukoha info: Exterior
Name (Aken_1300x1500:Aken_1300x1500:...)
239101
239121
239122
239123
239124
239125
239126
239127
239128
239133

# IfcWindow: Aken_1390x2100 (6)
In: 1 korrus
Type - OperationType: DOUBLE_PANEL_VERTICAL; ParameterTakesPrecedence: no; Sizeable: no; Material: Paint - Dark Gray, Paint - Titanium White, Glass - Clear Fast
OverallHeight: 1390 mm; OverallWidth: 2100 mm
Pset_WindowCommon - IsExternal: yes; Reference: Aken_1390x2100
AR_IFC_AKNAD - 01.Nimetus: Välisaken; 02.Materjal: PVC; 03.Kategooria / tüüp: Olemasolev aken; 04.Avamõõdu geomeetria: 1390x2100; 05.Asukoha info: Exterior
Name (Aken_1390x2100:Aken_1390x2100:...)
239105
239106
239107
239108
239109
239110

# IfcWindow: Aken_1850x2100 (53)
Type - OperationType: DOUBLE_PANEL_VERTICAL; ParameterTakesPrecedence: no; Sizeable: no; Material: Paint - Titanium White, Paint - Dark Gray, Glass - Clear Fast
OverallHeight: 2100 mm; OverallWidth: 1850 mm
Pset_WindowCommon - IsExternal: yes; Reference: Aken_1850x2100
AR_IFC_AKNAD - 01.Nimetus: Välisaken; 02.Materjal: PVC; 03.Kategooria / tüüp: Olemasolev aken; 04.Avamõõdu geomeetria: 1850x2100; 05.Asukoha info: Exterior
Name (Aken_1850x2100:Aken_1850x2100:...) | In
239370 | 2 korrus
239371 | 2 korrus
239372 | 2 korrus
239373 | 2 korrus
239374 | 2 korrus
239375 | 2 korrus
239376 | 2 korrus
239377 | 2 korrus
239378 | 2 korrus
239391 | 2 korrus
239392 | 2 korrus
239393 | 2 korrus
239394 | 2 korrus
239395 | 2 korrus
239396 | 2 korrus
239397 | 2 korrus
239398 | 2 korrus
239416 | 2 korrus
239540 | 3 korrus
239541 | 3 korrus
239542 | 3 korrus
239543 | 3 korrus
239544 | 3 korrus
239545 | 3 korrus
239546 | 3 korrus
239547 | 3 korrus
239548 | 3 korrus
239554 | 3 korrus
239555 | 3 korrus
239556 | 3 korrus
239557 | 3 korrus
239558 | 3 korrus
239559 | 3 korrus
239560 | 3 korrus
239561 | 3 korrus
239586 | 3 korrus
239754 | 4 korrus
239755 | 4 korrus
239756 | 4 korrus
239757 | 4 korrus
239758 | 4 korrus
239759 | 4 korrus
239760 | 4 korrus
239761 | 4 korrus
239762 | 4 korrus
239781 | 4 korrus
239782 | 4 korrus
239783 | 4 korrus
239784 | 4 korrus
239785 | 4 korrus
239786 | 4 korrus
239787 | 4 korrus
239788 | 4 korrus

# IfcWindow: Aken_2450x1480 (3)
Type - OperationType: DOUBLE_PANEL_VERTICAL; ParameterTakesPrecedence: no; Sizeable: no; Material: Paint - Dark Gray, Paint - Titanium White, Glass - Clear Fast
OverallHeight: 1479.66 mm; OverallWidth: 2450 mm
Pset_WindowCommon - IsExternal: yes; Reference: Aken_2450x1480
AR_IFC_AKNAD - 01.Nimetus: Välisaken; 02.Materjal: PVC; 03.Kategooria / tüüp: Olemasolev aken; 04.Avamõõdu geomeetria: 2450x1480; 05.Asukoha info: Exterior
Name (Aken_2450x1480:Aken_2450x1480:...) | In
239404 | 2 korrus
239565 | 3 korrus
239791 | 4 korrus

# IfcWindow: KL-01, Katuseluuk:KL-01:980459
In: Katusekorrus
Type - ParameterTakesPrecedence: no; Sizeable: no; Classification: B3010400 Roof Flashing & Trim (Uniformat); Material: Finish - Black, Metal - Lexcor - Stainless Steel
OverallHeight: 541.3 mm; OverallWidth: 1205.1 mm
Pset_WindowCommon - IsExternal: no; Reference: KL-01

# IfcWindow: VR-01, Ventrestid:VR-01:1380497
In: 1 korrus
Type - ParameterTakesPrecedence: no; Sizeable: no; Material: Steel/Aluminium
OverallHeight: 1400 mm; OverallWidth: 1400 mm
Pset_WindowCommon - IsExternal: yes; Reference: VR-01

# IfcWindow: VR-02, Ventrestid:VR-02:1376210
In: 1 korrus
Type - ParameterTakesPrecedence: no; Sizeable: no; Material: Steel/Aluminium
OverallHeight: 1000 mm; OverallWidth: 400 mm
Pset_WindowCommon - IsExternal: yes; Reference: VR-02

# IfcWindow: liftiaken 2 (9)
Type - ParameterTakesPrecedence: no; Sizeable: no; Material: Glass - Oknoplast - Glass, Steel/Aluminium
OverallHeight: 1030 mm; OverallWidth: 1300 mm; Group: Model Group:KLF-05:1742889
Pset_WindowCommon - IsExternal: yes; Reference: liftiaken 2
Name (lifti aken:liftiaken 2:...) | In
1561275 | uus 3 korrus
1674678 | 1 korrus
1674783 | 1 korrus
1674798 | 1 korrus
1674811 | 2 korrus
1674826 | uus 2 korrus
1674836 | uus 2 korrus
1674848 | 3 korrus
1674918 | uus 3 korrus
